VERSION 5.8 ;
BUSBITCHARS "[]" ;
DIVIDERCHAR "/" ;
UNITS
    DATABASE MICRONS 1000 ;
END UNITS

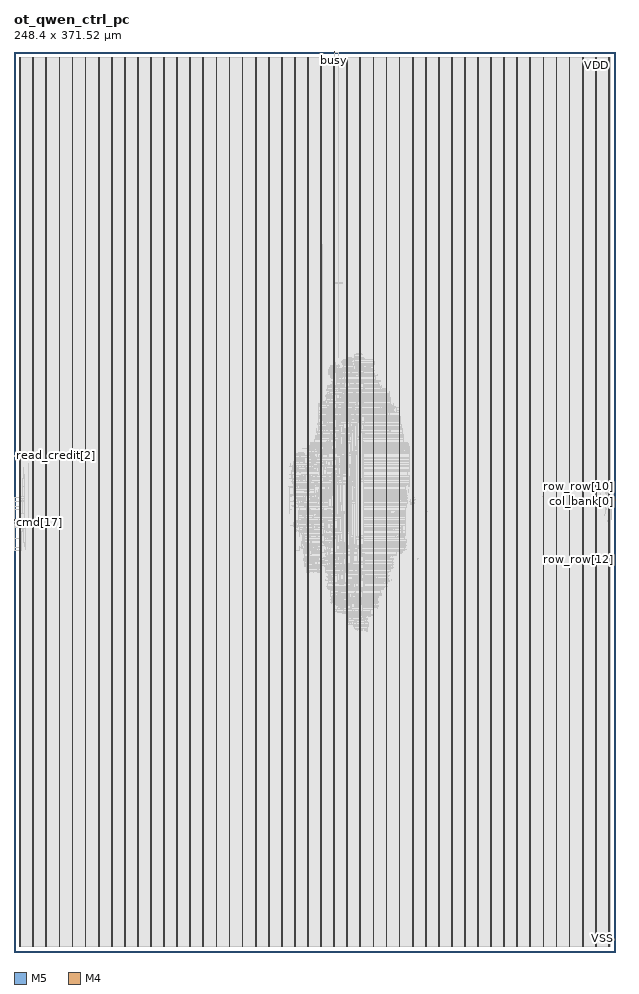
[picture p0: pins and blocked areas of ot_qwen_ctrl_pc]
MACRO ot_qwen_ctrl_pc
  FOREIGN ot_qwen_ctrl_pc 0 0 ;
  CLASS BLOCK ;
  SIZE 248.4 BY 371.52 ;
  PIN busy
    DIRECTION OUTPUT ;
    USE SIGNAL ;
    PORT
      LAYER M5 ;
        RECT  132.144 371.436 132.168 371.52 ;
    END
  END busy
  PIN clk
    DIRECTION INPUT ;
    USE SIGNAL ;
    PORT
      LAYER M5 ;
        RECT  132.24 371.436 132.264 371.52 ;
    END
  END clk
  PIN cmd[0]
    DIRECTION INPUT ;
    USE SIGNAL ;
    PORT
      LAYER M4 ;
        RECT  0 175.728 0.084 175.752 ;
    END
  END cmd[0]
  PIN cmd[10]
    DIRECTION INPUT ;
    USE SIGNAL ;
    PORT
      LAYER M4 ;
        RECT  0 176.688 0.084 176.712 ;
    END
  END cmd[10]
  PIN cmd[11]
    DIRECTION INPUT ;
    USE SIGNAL ;
    PORT
      LAYER M4 ;
        RECT  0 176.784 0.084 176.808 ;
    END
  END cmd[11]
  PIN cmd[12]
    DIRECTION INPUT ;
    USE SIGNAL ;
    PORT
      LAYER M4 ;
        RECT  0 176.88 0.084 176.904 ;
    END
  END cmd[12]
  PIN cmd[13]
    DIRECTION INPUT ;
    USE SIGNAL ;
    PORT
      LAYER M4 ;
        RECT  0 176.976 0.084 177 ;
    END
  END cmd[13]
  PIN cmd[14]
    DIRECTION INPUT ;
    USE SIGNAL ;
    PORT
      LAYER M4 ;
        RECT  0 177.072 0.084 177.096 ;
    END
  END cmd[14]
  PIN cmd[15]
    DIRECTION INPUT ;
    USE SIGNAL ;
    PORT
      LAYER M4 ;
        RECT  0 177.168 0.084 177.192 ;
    END
  END cmd[15]
  PIN cmd[16]
    DIRECTION INPUT ;
    USE SIGNAL ;
    PORT
      LAYER M4 ;
        RECT  0 177.264 0.084 177.288 ;
    END
  END cmd[16]
  PIN cmd[17]
    DIRECTION INPUT ;
    USE SIGNAL ;
    PORT
      LAYER M4 ;
        RECT  0 177.36 0.084 177.384 ;
    END
  END cmd[17]
  PIN cmd[18]
    DIRECTION INPUT ;
    USE SIGNAL ;
    PORT
      LAYER M4 ;
        RECT  0 177.456 0.084 177.48 ;
    END
  END cmd[18]
  PIN cmd[19]
    DIRECTION INPUT ;
    USE SIGNAL ;
    PORT
      LAYER M4 ;
        RECT  0 177.552 0.084 177.576 ;
    END
  END cmd[19]
  PIN cmd[1]
    DIRECTION INPUT ;
    USE SIGNAL ;
    PORT
      LAYER M4 ;
        RECT  0 175.824 0.084 175.848 ;
    END
  END cmd[1]
  PIN cmd[20]
    DIRECTION INPUT ;
    USE SIGNAL ;
    PORT
      LAYER M4 ;
        RECT  0 177.648 0.084 177.672 ;
    END
  END cmd[20]
  PIN cmd[21]
    DIRECTION INPUT ;
    USE SIGNAL ;
    PORT
      LAYER M4 ;
        RECT  0 177.744 0.084 177.768 ;
    END
  END cmd[21]
  PIN cmd[22]
    DIRECTION INPUT ;
    USE SIGNAL ;
    PORT
      LAYER M4 ;
        RECT  0 177.84 0.084 177.864 ;
    END
  END cmd[22]
  PIN cmd[23]
    DIRECTION INPUT ;
    USE SIGNAL ;
    PORT
      LAYER M4 ;
        RECT  0 177.936 0.084 177.96 ;
    END
  END cmd[23]
  PIN cmd[24]
    DIRECTION INPUT ;
    USE SIGNAL ;
    PORT
      LAYER M4 ;
        RECT  0 178.032 0.084 178.056 ;
    END
  END cmd[24]
  PIN cmd[25]
    DIRECTION INPUT ;
    USE SIGNAL ;
    PORT
      LAYER M4 ;
        RECT  0 178.128 0.084 178.152 ;
    END
  END cmd[25]
  PIN cmd[26]
    DIRECTION INPUT ;
    USE SIGNAL ;
    PORT
      LAYER M4 ;
        RECT  0 178.224 0.084 178.248 ;
    END
  END cmd[26]
  PIN cmd[27]
    DIRECTION INPUT ;
    USE SIGNAL ;
    PORT
      LAYER M4 ;
        RECT  0 178.32 0.084 178.344 ;
    END
  END cmd[27]
  PIN cmd[28]
    DIRECTION INPUT ;
    USE SIGNAL ;
    PORT
      LAYER M4 ;
        RECT  0 178.416 0.084 178.44 ;
    END
  END cmd[28]
  PIN cmd[29]
    DIRECTION INPUT ;
    USE SIGNAL ;
    PORT
      LAYER M4 ;
        RECT  0 178.512 0.084 178.536 ;
    END
  END cmd[29]
  PIN cmd[2]
    DIRECTION INPUT ;
    USE SIGNAL ;
    PORT
      LAYER M4 ;
        RECT  0 175.92 0.084 175.944 ;
    END
  END cmd[2]
  PIN cmd[30]
    DIRECTION INPUT ;
    USE SIGNAL ;
    PORT
      LAYER M4 ;
        RECT  0 178.608 0.084 178.632 ;
    END
  END cmd[30]
  PIN cmd[31]
    DIRECTION INPUT ;
    USE SIGNAL ;
    PORT
      LAYER M4 ;
        RECT  0 178.704 0.084 178.728 ;
    END
  END cmd[31]
  PIN cmd[3]
    DIRECTION INPUT ;
    USE SIGNAL ;
    PORT
      LAYER M4 ;
        RECT  0 176.016 0.084 176.04 ;
    END
  END cmd[3]
  PIN cmd[4]
    DIRECTION INPUT ;
    USE SIGNAL ;
    PORT
      LAYER M4 ;
        RECT  0 176.112 0.084 176.136 ;
    END
  END cmd[4]
  PIN cmd[5]
    DIRECTION INPUT ;
    USE SIGNAL ;
    PORT
      LAYER M4 ;
        RECT  0 176.208 0.084 176.232 ;
    END
  END cmd[5]
  PIN cmd[6]
    DIRECTION INPUT ;
    USE SIGNAL ;
    PORT
      LAYER M4 ;
        RECT  0 176.304 0.084 176.328 ;
    END
  END cmd[6]
  PIN cmd[7]
    DIRECTION INPUT ;
    USE SIGNAL ;
    PORT
      LAYER M4 ;
        RECT  0 176.4 0.084 176.424 ;
    END
  END cmd[7]
  PIN cmd[8]
    DIRECTION INPUT ;
    USE SIGNAL ;
    PORT
      LAYER M4 ;
        RECT  0 176.496 0.084 176.52 ;
    END
  END cmd[8]
  PIN cmd[9]
    DIRECTION INPUT ;
    USE SIGNAL ;
    PORT
      LAYER M4 ;
        RECT  0 176.592 0.084 176.616 ;
    END
  END cmd[9]
  PIN cmd_credit
    DIRECTION OUTPUT ;
    USE SIGNAL ;
    PORT
      LAYER M4 ;
        RECT  0 204.72 0.084 204.744 ;
    END
  END cmd_credit
  PIN cmd_v
    DIRECTION INPUT ;
    USE SIGNAL ;
    PORT
      LAYER M4 ;
        RECT  0 204.816 0.084 204.84 ;
    END
  END cmd_v
  PIN col_bank[0]
    DIRECTION OUTPUT ;
    USE SIGNAL ;
    PORT
      LAYER M4 ;
        RECT  248.316 185.808 248.4 185.832 ;
    END
  END col_bank[0]
  PIN col_bank[1]
    DIRECTION OUTPUT ;
    USE SIGNAL ;
    PORT
      LAYER M4 ;
        RECT  248.316 185.904 248.4 185.928 ;
    END
  END col_bank[1]
  PIN col_bank[2]
    DIRECTION OUTPUT ;
    USE SIGNAL ;
    PORT
      LAYER M4 ;
        RECT  248.316 186 248.4 186.024 ;
    END
  END col_bank[2]
  PIN col_bank[3]
    DIRECTION OUTPUT ;
    USE SIGNAL ;
    PORT
      LAYER M4 ;
        RECT  248.316 186.096 248.4 186.12 ;
    END
  END col_bank[3]
  PIN col_bank[4]
    DIRECTION OUTPUT ;
    USE SIGNAL ;
    PORT
      LAYER M4 ;
        RECT  248.316 186.192 248.4 186.216 ;
    END
  END col_bank[4]
  PIN col_col[0]
    DIRECTION OUTPUT ;
    USE SIGNAL ;
    PORT
      LAYER M4 ;
        RECT  248.316 186.288 248.4 186.312 ;
    END
  END col_col[0]
  PIN col_col[1]
    DIRECTION OUTPUT ;
    USE SIGNAL ;
    PORT
      LAYER M4 ;
        RECT  248.316 186.384 248.4 186.408 ;
    END
  END col_col[1]
  PIN col_col[2]
    DIRECTION OUTPUT ;
    USE SIGNAL ;
    PORT
      LAYER M4 ;
        RECT  248.316 186.48 248.4 186.504 ;
    END
  END col_col[2]
  PIN col_col[3]
    DIRECTION OUTPUT ;
    USE SIGNAL ;
    PORT
      LAYER M4 ;
        RECT  248.316 186.576 248.4 186.6 ;
    END
  END col_col[3]
  PIN col_col[4]
    DIRECTION OUTPUT ;
    USE SIGNAL ;
    PORT
      LAYER M4 ;
        RECT  248.316 186.672 248.4 186.696 ;
    END
  END col_col[4]
  PIN col_v
    DIRECTION OUTPUT ;
    USE SIGNAL ;
    PORT
      LAYER M4 ;
        RECT  248.316 186.768 248.4 186.792 ;
    END
  END col_v
  PIN col_we
    DIRECTION OUTPUT ;
    USE SIGNAL ;
    PORT
      LAYER M4 ;
        RECT  248.316 186.864 248.4 186.888 ;
    END
  END col_we
  PIN fault
    DIRECTION OUTPUT ;
    USE SIGNAL ;
    PORT
      LAYER M5 ;
        RECT  132.336 371.436 132.36 371.52 ;
    END
  END fault
  PIN read_credit[0]
    DIRECTION INPUT ;
    USE SIGNAL ;
    PORT
      LAYER M4 ;
        RECT  0 204.912 0.084 204.936 ;
    END
  END read_credit[0]
  PIN read_credit[1]
    DIRECTION INPUT ;
    USE SIGNAL ;
    PORT
      LAYER M4 ;
        RECT  0 205.008 0.084 205.032 ;
    END
  END read_credit[1]
  PIN read_credit[2]
    DIRECTION INPUT ;
    USE SIGNAL ;
    PORT
      LAYER M4 ;
        RECT  0 205.104 0.084 205.128 ;
    END
  END read_credit[2]
  PIN row_bank[0]
    DIRECTION OUTPUT ;
    USE SIGNAL ;
    PORT
      LAYER M4 ;
        RECT  248.316 186.96 248.4 186.984 ;
    END
  END row_bank[0]
  PIN row_bank[1]
    DIRECTION OUTPUT ;
    USE SIGNAL ;
    PORT
      LAYER M4 ;
        RECT  248.316 187.056 248.4 187.08 ;
    END
  END row_bank[1]
  PIN row_bank[2]
    DIRECTION OUTPUT ;
    USE SIGNAL ;
    PORT
      LAYER M4 ;
        RECT  248.316 187.152 248.4 187.176 ;
    END
  END row_bank[2]
  PIN row_bank[3]
    DIRECTION OUTPUT ;
    USE SIGNAL ;
    PORT
      LAYER M4 ;
        RECT  248.316 187.248 248.4 187.272 ;
    END
  END row_bank[3]
  PIN row_bank[4]
    DIRECTION OUTPUT ;
    USE SIGNAL ;
    PORT
      LAYER M4 ;
        RECT  248.316 187.344 248.4 187.368 ;
    END
  END row_bank[4]
  PIN row_op[0]
    DIRECTION OUTPUT ;
    USE SIGNAL ;
    PORT
      LAYER M4 ;
        RECT  248.316 187.44 248.4 187.464 ;
    END
  END row_op[0]
  PIN row_op[1]
    DIRECTION OUTPUT ;
    USE SIGNAL ;
    PORT
      LAYER M4 ;
        RECT  248.316 187.536 248.4 187.56 ;
    END
  END row_op[1]
  PIN row_op[2]
    DIRECTION OUTPUT ;
    USE SIGNAL ;
    PORT
      LAYER M4 ;
        RECT  248.316 187.632 248.4 187.656 ;
    END
  END row_op[2]
  PIN row_row[0]
    DIRECTION OUTPUT ;
    USE SIGNAL ;
    PORT
      LAYER M4 ;
        RECT  248.316 187.728 248.4 187.752 ;
    END
  END row_row[0]
  PIN row_row[10]
    DIRECTION OUTPUT ;
    USE SIGNAL ;
    PORT
      LAYER M4 ;
        RECT  248.316 188.688 248.4 188.712 ;
    END
  END row_row[10]
  PIN row_row[11]
    DIRECTION OUTPUT ;
    USE SIGNAL ;
    PORT
      LAYER M4 ;
        RECT  248.316 188.784 248.4 188.808 ;
    END
  END row_row[11]
  PIN row_row[12]
    DIRECTION OUTPUT ;
    USE SIGNAL ;
    PORT
      LAYER M4 ;
        RECT  248.316 162 248.4 162.024 ;
    END
  END row_row[12]
  PIN row_row[13]
    DIRECTION OUTPUT ;
    USE SIGNAL ;
    PORT
      LAYER M4 ;
        RECT  248.316 162.096 248.4 162.12 ;
    END
  END row_row[13]
  PIN row_row[14]
    DIRECTION OUTPUT ;
    USE SIGNAL ;
    PORT
      LAYER M4 ;
        RECT  248.316 162.192 248.4 162.216 ;
    END
  END row_row[14]
  PIN row_row[15]
    DIRECTION OUTPUT ;
    USE SIGNAL ;
    PORT
      LAYER M4 ;
        RECT  248.316 162.288 248.4 162.312 ;
    END
  END row_row[15]
  PIN row_row[16]
    DIRECTION OUTPUT ;
    USE SIGNAL ;
    PORT
      LAYER M4 ;
        RECT  248.316 162.384 248.4 162.408 ;
    END
  END row_row[16]
  PIN row_row[17]
    DIRECTION OUTPUT ;
    USE SIGNAL ;
    PORT
      LAYER M4 ;
        RECT  248.316 162.48 248.4 162.504 ;
    END
  END row_row[17]
  PIN row_row[18]
    DIRECTION OUTPUT ;
    USE SIGNAL ;
    PORT
      LAYER M4 ;
        RECT  248.316 162.576 248.4 162.6 ;
    END
  END row_row[18]
  PIN row_row[1]
    DIRECTION OUTPUT ;
    USE SIGNAL ;
    PORT
      LAYER M4 ;
        RECT  248.316 187.824 248.4 187.848 ;
    END
  END row_row[1]
  PIN row_row[2]
    DIRECTION OUTPUT ;
    USE SIGNAL ;
    PORT
      LAYER M4 ;
        RECT  248.316 187.92 248.4 187.944 ;
    END
  END row_row[2]
  PIN row_row[3]
    DIRECTION OUTPUT ;
    USE SIGNAL ;
    PORT
      LAYER M4 ;
        RECT  248.316 188.016 248.4 188.04 ;
    END
  END row_row[3]
  PIN row_row[4]
    DIRECTION OUTPUT ;
    USE SIGNAL ;
    PORT
      LAYER M4 ;
        RECT  248.316 188.112 248.4 188.136 ;
    END
  END row_row[4]
  PIN row_row[5]
    DIRECTION OUTPUT ;
    USE SIGNAL ;
    PORT
      LAYER M4 ;
        RECT  248.316 188.208 248.4 188.232 ;
    END
  END row_row[5]
  PIN row_row[6]
    DIRECTION OUTPUT ;
    USE SIGNAL ;
    PORT
      LAYER M4 ;
        RECT  248.316 188.304 248.4 188.328 ;
    END
  END row_row[6]
  PIN row_row[7]
    DIRECTION OUTPUT ;
    USE SIGNAL ;
    PORT
      LAYER M4 ;
        RECT  248.316 188.4 248.4 188.424 ;
    END
  END row_row[7]
  PIN row_row[8]
    DIRECTION OUTPUT ;
    USE SIGNAL ;
    PORT
      LAYER M4 ;
        RECT  248.316 188.496 248.4 188.52 ;
    END
  END row_row[8]
  PIN row_row[9]
    DIRECTION OUTPUT ;
    USE SIGNAL ;
    PORT
      LAYER M4 ;
        RECT  248.316 188.592 248.4 188.616 ;
    END
  END row_row[9]
  PIN row_v
    DIRECTION OUTPUT ;
    USE SIGNAL ;
    PORT
      LAYER M4 ;
        RECT  248.316 162.672 248.4 162.696 ;
    END
  END row_v
  PIN rst_n
    DIRECTION INPUT ;
    USE SIGNAL ;
    PORT
      LAYER M5 ;
        RECT  132.432 371.436 132.456 371.52 ;
    END
  END rst_n
  PIN VDD
    DIRECTION INOUT ;
    USE POWER ;
    PORT
      LAYER M5 ;
        RECT  245.592 2.151 245.712 369.369 ;
        RECT  240.192 2.151 240.312 369.369 ;
        RECT  234.792 2.151 234.912 369.369 ;
        RECT  229.392 2.151 229.512 369.369 ;
        RECT  223.992 2.151 224.112 369.369 ;
        RECT  218.592 2.151 218.712 369.369 ;
        RECT  213.192 2.151 213.312 369.369 ;
        RECT  207.792 2.151 207.912 369.369 ;
        RECT  202.392 2.151 202.512 369.369 ;
        RECT  196.992 2.151 197.112 369.369 ;
        RECT  191.592 2.151 191.712 369.369 ;
        RECT  186.192 2.151 186.312 369.369 ;
        RECT  180.792 2.151 180.912 369.369 ;
        RECT  175.392 2.151 175.512 369.369 ;
        RECT  169.992 2.151 170.112 369.369 ;
        RECT  164.592 2.151 164.712 369.369 ;
        RECT  159.192 2.151 159.312 369.369 ;
        RECT  153.792 2.151 153.912 369.369 ;
        RECT  148.392 2.151 148.512 369.369 ;
        RECT  142.992 2.151 143.112 369.369 ;
        RECT  137.592 2.151 137.712 369.369 ;
        RECT  132.192 2.151 132.312 369.369 ;
        RECT  126.792 2.151 126.912 369.369 ;
        RECT  121.392 2.151 121.512 369.369 ;
        RECT  115.992 2.151 116.112 369.369 ;
        RECT  110.592 2.151 110.712 369.369 ;
        RECT  105.192 2.151 105.312 369.369 ;
        RECT  99.792 2.151 99.912 369.369 ;
        RECT  94.392 2.151 94.512 369.369 ;
        RECT  88.992 2.151 89.112 369.369 ;
        RECT  83.592 2.151 83.712 369.369 ;
        RECT  78.192 2.151 78.312 369.369 ;
        RECT  72.792 2.151 72.912 369.369 ;
        RECT  67.392 2.151 67.512 369.369 ;
        RECT  61.992 2.151 62.112 369.369 ;
        RECT  56.592 2.151 56.712 369.369 ;
        RECT  51.192 2.151 51.312 369.369 ;
        RECT  45.792 2.151 45.912 369.369 ;
        RECT  40.392 2.151 40.512 369.369 ;
        RECT  34.992 2.151 35.112 369.369 ;
        RECT  29.592 2.151 29.712 369.369 ;
        RECT  24.192 2.151 24.312 369.369 ;
        RECT  18.792 2.151 18.912 369.369 ;
        RECT  13.392 2.151 13.512 369.369 ;
        RECT  7.992 2.151 8.112 369.369 ;
        RECT  2.592 2.151 2.712 369.369 ;
    END
  END VDD
  PIN VSS
    DIRECTION INOUT ;
    USE GROUND ;
    PORT
      LAYER M5 ;
        RECT  245.4 2.137 245.52 369.383 ;
        RECT  240 2.137 240.12 369.383 ;
        RECT  234.6 2.137 234.72 369.383 ;
        RECT  229.2 2.137 229.32 369.383 ;
        RECT  223.8 2.137 223.92 369.383 ;
        RECT  218.4 2.137 218.52 369.383 ;
        RECT  213 2.137 213.12 369.383 ;
        RECT  207.6 2.137 207.72 369.383 ;
        RECT  202.2 2.137 202.32 369.383 ;
        RECT  196.8 2.137 196.92 369.383 ;
        RECT  191.4 2.137 191.52 369.383 ;
        RECT  186 2.137 186.12 369.383 ;
        RECT  180.6 2.137 180.72 369.383 ;
        RECT  175.2 2.137 175.32 369.383 ;
        RECT  169.8 2.137 169.92 369.383 ;
        RECT  164.4 2.137 164.52 369.383 ;
        RECT  159 2.137 159.12 369.383 ;
        RECT  153.6 2.137 153.72 369.383 ;
        RECT  148.2 2.137 148.32 369.383 ;
        RECT  142.8 2.137 142.92 369.383 ;
        RECT  137.4 2.137 137.52 369.383 ;
        RECT  132 2.137 132.12 369.383 ;
        RECT  126.6 2.137 126.72 369.383 ;
        RECT  121.2 2.137 121.32 369.383 ;
        RECT  115.8 2.137 115.92 369.383 ;
        RECT  110.4 2.137 110.52 369.383 ;
        RECT  105 2.137 105.12 369.383 ;
        RECT  99.6 2.137 99.72 369.383 ;
        RECT  94.2 2.137 94.32 369.383 ;
        RECT  88.8 2.137 88.92 369.383 ;
        RECT  83.4 2.137 83.52 369.383 ;
        RECT  78 2.137 78.12 369.383 ;
        RECT  72.6 2.137 72.72 369.383 ;
        RECT  67.2 2.137 67.32 369.383 ;
        RECT  61.8 2.137 61.92 369.383 ;
        RECT  56.4 2.137 56.52 369.383 ;
        RECT  51 2.137 51.12 369.383 ;
        RECT  45.6 2.137 45.72 369.383 ;
        RECT  40.2 2.137 40.32 369.383 ;
        RECT  34.8 2.137 34.92 369.383 ;
        RECT  29.4 2.137 29.52 369.383 ;
        RECT  24 2.137 24.12 369.383 ;
        RECT  18.6 2.137 18.72 369.383 ;
        RECT  13.2 2.137 13.32 369.383 ;
        RECT  7.8 2.137 7.92 369.383 ;
        RECT  2.4 2.137 2.52 369.383 ;
    END
  END VSS
  OBS
    LAYER RVTN ;
     RECT  2.16 2.16 246.24 2.295 ;
     RECT  2.16 2.565 246.24 2.835 ;
     RECT  2.16 3.105 246.24 3.375 ;
     RECT  2.16 3.645 246.24 3.915 ;
     RECT  2.16 4.185 246.24 4.455 ;
     RECT  2.16 4.725 246.24 4.995 ;
     RECT  2.16 5.265 246.24 5.535 ;
     RECT  2.16 5.805 246.24 6.075 ;
     RECT  2.16 6.345 246.24 6.615 ;
     RECT  2.16 6.885 246.24 7.155 ;
     RECT  2.16 7.425 246.24 7.695 ;
     RECT  2.16 7.965 246.24 8.235 ;
     RECT  2.16 8.505 246.24 8.775 ;
     RECT  2.16 9.045 246.24 9.315 ;
     RECT  2.16 9.585 246.24 9.855 ;
     RECT  2.16 10.125 246.24 10.395 ;
     RECT  2.16 10.665 246.24 10.935 ;
     RECT  2.16 11.205 246.24 11.475 ;
     RECT  2.16 11.745 246.24 12.015 ;
     RECT  2.16 12.285 246.24 12.555 ;
     RECT  2.16 12.825 246.24 13.095 ;
     RECT  2.16 13.365 246.24 13.635 ;
     RECT  2.16 13.905 246.24 14.175 ;
     RECT  2.16 14.445 246.24 14.715 ;
     RECT  2.16 14.985 246.24 15.255 ;
     RECT  2.16 15.525 246.24 15.795 ;
     RECT  2.16 16.065 246.24 16.335 ;
     RECT  2.16 16.605 246.24 16.875 ;
     RECT  2.16 17.145 246.24 17.415 ;
     RECT  2.16 17.685 246.24 17.955 ;
     RECT  2.16 18.225 246.24 18.495 ;
     RECT  2.16 18.765 246.24 19.035 ;
     RECT  2.16 19.305 246.24 19.575 ;
     RECT  2.16 19.845 246.24 20.115 ;
     RECT  2.16 20.385 246.24 20.655 ;
     RECT  2.16 20.925 246.24 21.195 ;
     RECT  2.16 21.465 246.24 21.735 ;
     RECT  2.16 22.005 246.24 22.275 ;
     RECT  2.16 22.545 246.24 22.815 ;
     RECT  2.16 23.085 246.24 23.355 ;
     RECT  2.16 23.625 246.24 23.895 ;
     RECT  2.16 24.165 246.24 24.435 ;
     RECT  2.16 24.705 246.24 24.975 ;
     RECT  2.16 25.245 246.24 25.515 ;
     RECT  2.16 25.785 246.24 26.055 ;
     RECT  2.16 26.325 246.24 26.595 ;
     RECT  2.16 26.865 246.24 27.135 ;
     RECT  2.16 27.405 246.24 27.675 ;
     RECT  2.16 27.945 246.24 28.215 ;
     RECT  2.16 28.485 246.24 28.755 ;
     RECT  2.16 29.025 246.24 29.295 ;
     RECT  2.16 29.565 246.24 29.835 ;
     RECT  2.16 30.105 246.24 30.375 ;
     RECT  2.16 30.645 246.24 30.915 ;
     RECT  2.16 31.185 246.24 31.455 ;
     RECT  2.16 31.725 246.24 31.995 ;
     RECT  2.16 32.265 246.24 32.535 ;
     RECT  2.16 32.805 246.24 33.075 ;
     RECT  2.16 33.345 246.24 33.615 ;
     RECT  2.16 33.885 246.24 34.155 ;
     RECT  2.16 34.425 246.24 34.695 ;
     RECT  2.16 34.965 246.24 35.235 ;
     RECT  2.16 35.505 246.24 35.775 ;
     RECT  2.16 36.045 246.24 36.315 ;
     RECT  2.16 36.585 246.24 36.855 ;
     RECT  2.16 37.125 246.24 37.395 ;
     RECT  2.16 37.665 246.24 37.935 ;
     RECT  2.16 38.205 246.24 38.475 ;
     RECT  2.16 38.745 246.24 39.015 ;
     RECT  2.16 39.285 246.24 39.555 ;
     RECT  2.16 39.825 246.24 40.095 ;
     RECT  2.16 40.365 246.24 40.635 ;
     RECT  2.16 40.905 246.24 41.175 ;
     RECT  2.16 41.445 246.24 41.715 ;
     RECT  2.16 41.985 246.24 42.255 ;
     RECT  2.16 42.525 246.24 42.795 ;
     RECT  2.16 43.065 246.24 43.335 ;
     RECT  2.16 43.605 246.24 43.875 ;
     RECT  2.16 44.145 246.24 44.415 ;
     RECT  2.16 44.685 246.24 44.955 ;
     RECT  2.16 45.225 246.24 45.495 ;
     RECT  2.16 45.765 246.24 46.035 ;
     RECT  2.16 46.305 246.24 46.575 ;
     RECT  2.16 46.845 246.24 47.115 ;
     RECT  2.16 47.385 246.24 47.655 ;
     RECT  2.16 47.925 246.24 48.195 ;
     RECT  2.16 48.465 246.24 48.735 ;
     RECT  2.16 49.005 246.24 49.275 ;
     RECT  2.16 49.545 246.24 49.815 ;
     RECT  2.16 50.085 246.24 50.355 ;
     RECT  2.16 50.625 246.24 50.895 ;
     RECT  2.16 51.165 246.24 51.435 ;
     RECT  2.16 51.705 246.24 51.975 ;
     RECT  2.16 52.245 246.24 52.515 ;
     RECT  2.16 52.785 246.24 53.055 ;
     RECT  2.16 53.325 246.24 53.595 ;
     RECT  2.16 53.865 246.24 54.135 ;
     RECT  2.16 54.405 246.24 54.675 ;
     RECT  2.16 54.945 246.24 55.215 ;
     RECT  2.16 55.485 246.24 55.755 ;
     RECT  2.16 56.025 246.24 56.295 ;
     RECT  2.16 56.565 246.24 56.835 ;
     RECT  2.16 57.105 246.24 57.375 ;
     RECT  2.16 57.645 246.24 57.915 ;
     RECT  2.16 58.185 246.24 58.455 ;
     RECT  2.16 58.725 246.24 58.995 ;
     RECT  2.16 59.265 246.24 59.535 ;
     RECT  2.16 59.805 246.24 60.075 ;
     RECT  2.16 60.345 246.24 60.615 ;
     RECT  2.16 60.885 246.24 61.155 ;
     RECT  2.16 61.425 246.24 61.695 ;
     RECT  2.16 61.965 246.24 62.235 ;
     RECT  2.16 62.505 246.24 62.775 ;
     RECT  2.16 63.045 246.24 63.315 ;
     RECT  2.16 63.585 246.24 63.855 ;
     RECT  2.16 64.125 246.24 64.395 ;
     RECT  2.16 64.665 246.24 64.935 ;
     RECT  2.16 65.205 246.24 65.475 ;
     RECT  2.16 65.745 246.24 66.015 ;
     RECT  2.16 66.285 246.24 66.555 ;
     RECT  2.16 66.825 246.24 67.095 ;
     RECT  2.16 67.365 246.24 67.635 ;
     RECT  2.16 67.905 246.24 68.175 ;
     RECT  2.16 68.445 246.24 68.715 ;
     RECT  2.16 68.985 246.24 69.255 ;
     RECT  2.16 69.525 246.24 69.795 ;
     RECT  2.16 70.065 246.24 70.335 ;
     RECT  2.16 70.605 246.24 70.875 ;
     RECT  2.16 71.145 246.24 71.415 ;
     RECT  2.16 71.685 246.24 71.955 ;
     RECT  2.16 72.225 246.24 72.495 ;
     RECT  2.16 72.765 246.24 73.035 ;
     RECT  2.16 73.305 246.24 73.575 ;
     RECT  2.16 73.845 246.24 74.115 ;
     RECT  2.16 74.385 246.24 74.655 ;
     RECT  2.16 74.925 246.24 75.195 ;
     RECT  2.16 75.465 246.24 75.735 ;
     RECT  2.16 76.005 246.24 76.275 ;
     RECT  2.16 76.545 246.24 76.815 ;
     RECT  2.16 77.085 246.24 77.355 ;
     RECT  2.16 77.625 246.24 77.895 ;
     RECT  2.16 78.165 246.24 78.435 ;
     RECT  2.16 78.705 246.24 78.975 ;
     RECT  2.16 79.245 246.24 79.515 ;
     RECT  2.16 79.785 246.24 80.055 ;
     RECT  2.16 80.325 246.24 80.595 ;
     RECT  2.16 80.865 246.24 81.135 ;
     RECT  2.16 81.405 246.24 81.675 ;
     RECT  2.16 81.945 246.24 82.215 ;
     RECT  2.16 82.485 246.24 82.755 ;
     RECT  2.16 83.025 246.24 83.295 ;
     RECT  2.16 83.565 246.24 83.835 ;
     RECT  2.16 84.105 246.24 84.375 ;
     RECT  2.16 84.645 246.24 84.915 ;
     RECT  2.16 85.185 246.24 85.455 ;
     RECT  2.16 85.725 246.24 85.995 ;
     RECT  2.16 86.265 246.24 86.535 ;
     RECT  2.16 86.805 246.24 87.075 ;
     RECT  2.16 87.345 246.24 87.615 ;
     RECT  2.16 87.885 246.24 88.155 ;
     RECT  2.16 88.425 246.24 88.695 ;
     RECT  2.16 88.965 246.24 89.235 ;
     RECT  2.16 89.505 246.24 89.775 ;
     RECT  2.16 90.045 246.24 90.315 ;
     RECT  2.16 90.585 246.24 90.855 ;
     RECT  2.16 91.125 246.24 91.395 ;
     RECT  2.16 91.665 246.24 91.935 ;
     RECT  2.16 92.205 246.24 92.475 ;
     RECT  2.16 92.745 246.24 93.015 ;
     RECT  2.16 93.285 246.24 93.555 ;
     RECT  2.16 93.825 246.24 94.095 ;
     RECT  2.16 94.365 246.24 94.635 ;
     RECT  2.16 94.905 246.24 95.175 ;
     RECT  2.16 95.445 246.24 95.715 ;
     RECT  2.16 95.985 246.24 96.255 ;
     RECT  2.16 96.525 246.24 96.795 ;
     RECT  2.16 97.065 246.24 97.335 ;
     RECT  2.16 97.605 246.24 97.875 ;
     RECT  2.16 98.145 246.24 98.415 ;
     RECT  2.16 98.685 246.24 98.955 ;
     RECT  2.16 99.225 246.24 99.495 ;
     RECT  2.16 99.765 246.24 100.035 ;
     RECT  2.16 100.305 246.24 100.575 ;
     RECT  2.16 100.845 246.24 101.115 ;
     RECT  2.16 101.385 246.24 101.655 ;
     RECT  2.16 101.925 246.24 102.195 ;
     RECT  2.16 102.465 246.24 102.735 ;
     RECT  2.16 103.005 246.24 103.275 ;
     RECT  2.16 103.545 246.24 103.815 ;
     RECT  2.16 104.085 246.24 104.355 ;
     RECT  2.16 104.625 246.24 104.895 ;
     RECT  2.16 105.165 246.24 105.435 ;
     RECT  2.16 105.705 246.24 105.975 ;
     RECT  2.16 106.245 246.24 106.515 ;
     RECT  2.16 106.785 246.24 107.055 ;
     RECT  2.16 107.325 246.24 107.595 ;
     RECT  2.16 107.865 246.24 108.135 ;
     RECT  2.16 108.405 246.24 108.675 ;
     RECT  2.16 108.945 246.24 109.215 ;
     RECT  2.16 109.485 246.24 109.755 ;
     RECT  2.16 110.025 246.24 110.295 ;
     RECT  2.16 110.565 246.24 110.835 ;
     RECT  2.16 111.105 246.24 111.375 ;
     RECT  2.16 111.645 246.24 111.915 ;
     RECT  2.16 112.185 246.24 112.455 ;
     RECT  2.16 112.725 246.24 112.995 ;
     RECT  2.16 113.265 246.24 113.535 ;
     RECT  2.16 113.805 246.24 114.075 ;
     RECT  2.16 114.345 246.24 114.615 ;
     RECT  2.16 114.885 246.24 115.155 ;
     RECT  2.16 115.425 246.24 115.695 ;
     RECT  2.16 115.965 246.24 116.235 ;
     RECT  2.16 116.505 246.24 116.775 ;
     RECT  2.16 117.045 246.24 117.315 ;
     RECT  2.16 117.585 246.24 117.855 ;
     RECT  2.16 118.125 246.24 118.395 ;
     RECT  2.16 118.665 246.24 118.935 ;
     RECT  2.16 119.205 246.24 119.475 ;
     RECT  2.16 119.745 246.24 120.015 ;
     RECT  2.16 120.285 246.24 120.555 ;
     RECT  2.16 120.825 246.24 121.095 ;
     RECT  2.16 121.365 246.24 121.635 ;
     RECT  2.16 121.905 246.24 122.175 ;
     RECT  2.16 122.445 246.24 122.715 ;
     RECT  2.16 122.985 246.24 123.255 ;
     RECT  2.16 123.525 246.24 123.795 ;
     RECT  2.16 124.065 246.24 124.335 ;
     RECT  2.16 124.605 246.24 124.875 ;
     RECT  2.16 125.145 246.24 125.415 ;
     RECT  2.16 125.685 246.24 125.955 ;
     RECT  2.16 126.225 246.24 126.495 ;
     RECT  2.16 126.765 246.24 127.035 ;
     RECT  2.16 127.305 246.24 127.575 ;
     RECT  2.16 127.845 246.24 128.115 ;
     RECT  2.16 128.385 246.24 128.655 ;
     RECT  2.16 128.925 246.24 129.195 ;
     RECT  2.16 129.465 246.24 129.735 ;
     RECT  2.16 130.005 246.24 130.275 ;
     RECT  2.16 130.545 246.24 130.815 ;
     RECT  2.16 131.085 246.24 131.355 ;
     RECT  2.16 131.625 246.24 131.895 ;
     RECT  2.16 132.165 246.24 132.435 ;
     RECT  2.16 132.705 246.24 132.975 ;
     RECT  2.16 133.245 246.24 133.515 ;
     RECT  2.16 133.785 246.24 134.055 ;
     RECT  2.16 134.325 246.24 134.595 ;
     RECT  2.16 134.865 246.24 135.135 ;
     RECT  2.16 135.405 246.24 135.675 ;
     RECT  2.16 135.945 246.24 136.215 ;
     RECT  2.16 136.485 246.24 136.755 ;
     RECT  2.16 137.025 246.24 137.295 ;
     RECT  2.16 137.565 246.24 137.835 ;
     RECT  2.16 138.105 246.24 138.375 ;
     RECT  2.16 138.645 246.24 138.915 ;
     RECT  2.16 139.185 246.24 139.455 ;
     RECT  2.16 139.725 246.24 139.995 ;
     RECT  2.16 140.265 246.24 140.535 ;
     RECT  2.16 140.805 246.24 141.075 ;
     RECT  2.16 141.345 246.24 141.615 ;
     RECT  2.16 141.885 246.24 142.155 ;
     RECT  2.16 142.425 246.24 142.695 ;
     RECT  2.16 142.965 246.24 143.235 ;
     RECT  2.16 143.505 246.24 143.775 ;
     RECT  2.16 144.045 246.24 144.315 ;
     RECT  2.16 144.585 246.24 144.855 ;
     RECT  2.16 145.125 246.24 145.395 ;
     RECT  2.16 145.665 246.24 145.935 ;
     RECT  2.16 146.205 246.24 146.475 ;
     RECT  2.16 146.745 246.24 147.015 ;
     RECT  2.16 147.285 246.24 147.555 ;
     RECT  2.16 147.825 246.24 148.095 ;
     RECT  2.16 148.365 246.24 148.635 ;
     RECT  2.16 148.905 246.24 149.175 ;
     RECT  2.16 149.445 246.24 149.715 ;
     RECT  2.16 149.985 246.24 150.255 ;
     RECT  2.16 150.525 246.24 150.795 ;
     RECT  2.16 151.065 246.24 151.335 ;
     RECT  2.16 151.605 246.24 151.875 ;
     RECT  2.16 152.145 246.24 152.415 ;
     RECT  2.16 152.685 246.24 152.955 ;
     RECT  2.16 153.225 246.24 153.495 ;
     RECT  2.16 153.765 246.24 154.035 ;
     RECT  2.16 154.305 246.24 154.575 ;
     RECT  2.16 154.845 246.24 155.115 ;
     RECT  2.16 155.385 246.24 155.655 ;
     RECT  2.16 155.925 246.24 156.195 ;
     RECT  2.16 156.465 246.24 156.735 ;
     RECT  2.16 157.005 246.24 157.275 ;
     RECT  2.16 157.545 246.24 157.815 ;
     RECT  2.16 158.085 246.24 158.355 ;
     RECT  2.16 158.625 246.24 158.895 ;
     RECT  2.16 159.165 246.24 159.435 ;
     RECT  2.16 159.705 246.24 159.975 ;
     RECT  2.16 160.245 246.24 160.515 ;
     RECT  2.16 160.785 246.24 161.055 ;
     RECT  2.16 161.325 246.24 161.595 ;
     RECT  2.16 161.865 246.24 162.135 ;
     RECT  2.16 162.405 246.24 162.675 ;
     RECT  2.16 162.945 246.24 163.215 ;
     RECT  2.16 163.485 246.24 163.755 ;
     RECT  2.16 164.025 246.24 164.295 ;
     RECT  2.16 164.565 246.24 164.835 ;
     RECT  2.16 165.105 246.24 165.375 ;
     RECT  2.16 165.645 246.24 165.915 ;
     RECT  2.16 166.185 246.24 166.455 ;
     RECT  2.16 166.725 246.24 166.995 ;
     RECT  2.16 167.265 246.24 167.535 ;
     RECT  2.16 167.805 246.24 168.075 ;
     RECT  2.16 168.345 246.24 168.615 ;
     RECT  2.16 168.885 246.24 169.155 ;
     RECT  2.16 169.425 246.24 169.695 ;
     RECT  2.16 169.965 246.24 170.235 ;
     RECT  2.16 170.505 246.24 170.775 ;
     RECT  2.16 171.045 246.24 171.315 ;
     RECT  2.16 171.585 246.24 171.855 ;
     RECT  2.16 172.125 246.24 172.395 ;
     RECT  2.16 172.665 246.24 172.935 ;
     RECT  2.16 173.205 246.24 173.475 ;
     RECT  2.16 173.745 246.24 174.015 ;
     RECT  2.16 174.285 246.24 174.555 ;
     RECT  2.16 174.825 246.24 175.095 ;
     RECT  2.16 175.365 246.24 175.635 ;
     RECT  2.16 175.905 246.24 176.175 ;
     RECT  2.16 176.445 246.24 176.715 ;
     RECT  2.16 176.985 246.24 177.255 ;
     RECT  2.16 177.525 246.24 177.795 ;
     RECT  2.16 178.065 246.24 178.335 ;
     RECT  2.16 178.605 246.24 178.875 ;
     RECT  2.16 179.145 246.24 179.415 ;
     RECT  2.16 179.685 246.24 179.955 ;
     RECT  2.16 180.225 246.24 180.495 ;
     RECT  2.16 180.765 246.24 181.035 ;
     RECT  2.16 181.305 246.24 181.575 ;
     RECT  2.16 181.845 246.24 182.115 ;
     RECT  2.16 182.385 246.24 182.655 ;
     RECT  2.16 182.925 246.24 183.195 ;
     RECT  2.16 183.465 246.24 183.735 ;
     RECT  2.16 184.005 246.24 184.275 ;
     RECT  2.16 184.545 246.24 184.815 ;
     RECT  2.16 185.085 246.24 185.355 ;
     RECT  2.16 185.625 246.24 185.895 ;
     RECT  2.16 186.165 246.24 186.435 ;
     RECT  2.16 186.705 246.24 186.975 ;
     RECT  2.16 187.245 246.24 187.515 ;
     RECT  2.16 187.785 246.24 188.055 ;
     RECT  2.16 188.325 246.24 188.595 ;
     RECT  2.16 188.865 246.24 189.135 ;
     RECT  2.16 189.405 246.24 189.675 ;
     RECT  2.16 189.945 246.24 190.215 ;
     RECT  2.16 190.485 246.24 190.755 ;
     RECT  2.16 191.025 246.24 191.295 ;
     RECT  2.16 191.565 246.24 191.835 ;
     RECT  2.16 192.105 246.24 192.375 ;
     RECT  2.16 192.645 246.24 192.915 ;
     RECT  2.16 193.185 246.24 193.455 ;
     RECT  2.16 193.725 246.24 193.995 ;
     RECT  2.16 194.265 246.24 194.535 ;
     RECT  2.16 194.805 246.24 195.075 ;
     RECT  2.16 195.345 246.24 195.615 ;
     RECT  2.16 195.885 246.24 196.155 ;
     RECT  2.16 196.425 246.24 196.695 ;
     RECT  2.16 196.965 246.24 197.235 ;
     RECT  2.16 197.505 246.24 197.775 ;
     RECT  2.16 198.045 246.24 198.315 ;
     RECT  2.16 198.585 246.24 198.855 ;
     RECT  2.16 199.125 246.24 199.395 ;
     RECT  2.16 199.665 246.24 199.935 ;
     RECT  2.16 200.205 246.24 200.475 ;
     RECT  2.16 200.745 246.24 201.015 ;
     RECT  2.16 201.285 246.24 201.555 ;
     RECT  2.16 201.825 246.24 202.095 ;
     RECT  2.16 202.365 246.24 202.635 ;
     RECT  2.16 202.905 246.24 203.175 ;
     RECT  2.16 203.445 246.24 203.715 ;
     RECT  2.16 203.985 246.24 204.255 ;
     RECT  2.16 204.525 246.24 204.795 ;
     RECT  2.16 205.065 246.24 205.335 ;
     RECT  2.16 205.605 246.24 205.875 ;
     RECT  2.16 206.145 246.24 206.415 ;
     RECT  2.16 206.685 246.24 206.955 ;
     RECT  2.16 207.225 246.24 207.495 ;
     RECT  2.16 207.765 246.24 208.035 ;
     RECT  2.16 208.305 246.24 208.575 ;
     RECT  2.16 208.845 246.24 209.115 ;
     RECT  2.16 209.385 246.24 209.655 ;
     RECT  2.16 209.925 246.24 210.195 ;
     RECT  2.16 210.465 246.24 210.735 ;
     RECT  2.16 211.005 246.24 211.275 ;
     RECT  2.16 211.545 246.24 211.815 ;
     RECT  2.16 212.085 246.24 212.355 ;
     RECT  2.16 212.625 246.24 212.895 ;
     RECT  2.16 213.165 246.24 213.435 ;
     RECT  2.16 213.705 246.24 213.975 ;
     RECT  2.16 214.245 246.24 214.515 ;
     RECT  2.16 214.785 246.24 215.055 ;
     RECT  2.16 215.325 246.24 215.595 ;
     RECT  2.16 215.865 246.24 216.135 ;
     RECT  2.16 216.405 246.24 216.675 ;
     RECT  2.16 216.945 246.24 217.215 ;
     RECT  2.16 217.485 246.24 217.755 ;
     RECT  2.16 218.025 246.24 218.295 ;
     RECT  2.16 218.565 246.24 218.835 ;
     RECT  2.16 219.105 246.24 219.375 ;
     RECT  2.16 219.645 246.24 219.915 ;
     RECT  2.16 220.185 246.24 220.455 ;
     RECT  2.16 220.725 246.24 220.995 ;
     RECT  2.16 221.265 246.24 221.535 ;
     RECT  2.16 221.805 246.24 222.075 ;
     RECT  2.16 222.345 246.24 222.615 ;
     RECT  2.16 222.885 246.24 223.155 ;
     RECT  2.16 223.425 246.24 223.695 ;
     RECT  2.16 223.965 246.24 224.235 ;
     RECT  2.16 224.505 246.24 224.775 ;
     RECT  2.16 225.045 246.24 225.315 ;
     RECT  2.16 225.585 246.24 225.855 ;
     RECT  2.16 226.125 246.24 226.395 ;
     RECT  2.16 226.665 246.24 226.935 ;
     RECT  2.16 227.205 246.24 227.475 ;
     RECT  2.16 227.745 246.24 228.015 ;
     RECT  2.16 228.285 246.24 228.555 ;
     RECT  2.16 228.825 246.24 229.095 ;
     RECT  2.16 229.365 246.24 229.635 ;
     RECT  2.16 229.905 246.24 230.175 ;
     RECT  2.16 230.445 246.24 230.715 ;
     RECT  2.16 230.985 246.24 231.255 ;
     RECT  2.16 231.525 246.24 231.795 ;
     RECT  2.16 232.065 246.24 232.335 ;
     RECT  2.16 232.605 246.24 232.875 ;
     RECT  2.16 233.145 246.24 233.415 ;
     RECT  2.16 233.685 246.24 233.955 ;
     RECT  2.16 234.225 246.24 234.495 ;
     RECT  2.16 234.765 246.24 235.035 ;
     RECT  2.16 235.305 246.24 235.575 ;
     RECT  2.16 235.845 246.24 236.115 ;
     RECT  2.16 236.385 246.24 236.655 ;
     RECT  2.16 236.925 246.24 237.195 ;
     RECT  2.16 237.465 246.24 237.735 ;
     RECT  2.16 238.005 246.24 238.275 ;
     RECT  2.16 238.545 246.24 238.815 ;
     RECT  2.16 239.085 246.24 239.355 ;
     RECT  2.16 239.625 246.24 239.895 ;
     RECT  2.16 240.165 246.24 240.435 ;
     RECT  2.16 240.705 246.24 240.975 ;
     RECT  2.16 241.245 246.24 241.515 ;
     RECT  2.16 241.785 246.24 242.055 ;
     RECT  2.16 242.325 246.24 242.595 ;
     RECT  2.16 242.865 246.24 243.135 ;
     RECT  2.16 243.405 246.24 243.675 ;
     RECT  2.16 243.945 246.24 244.215 ;
     RECT  2.16 244.485 246.24 244.755 ;
     RECT  2.16 245.025 246.24 245.295 ;
     RECT  2.16 245.565 246.24 245.835 ;
     RECT  2.16 246.105 246.24 246.375 ;
     RECT  2.16 246.645 246.24 246.915 ;
     RECT  2.16 247.185 246.24 247.455 ;
     RECT  2.16 247.725 246.24 247.995 ;
     RECT  2.16 248.265 246.24 248.535 ;
     RECT  2.16 248.805 246.24 249.075 ;
     RECT  2.16 249.345 246.24 249.615 ;
     RECT  2.16 249.885 246.24 250.155 ;
     RECT  2.16 250.425 246.24 250.695 ;
     RECT  2.16 250.965 246.24 251.235 ;
     RECT  2.16 251.505 246.24 251.775 ;
     RECT  2.16 252.045 246.24 252.315 ;
     RECT  2.16 252.585 246.24 252.855 ;
     RECT  2.16 253.125 246.24 253.395 ;
     RECT  2.16 253.665 246.24 253.935 ;
     RECT  2.16 254.205 246.24 254.475 ;
     RECT  2.16 254.745 246.24 255.015 ;
     RECT  2.16 255.285 246.24 255.555 ;
     RECT  2.16 255.825 246.24 256.095 ;
     RECT  2.16 256.365 246.24 256.635 ;
     RECT  2.16 256.905 246.24 257.175 ;
     RECT  2.16 257.445 246.24 257.715 ;
     RECT  2.16 257.985 246.24 258.255 ;
     RECT  2.16 258.525 246.24 258.795 ;
     RECT  2.16 259.065 246.24 259.335 ;
     RECT  2.16 259.605 246.24 259.875 ;
     RECT  2.16 260.145 246.24 260.415 ;
     RECT  2.16 260.685 246.24 260.955 ;
     RECT  2.16 261.225 246.24 261.495 ;
     RECT  2.16 261.765 246.24 262.035 ;
     RECT  2.16 262.305 246.24 262.575 ;
     RECT  2.16 262.845 246.24 263.115 ;
     RECT  2.16 263.385 246.24 263.655 ;
     RECT  2.16 263.925 246.24 264.195 ;
     RECT  2.16 264.465 246.24 264.735 ;
     RECT  2.16 265.005 246.24 265.275 ;
     RECT  2.16 265.545 246.24 265.815 ;
     RECT  2.16 266.085 246.24 266.355 ;
     RECT  2.16 266.625 246.24 266.895 ;
     RECT  2.16 267.165 246.24 267.435 ;
     RECT  2.16 267.705 246.24 267.975 ;
     RECT  2.16 268.245 246.24 268.515 ;
     RECT  2.16 268.785 246.24 269.055 ;
     RECT  2.16 269.325 246.24 269.595 ;
     RECT  2.16 269.865 246.24 270.135 ;
     RECT  2.16 270.405 246.24 270.675 ;
     RECT  2.16 270.945 246.24 271.215 ;
     RECT  2.16 271.485 246.24 271.755 ;
     RECT  2.16 272.025 246.24 272.295 ;
     RECT  2.16 272.565 246.24 272.835 ;
     RECT  2.16 273.105 246.24 273.375 ;
     RECT  2.16 273.645 246.24 273.915 ;
     RECT  2.16 274.185 246.24 274.455 ;
     RECT  2.16 274.725 246.24 274.995 ;
     RECT  2.16 275.265 246.24 275.535 ;
     RECT  2.16 275.805 246.24 276.075 ;
     RECT  2.16 276.345 246.24 276.615 ;
     RECT  2.16 276.885 246.24 277.155 ;
     RECT  2.16 277.425 246.24 277.695 ;
     RECT  2.16 277.965 246.24 278.235 ;
     RECT  2.16 278.505 246.24 278.775 ;
     RECT  2.16 279.045 246.24 279.315 ;
     RECT  2.16 279.585 246.24 279.855 ;
     RECT  2.16 280.125 246.24 280.395 ;
     RECT  2.16 280.665 246.24 280.935 ;
     RECT  2.16 281.205 246.24 281.475 ;
     RECT  2.16 281.745 246.24 282.015 ;
     RECT  2.16 282.285 246.24 282.555 ;
     RECT  2.16 282.825 246.24 283.095 ;
     RECT  2.16 283.365 246.24 283.635 ;
     RECT  2.16 283.905 246.24 284.175 ;
     RECT  2.16 284.445 246.24 284.715 ;
     RECT  2.16 284.985 246.24 285.255 ;
     RECT  2.16 285.525 246.24 285.795 ;
     RECT  2.16 286.065 246.24 286.335 ;
     RECT  2.16 286.605 246.24 286.875 ;
     RECT  2.16 287.145 246.24 287.415 ;
     RECT  2.16 287.685 246.24 287.955 ;
     RECT  2.16 288.225 246.24 288.495 ;
     RECT  2.16 288.765 246.24 289.035 ;
     RECT  2.16 289.305 246.24 289.575 ;
     RECT  2.16 289.845 246.24 290.115 ;
     RECT  2.16 290.385 246.24 290.655 ;
     RECT  2.16 290.925 246.24 291.195 ;
     RECT  2.16 291.465 246.24 291.735 ;
     RECT  2.16 292.005 246.24 292.275 ;
     RECT  2.16 292.545 246.24 292.815 ;
     RECT  2.16 293.085 246.24 293.355 ;
     RECT  2.16 293.625 246.24 293.895 ;
     RECT  2.16 294.165 246.24 294.435 ;
     RECT  2.16 294.705 246.24 294.975 ;
     RECT  2.16 295.245 246.24 295.515 ;
     RECT  2.16 295.785 246.24 296.055 ;
     RECT  2.16 296.325 246.24 296.595 ;
     RECT  2.16 296.865 246.24 297.135 ;
     RECT  2.16 297.405 246.24 297.675 ;
     RECT  2.16 297.945 246.24 298.215 ;
     RECT  2.16 298.485 246.24 298.755 ;
     RECT  2.16 299.025 246.24 299.295 ;
     RECT  2.16 299.565 246.24 299.835 ;
     RECT  2.16 300.105 246.24 300.375 ;
     RECT  2.16 300.645 246.24 300.915 ;
     RECT  2.16 301.185 246.24 301.455 ;
     RECT  2.16 301.725 246.24 301.995 ;
     RECT  2.16 302.265 246.24 302.535 ;
     RECT  2.16 302.805 246.24 303.075 ;
     RECT  2.16 303.345 246.24 303.615 ;
     RECT  2.16 303.885 246.24 304.155 ;
     RECT  2.16 304.425 246.24 304.695 ;
     RECT  2.16 304.965 246.24 305.235 ;
     RECT  2.16 305.505 246.24 305.775 ;
     RECT  2.16 306.045 246.24 306.315 ;
     RECT  2.16 306.585 246.24 306.855 ;
     RECT  2.16 307.125 246.24 307.395 ;
     RECT  2.16 307.665 246.24 307.935 ;
     RECT  2.16 308.205 246.24 308.475 ;
     RECT  2.16 308.745 246.24 309.015 ;
     RECT  2.16 309.285 246.24 309.555 ;
     RECT  2.16 309.825 246.24 310.095 ;
     RECT  2.16 310.365 246.24 310.635 ;
     RECT  2.16 310.905 246.24 311.175 ;
     RECT  2.16 311.445 246.24 311.715 ;
     RECT  2.16 311.985 246.24 312.255 ;
     RECT  2.16 312.525 246.24 312.795 ;
     RECT  2.16 313.065 246.24 313.335 ;
     RECT  2.16 313.605 246.24 313.875 ;
     RECT  2.16 314.145 246.24 314.415 ;
     RECT  2.16 314.685 246.24 314.955 ;
     RECT  2.16 315.225 246.24 315.495 ;
     RECT  2.16 315.765 246.24 316.035 ;
     RECT  2.16 316.305 246.24 316.575 ;
     RECT  2.16 316.845 246.24 317.115 ;
     RECT  2.16 317.385 246.24 317.655 ;
     RECT  2.16 317.925 246.24 318.195 ;
     RECT  2.16 318.465 246.24 318.735 ;
     RECT  2.16 319.005 246.24 319.275 ;
     RECT  2.16 319.545 246.24 319.815 ;
     RECT  2.16 320.085 246.24 320.355 ;
     RECT  2.16 320.625 246.24 320.895 ;
     RECT  2.16 321.165 246.24 321.435 ;
     RECT  2.16 321.705 246.24 321.975 ;
     RECT  2.16 322.245 246.24 322.515 ;
     RECT  2.16 322.785 246.24 323.055 ;
     RECT  2.16 323.325 246.24 323.595 ;
     RECT  2.16 323.865 246.24 324.135 ;
     RECT  2.16 324.405 246.24 324.675 ;
     RECT  2.16 324.945 246.24 325.215 ;
     RECT  2.16 325.485 246.24 325.755 ;
     RECT  2.16 326.025 246.24 326.295 ;
     RECT  2.16 326.565 246.24 326.835 ;
     RECT  2.16 327.105 246.24 327.375 ;
     RECT  2.16 327.645 246.24 327.915 ;
     RECT  2.16 328.185 246.24 328.455 ;
     RECT  2.16 328.725 246.24 328.995 ;
     RECT  2.16 329.265 246.24 329.535 ;
     RECT  2.16 329.805 246.24 330.075 ;
     RECT  2.16 330.345 246.24 330.615 ;
     RECT  2.16 330.885 246.24 331.155 ;
     RECT  2.16 331.425 246.24 331.695 ;
     RECT  2.16 331.965 246.24 332.235 ;
     RECT  2.16 332.505 246.24 332.775 ;
     RECT  2.16 333.045 246.24 333.315 ;
     RECT  2.16 333.585 246.24 333.855 ;
     RECT  2.16 334.125 246.24 334.395 ;
     RECT  2.16 334.665 246.24 334.935 ;
     RECT  2.16 335.205 246.24 335.475 ;
     RECT  2.16 335.745 246.24 336.015 ;
     RECT  2.16 336.285 246.24 336.555 ;
     RECT  2.16 336.825 246.24 337.095 ;
     RECT  2.16 337.365 246.24 337.635 ;
     RECT  2.16 337.905 246.24 338.175 ;
     RECT  2.16 338.445 246.24 338.715 ;
     RECT  2.16 338.985 246.24 339.255 ;
     RECT  2.16 339.525 246.24 339.795 ;
     RECT  2.16 340.065 246.24 340.335 ;
     RECT  2.16 340.605 246.24 340.875 ;
     RECT  2.16 341.145 246.24 341.415 ;
     RECT  2.16 341.685 246.24 341.955 ;
     RECT  2.16 342.225 246.24 342.495 ;
     RECT  2.16 342.765 246.24 343.035 ;
     RECT  2.16 343.305 246.24 343.575 ;
     RECT  2.16 343.845 246.24 344.115 ;
     RECT  2.16 344.385 246.24 344.655 ;
     RECT  2.16 344.925 246.24 345.195 ;
     RECT  2.16 345.465 246.24 345.735 ;
     RECT  2.16 346.005 246.24 346.275 ;
     RECT  2.16 346.545 246.24 346.815 ;
     RECT  2.16 347.085 246.24 347.355 ;
     RECT  2.16 347.625 246.24 347.895 ;
     RECT  2.16 348.165 246.24 348.435 ;
     RECT  2.16 348.705 246.24 348.975 ;
     RECT  2.16 349.245 246.24 349.515 ;
     RECT  2.16 349.785 246.24 350.055 ;
     RECT  2.16 350.325 246.24 350.595 ;
     RECT  2.16 350.865 246.24 351.135 ;
     RECT  2.16 351.405 246.24 351.675 ;
     RECT  2.16 351.945 246.24 352.215 ;
     RECT  2.16 352.485 246.24 352.755 ;
     RECT  2.16 353.025 246.24 353.295 ;
     RECT  2.16 353.565 246.24 353.835 ;
     RECT  2.16 354.105 246.24 354.375 ;
     RECT  2.16 354.645 246.24 354.915 ;
     RECT  2.16 355.185 246.24 355.455 ;
     RECT  2.16 355.725 246.24 355.995 ;
     RECT  2.16 356.265 246.24 356.535 ;
     RECT  2.16 356.805 246.24 357.075 ;
     RECT  2.16 357.345 246.24 357.615 ;
     RECT  2.16 357.885 246.24 358.155 ;
     RECT  2.16 358.425 246.24 358.695 ;
     RECT  2.16 358.965 246.24 359.235 ;
     RECT  2.16 359.505 246.24 359.775 ;
     RECT  2.16 360.045 246.24 360.315 ;
     RECT  2.16 360.585 246.24 360.855 ;
     RECT  2.16 361.125 246.24 361.395 ;
     RECT  2.16 361.665 246.24 361.935 ;
     RECT  2.16 362.205 246.24 362.475 ;
     RECT  2.16 362.745 246.24 363.015 ;
     RECT  2.16 363.285 246.24 363.555 ;
     RECT  2.16 363.825 246.24 364.095 ;
     RECT  2.16 364.365 246.24 364.635 ;
     RECT  2.16 364.905 246.24 365.175 ;
     RECT  2.16 365.445 246.24 365.715 ;
     RECT  2.16 365.985 246.24 366.255 ;
     RECT  2.16 366.525 246.24 366.795 ;
     RECT  2.16 367.065 246.24 367.335 ;
     RECT  2.16 367.605 246.24 367.875 ;
     RECT  2.16 368.145 246.24 368.415 ;
     RECT  2.16 368.685 246.24 368.955 ;
     RECT  2.16 369.225 246.24 369.36 ;
    LAYER RVTP ;
     RECT  2.16 2.295 246.24 2.565 ;
     RECT  2.16 2.835 246.24 3.105 ;
     RECT  2.16 3.375 246.24 3.645 ;
     RECT  2.16 3.915 246.24 4.185 ;
     RECT  2.16 4.455 246.24 4.725 ;
     RECT  2.16 4.995 246.24 5.265 ;
     RECT  2.16 5.535 246.24 5.805 ;
     RECT  2.16 6.075 246.24 6.345 ;
     RECT  2.16 6.615 246.24 6.885 ;
     RECT  2.16 7.155 246.24 7.425 ;
     RECT  2.16 7.695 246.24 7.965 ;
     RECT  2.16 8.235 246.24 8.505 ;
     RECT  2.16 8.775 246.24 9.045 ;
     RECT  2.16 9.315 246.24 9.585 ;
     RECT  2.16 9.855 246.24 10.125 ;
     RECT  2.16 10.395 246.24 10.665 ;
     RECT  2.16 10.935 246.24 11.205 ;
     RECT  2.16 11.475 246.24 11.745 ;
     RECT  2.16 12.015 246.24 12.285 ;
     RECT  2.16 12.555 246.24 12.825 ;
     RECT  2.16 13.095 246.24 13.365 ;
     RECT  2.16 13.635 246.24 13.905 ;
     RECT  2.16 14.175 246.24 14.445 ;
     RECT  2.16 14.715 246.24 14.985 ;
     RECT  2.16 15.255 246.24 15.525 ;
     RECT  2.16 15.795 246.24 16.065 ;
     RECT  2.16 16.335 246.24 16.605 ;
     RECT  2.16 16.875 246.24 17.145 ;
     RECT  2.16 17.415 246.24 17.685 ;
     RECT  2.16 17.955 246.24 18.225 ;
     RECT  2.16 18.495 246.24 18.765 ;
     RECT  2.16 19.035 246.24 19.305 ;
     RECT  2.16 19.575 246.24 19.845 ;
     RECT  2.16 20.115 246.24 20.385 ;
     RECT  2.16 20.655 246.24 20.925 ;
     RECT  2.16 21.195 246.24 21.465 ;
     RECT  2.16 21.735 246.24 22.005 ;
     RECT  2.16 22.275 246.24 22.545 ;
     RECT  2.16 22.815 246.24 23.085 ;
     RECT  2.16 23.355 246.24 23.625 ;
     RECT  2.16 23.895 246.24 24.165 ;
     RECT  2.16 24.435 246.24 24.705 ;
     RECT  2.16 24.975 246.24 25.245 ;
     RECT  2.16 25.515 246.24 25.785 ;
     RECT  2.16 26.055 246.24 26.325 ;
     RECT  2.16 26.595 246.24 26.865 ;
     RECT  2.16 27.135 246.24 27.405 ;
     RECT  2.16 27.675 246.24 27.945 ;
     RECT  2.16 28.215 246.24 28.485 ;
     RECT  2.16 28.755 246.24 29.025 ;
     RECT  2.16 29.295 246.24 29.565 ;
     RECT  2.16 29.835 246.24 30.105 ;
     RECT  2.16 30.375 246.24 30.645 ;
     RECT  2.16 30.915 246.24 31.185 ;
     RECT  2.16 31.455 246.24 31.725 ;
     RECT  2.16 31.995 246.24 32.265 ;
     RECT  2.16 32.535 246.24 32.805 ;
     RECT  2.16 33.075 246.24 33.345 ;
     RECT  2.16 33.615 246.24 33.885 ;
     RECT  2.16 34.155 246.24 34.425 ;
     RECT  2.16 34.695 246.24 34.965 ;
     RECT  2.16 35.235 246.24 35.505 ;
     RECT  2.16 35.775 246.24 36.045 ;
     RECT  2.16 36.315 246.24 36.585 ;
     RECT  2.16 36.855 246.24 37.125 ;
     RECT  2.16 37.395 246.24 37.665 ;
     RECT  2.16 37.935 246.24 38.205 ;
     RECT  2.16 38.475 246.24 38.745 ;
     RECT  2.16 39.015 246.24 39.285 ;
     RECT  2.16 39.555 246.24 39.825 ;
     RECT  2.16 40.095 246.24 40.365 ;
     RECT  2.16 40.635 246.24 40.905 ;
     RECT  2.16 41.175 246.24 41.445 ;
     RECT  2.16 41.715 246.24 41.985 ;
     RECT  2.16 42.255 246.24 42.525 ;
     RECT  2.16 42.795 246.24 43.065 ;
     RECT  2.16 43.335 246.24 43.605 ;
     RECT  2.16 43.875 246.24 44.145 ;
     RECT  2.16 44.415 246.24 44.685 ;
     RECT  2.16 44.955 246.24 45.225 ;
     RECT  2.16 45.495 246.24 45.765 ;
     RECT  2.16 46.035 246.24 46.305 ;
     RECT  2.16 46.575 246.24 46.845 ;
     RECT  2.16 47.115 246.24 47.385 ;
     RECT  2.16 47.655 246.24 47.925 ;
     RECT  2.16 48.195 246.24 48.465 ;
     RECT  2.16 48.735 246.24 49.005 ;
     RECT  2.16 49.275 246.24 49.545 ;
     RECT  2.16 49.815 246.24 50.085 ;
     RECT  2.16 50.355 246.24 50.625 ;
     RECT  2.16 50.895 246.24 51.165 ;
     RECT  2.16 51.435 246.24 51.705 ;
     RECT  2.16 51.975 246.24 52.245 ;
     RECT  2.16 52.515 246.24 52.785 ;
     RECT  2.16 53.055 246.24 53.325 ;
     RECT  2.16 53.595 246.24 53.865 ;
     RECT  2.16 54.135 246.24 54.405 ;
     RECT  2.16 54.675 246.24 54.945 ;
     RECT  2.16 55.215 246.24 55.485 ;
     RECT  2.16 55.755 246.24 56.025 ;
     RECT  2.16 56.295 246.24 56.565 ;
     RECT  2.16 56.835 246.24 57.105 ;
     RECT  2.16 57.375 246.24 57.645 ;
     RECT  2.16 57.915 246.24 58.185 ;
     RECT  2.16 58.455 246.24 58.725 ;
     RECT  2.16 58.995 246.24 59.265 ;
     RECT  2.16 59.535 246.24 59.805 ;
     RECT  2.16 60.075 246.24 60.345 ;
     RECT  2.16 60.615 246.24 60.885 ;
     RECT  2.16 61.155 246.24 61.425 ;
     RECT  2.16 61.695 246.24 61.965 ;
     RECT  2.16 62.235 246.24 62.505 ;
     RECT  2.16 62.775 246.24 63.045 ;
     RECT  2.16 63.315 246.24 63.585 ;
     RECT  2.16 63.855 246.24 64.125 ;
     RECT  2.16 64.395 246.24 64.665 ;
     RECT  2.16 64.935 246.24 65.205 ;
     RECT  2.16 65.475 246.24 65.745 ;
     RECT  2.16 66.015 246.24 66.285 ;
     RECT  2.16 66.555 246.24 66.825 ;
     RECT  2.16 67.095 246.24 67.365 ;
     RECT  2.16 67.635 246.24 67.905 ;
     RECT  2.16 68.175 246.24 68.445 ;
     RECT  2.16 68.715 246.24 68.985 ;
     RECT  2.16 69.255 246.24 69.525 ;
     RECT  2.16 69.795 246.24 70.065 ;
     RECT  2.16 70.335 246.24 70.605 ;
     RECT  2.16 70.875 246.24 71.145 ;
     RECT  2.16 71.415 246.24 71.685 ;
     RECT  2.16 71.955 246.24 72.225 ;
     RECT  2.16 72.495 246.24 72.765 ;
     RECT  2.16 73.035 246.24 73.305 ;
     RECT  2.16 73.575 246.24 73.845 ;
     RECT  2.16 74.115 246.24 74.385 ;
     RECT  2.16 74.655 246.24 74.925 ;
     RECT  2.16 75.195 246.24 75.465 ;
     RECT  2.16 75.735 246.24 76.005 ;
     RECT  2.16 76.275 246.24 76.545 ;
     RECT  2.16 76.815 246.24 77.085 ;
     RECT  2.16 77.355 246.24 77.625 ;
     RECT  2.16 77.895 246.24 78.165 ;
     RECT  2.16 78.435 246.24 78.705 ;
     RECT  2.16 78.975 246.24 79.245 ;
     RECT  2.16 79.515 246.24 79.785 ;
     RECT  2.16 80.055 246.24 80.325 ;
     RECT  2.16 80.595 246.24 80.865 ;
     RECT  2.16 81.135 246.24 81.405 ;
     RECT  2.16 81.675 246.24 81.945 ;
     RECT  2.16 82.215 246.24 82.485 ;
     RECT  2.16 82.755 246.24 83.025 ;
     RECT  2.16 83.295 246.24 83.565 ;
     RECT  2.16 83.835 246.24 84.105 ;
     RECT  2.16 84.375 246.24 84.645 ;
     RECT  2.16 84.915 246.24 85.185 ;
     RECT  2.16 85.455 246.24 85.725 ;
     RECT  2.16 85.995 246.24 86.265 ;
     RECT  2.16 86.535 246.24 86.805 ;
     RECT  2.16 87.075 246.24 87.345 ;
     RECT  2.16 87.615 246.24 87.885 ;
     RECT  2.16 88.155 246.24 88.425 ;
     RECT  2.16 88.695 246.24 88.965 ;
     RECT  2.16 89.235 246.24 89.505 ;
     RECT  2.16 89.775 246.24 90.045 ;
     RECT  2.16 90.315 246.24 90.585 ;
     RECT  2.16 90.855 246.24 91.125 ;
     RECT  2.16 91.395 246.24 91.665 ;
     RECT  2.16 91.935 246.24 92.205 ;
     RECT  2.16 92.475 246.24 92.745 ;
     RECT  2.16 93.015 246.24 93.285 ;
     RECT  2.16 93.555 246.24 93.825 ;
     RECT  2.16 94.095 246.24 94.365 ;
     RECT  2.16 94.635 246.24 94.905 ;
     RECT  2.16 95.175 246.24 95.445 ;
     RECT  2.16 95.715 246.24 95.985 ;
     RECT  2.16 96.255 246.24 96.525 ;
     RECT  2.16 96.795 246.24 97.065 ;
     RECT  2.16 97.335 246.24 97.605 ;
     RECT  2.16 97.875 246.24 98.145 ;
     RECT  2.16 98.415 246.24 98.685 ;
     RECT  2.16 98.955 246.24 99.225 ;
     RECT  2.16 99.495 246.24 99.765 ;
     RECT  2.16 100.035 246.24 100.305 ;
     RECT  2.16 100.575 246.24 100.845 ;
     RECT  2.16 101.115 246.24 101.385 ;
     RECT  2.16 101.655 246.24 101.925 ;
     RECT  2.16 102.195 246.24 102.465 ;
     RECT  2.16 102.735 246.24 103.005 ;
     RECT  2.16 103.275 246.24 103.545 ;
     RECT  2.16 103.815 246.24 104.085 ;
     RECT  2.16 104.355 246.24 104.625 ;
     RECT  2.16 104.895 246.24 105.165 ;
     RECT  2.16 105.435 246.24 105.705 ;
     RECT  2.16 105.975 246.24 106.245 ;
     RECT  2.16 106.515 246.24 106.785 ;
     RECT  2.16 107.055 246.24 107.325 ;
     RECT  2.16 107.595 246.24 107.865 ;
     RECT  2.16 108.135 246.24 108.405 ;
     RECT  2.16 108.675 246.24 108.945 ;
     RECT  2.16 109.215 246.24 109.485 ;
     RECT  2.16 109.755 246.24 110.025 ;
     RECT  2.16 110.295 246.24 110.565 ;
     RECT  2.16 110.835 246.24 111.105 ;
     RECT  2.16 111.375 246.24 111.645 ;
     RECT  2.16 111.915 246.24 112.185 ;
     RECT  2.16 112.455 246.24 112.725 ;
     RECT  2.16 112.995 246.24 113.265 ;
     RECT  2.16 113.535 246.24 113.805 ;
     RECT  2.16 114.075 246.24 114.345 ;
     RECT  2.16 114.615 246.24 114.885 ;
     RECT  2.16 115.155 246.24 115.425 ;
     RECT  2.16 115.695 246.24 115.965 ;
     RECT  2.16 116.235 246.24 116.505 ;
     RECT  2.16 116.775 246.24 117.045 ;
     RECT  2.16 117.315 246.24 117.585 ;
     RECT  2.16 117.855 246.24 118.125 ;
     RECT  2.16 118.395 246.24 118.665 ;
     RECT  2.16 118.935 246.24 119.205 ;
     RECT  2.16 119.475 246.24 119.745 ;
     RECT  2.16 120.015 246.24 120.285 ;
     RECT  2.16 120.555 246.24 120.825 ;
     RECT  2.16 121.095 246.24 121.365 ;
     RECT  2.16 121.635 246.24 121.905 ;
     RECT  2.16 122.175 246.24 122.445 ;
     RECT  2.16 122.715 246.24 122.985 ;
     RECT  2.16 123.255 246.24 123.525 ;
     RECT  2.16 123.795 246.24 124.065 ;
     RECT  2.16 124.335 246.24 124.605 ;
     RECT  2.16 124.875 246.24 125.145 ;
     RECT  2.16 125.415 246.24 125.685 ;
     RECT  2.16 125.955 246.24 126.225 ;
     RECT  2.16 126.495 246.24 126.765 ;
     RECT  2.16 127.035 246.24 127.305 ;
     RECT  2.16 127.575 246.24 127.845 ;
     RECT  2.16 128.115 246.24 128.385 ;
     RECT  2.16 128.655 246.24 128.925 ;
     RECT  2.16 129.195 246.24 129.465 ;
     RECT  2.16 129.735 246.24 130.005 ;
     RECT  2.16 130.275 246.24 130.545 ;
     RECT  2.16 130.815 246.24 131.085 ;
     RECT  2.16 131.355 246.24 131.625 ;
     RECT  2.16 131.895 246.24 132.165 ;
     RECT  2.16 132.435 246.24 132.705 ;
     RECT  2.16 132.975 246.24 133.245 ;
     RECT  2.16 133.515 246.24 133.785 ;
     RECT  2.16 134.055 246.24 134.325 ;
     RECT  2.16 134.595 246.24 134.865 ;
     RECT  2.16 135.135 246.24 135.405 ;
     RECT  2.16 135.675 246.24 135.945 ;
     RECT  2.16 136.215 246.24 136.485 ;
     RECT  2.16 136.755 246.24 137.025 ;
     RECT  2.16 137.295 246.24 137.565 ;
     RECT  2.16 137.835 246.24 138.105 ;
     RECT  2.16 138.375 246.24 138.645 ;
     RECT  2.16 138.915 246.24 139.185 ;
     RECT  2.16 139.455 246.24 139.725 ;
     RECT  2.16 139.995 246.24 140.265 ;
     RECT  2.16 140.535 246.24 140.805 ;
     RECT  2.16 141.075 246.24 141.345 ;
     RECT  2.16 141.615 246.24 141.885 ;
     RECT  2.16 142.155 246.24 142.425 ;
     RECT  2.16 142.695 246.24 142.965 ;
     RECT  2.16 143.235 246.24 143.505 ;
     RECT  2.16 143.775 246.24 144.045 ;
     RECT  2.16 144.315 246.24 144.585 ;
     RECT  2.16 144.855 246.24 145.125 ;
     RECT  2.16 145.395 246.24 145.665 ;
     RECT  2.16 145.935 246.24 146.205 ;
     RECT  2.16 146.475 246.24 146.745 ;
     RECT  2.16 147.015 246.24 147.285 ;
     RECT  2.16 147.555 246.24 147.825 ;
     RECT  2.16 148.095 246.24 148.365 ;
     RECT  2.16 148.635 246.24 148.905 ;
     RECT  2.16 149.175 246.24 149.445 ;
     RECT  2.16 149.715 246.24 149.985 ;
     RECT  2.16 150.255 246.24 150.525 ;
     RECT  2.16 150.795 246.24 151.065 ;
     RECT  2.16 151.335 246.24 151.605 ;
     RECT  2.16 151.875 246.24 152.145 ;
     RECT  2.16 152.415 246.24 152.685 ;
     RECT  2.16 152.955 246.24 153.225 ;
     RECT  2.16 153.495 246.24 153.765 ;
     RECT  2.16 154.035 246.24 154.305 ;
     RECT  2.16 154.575 246.24 154.845 ;
     RECT  2.16 155.115 246.24 155.385 ;
     RECT  2.16 155.655 246.24 155.925 ;
     RECT  2.16 156.195 246.24 156.465 ;
     RECT  2.16 156.735 246.24 157.005 ;
     RECT  2.16 157.275 246.24 157.545 ;
     RECT  2.16 157.815 246.24 158.085 ;
     RECT  2.16 158.355 246.24 158.625 ;
     RECT  2.16 158.895 246.24 159.165 ;
     RECT  2.16 159.435 246.24 159.705 ;
     RECT  2.16 159.975 246.24 160.245 ;
     RECT  2.16 160.515 246.24 160.785 ;
     RECT  2.16 161.055 246.24 161.325 ;
     RECT  2.16 161.595 246.24 161.865 ;
     RECT  2.16 162.135 246.24 162.405 ;
     RECT  2.16 162.675 246.24 162.945 ;
     RECT  2.16 163.215 246.24 163.485 ;
     RECT  2.16 163.755 246.24 164.025 ;
     RECT  2.16 164.295 246.24 164.565 ;
     RECT  2.16 164.835 246.24 165.105 ;
     RECT  2.16 165.375 246.24 165.645 ;
     RECT  2.16 165.915 246.24 166.185 ;
     RECT  2.16 166.455 246.24 166.725 ;
     RECT  2.16 166.995 246.24 167.265 ;
     RECT  2.16 167.535 246.24 167.805 ;
     RECT  2.16 168.075 246.24 168.345 ;
     RECT  2.16 168.615 246.24 168.885 ;
     RECT  2.16 169.155 246.24 169.425 ;
     RECT  2.16 169.695 246.24 169.965 ;
     RECT  2.16 170.235 246.24 170.505 ;
     RECT  2.16 170.775 246.24 171.045 ;
     RECT  2.16 171.315 246.24 171.585 ;
     RECT  2.16 171.855 246.24 172.125 ;
     RECT  2.16 172.395 246.24 172.665 ;
     RECT  2.16 172.935 246.24 173.205 ;
     RECT  2.16 173.475 246.24 173.745 ;
     RECT  2.16 174.015 246.24 174.285 ;
     RECT  2.16 174.555 246.24 174.825 ;
     RECT  2.16 175.095 246.24 175.365 ;
     RECT  2.16 175.635 246.24 175.905 ;
     RECT  2.16 176.175 246.24 176.445 ;
     RECT  2.16 176.715 246.24 176.985 ;
     RECT  2.16 177.255 246.24 177.525 ;
     RECT  2.16 177.795 246.24 178.065 ;
     RECT  2.16 178.335 246.24 178.605 ;
     RECT  2.16 178.875 246.24 179.145 ;
     RECT  2.16 179.415 246.24 179.685 ;
     RECT  2.16 179.955 246.24 180.225 ;
     RECT  2.16 180.495 246.24 180.765 ;
     RECT  2.16 181.035 246.24 181.305 ;
     RECT  2.16 181.575 246.24 181.845 ;
     RECT  2.16 182.115 246.24 182.385 ;
     RECT  2.16 182.655 246.24 182.925 ;
     RECT  2.16 183.195 246.24 183.465 ;
     RECT  2.16 183.735 246.24 184.005 ;
     RECT  2.16 184.275 246.24 184.545 ;
     RECT  2.16 184.815 246.24 185.085 ;
     RECT  2.16 185.355 246.24 185.625 ;
     RECT  2.16 185.895 246.24 186.165 ;
     RECT  2.16 186.435 246.24 186.705 ;
     RECT  2.16 186.975 246.24 187.245 ;
     RECT  2.16 187.515 246.24 187.785 ;
     RECT  2.16 188.055 246.24 188.325 ;
     RECT  2.16 188.595 246.24 188.865 ;
     RECT  2.16 189.135 246.24 189.405 ;
     RECT  2.16 189.675 246.24 189.945 ;
     RECT  2.16 190.215 246.24 190.485 ;
     RECT  2.16 190.755 246.24 191.025 ;
     RECT  2.16 191.295 246.24 191.565 ;
     RECT  2.16 191.835 246.24 192.105 ;
     RECT  2.16 192.375 246.24 192.645 ;
     RECT  2.16 192.915 246.24 193.185 ;
     RECT  2.16 193.455 246.24 193.725 ;
     RECT  2.16 193.995 246.24 194.265 ;
     RECT  2.16 194.535 246.24 194.805 ;
     RECT  2.16 195.075 246.24 195.345 ;
     RECT  2.16 195.615 246.24 195.885 ;
     RECT  2.16 196.155 246.24 196.425 ;
     RECT  2.16 196.695 246.24 196.965 ;
     RECT  2.16 197.235 246.24 197.505 ;
     RECT  2.16 197.775 246.24 198.045 ;
     RECT  2.16 198.315 246.24 198.585 ;
     RECT  2.16 198.855 246.24 199.125 ;
     RECT  2.16 199.395 246.24 199.665 ;
     RECT  2.16 199.935 246.24 200.205 ;
     RECT  2.16 200.475 246.24 200.745 ;
     RECT  2.16 201.015 246.24 201.285 ;
     RECT  2.16 201.555 246.24 201.825 ;
     RECT  2.16 202.095 246.24 202.365 ;
     RECT  2.16 202.635 246.24 202.905 ;
     RECT  2.16 203.175 246.24 203.445 ;
     RECT  2.16 203.715 246.24 203.985 ;
     RECT  2.16 204.255 246.24 204.525 ;
     RECT  2.16 204.795 246.24 205.065 ;
     RECT  2.16 205.335 246.24 205.605 ;
     RECT  2.16 205.875 246.24 206.145 ;
     RECT  2.16 206.415 246.24 206.685 ;
     RECT  2.16 206.955 246.24 207.225 ;
     RECT  2.16 207.495 246.24 207.765 ;
     RECT  2.16 208.035 246.24 208.305 ;
     RECT  2.16 208.575 246.24 208.845 ;
     RECT  2.16 209.115 246.24 209.385 ;
     RECT  2.16 209.655 246.24 209.925 ;
     RECT  2.16 210.195 246.24 210.465 ;
     RECT  2.16 210.735 246.24 211.005 ;
     RECT  2.16 211.275 246.24 211.545 ;
     RECT  2.16 211.815 246.24 212.085 ;
     RECT  2.16 212.355 246.24 212.625 ;
     RECT  2.16 212.895 246.24 213.165 ;
     RECT  2.16 213.435 246.24 213.705 ;
     RECT  2.16 213.975 246.24 214.245 ;
     RECT  2.16 214.515 246.24 214.785 ;
     RECT  2.16 215.055 246.24 215.325 ;
     RECT  2.16 215.595 246.24 215.865 ;
     RECT  2.16 216.135 246.24 216.405 ;
     RECT  2.16 216.675 246.24 216.945 ;
     RECT  2.16 217.215 246.24 217.485 ;
     RECT  2.16 217.755 246.24 218.025 ;
     RECT  2.16 218.295 246.24 218.565 ;
     RECT  2.16 218.835 246.24 219.105 ;
     RECT  2.16 219.375 246.24 219.645 ;
     RECT  2.16 219.915 246.24 220.185 ;
     RECT  2.16 220.455 246.24 220.725 ;
     RECT  2.16 220.995 246.24 221.265 ;
     RECT  2.16 221.535 246.24 221.805 ;
     RECT  2.16 222.075 246.24 222.345 ;
     RECT  2.16 222.615 246.24 222.885 ;
     RECT  2.16 223.155 246.24 223.425 ;
     RECT  2.16 223.695 246.24 223.965 ;
     RECT  2.16 224.235 246.24 224.505 ;
     RECT  2.16 224.775 246.24 225.045 ;
     RECT  2.16 225.315 246.24 225.585 ;
     RECT  2.16 225.855 246.24 226.125 ;
     RECT  2.16 226.395 246.24 226.665 ;
     RECT  2.16 226.935 246.24 227.205 ;
     RECT  2.16 227.475 246.24 227.745 ;
     RECT  2.16 228.015 246.24 228.285 ;
     RECT  2.16 228.555 246.24 228.825 ;
     RECT  2.16 229.095 246.24 229.365 ;
     RECT  2.16 229.635 246.24 229.905 ;
     RECT  2.16 230.175 246.24 230.445 ;
     RECT  2.16 230.715 246.24 230.985 ;
     RECT  2.16 231.255 246.24 231.525 ;
     RECT  2.16 231.795 246.24 232.065 ;
     RECT  2.16 232.335 246.24 232.605 ;
     RECT  2.16 232.875 246.24 233.145 ;
     RECT  2.16 233.415 246.24 233.685 ;
     RECT  2.16 233.955 246.24 234.225 ;
     RECT  2.16 234.495 246.24 234.765 ;
     RECT  2.16 235.035 246.24 235.305 ;
     RECT  2.16 235.575 246.24 235.845 ;
     RECT  2.16 236.115 246.24 236.385 ;
     RECT  2.16 236.655 246.24 236.925 ;
     RECT  2.16 237.195 246.24 237.465 ;
     RECT  2.16 237.735 246.24 238.005 ;
     RECT  2.16 238.275 246.24 238.545 ;
     RECT  2.16 238.815 246.24 239.085 ;
     RECT  2.16 239.355 246.24 239.625 ;
     RECT  2.16 239.895 246.24 240.165 ;
     RECT  2.16 240.435 246.24 240.705 ;
     RECT  2.16 240.975 246.24 241.245 ;
     RECT  2.16 241.515 246.24 241.785 ;
     RECT  2.16 242.055 246.24 242.325 ;
     RECT  2.16 242.595 246.24 242.865 ;
     RECT  2.16 243.135 246.24 243.405 ;
     RECT  2.16 243.675 246.24 243.945 ;
     RECT  2.16 244.215 246.24 244.485 ;
     RECT  2.16 244.755 246.24 245.025 ;
     RECT  2.16 245.295 246.24 245.565 ;
     RECT  2.16 245.835 246.24 246.105 ;
     RECT  2.16 246.375 246.24 246.645 ;
     RECT  2.16 246.915 246.24 247.185 ;
     RECT  2.16 247.455 246.24 247.725 ;
     RECT  2.16 247.995 246.24 248.265 ;
     RECT  2.16 248.535 246.24 248.805 ;
     RECT  2.16 249.075 246.24 249.345 ;
     RECT  2.16 249.615 246.24 249.885 ;
     RECT  2.16 250.155 246.24 250.425 ;
     RECT  2.16 250.695 246.24 250.965 ;
     RECT  2.16 251.235 246.24 251.505 ;
     RECT  2.16 251.775 246.24 252.045 ;
     RECT  2.16 252.315 246.24 252.585 ;
     RECT  2.16 252.855 246.24 253.125 ;
     RECT  2.16 253.395 246.24 253.665 ;
     RECT  2.16 253.935 246.24 254.205 ;
     RECT  2.16 254.475 246.24 254.745 ;
     RECT  2.16 255.015 246.24 255.285 ;
     RECT  2.16 255.555 246.24 255.825 ;
     RECT  2.16 256.095 246.24 256.365 ;
     RECT  2.16 256.635 246.24 256.905 ;
     RECT  2.16 257.175 246.24 257.445 ;
     RECT  2.16 257.715 246.24 257.985 ;
     RECT  2.16 258.255 246.24 258.525 ;
     RECT  2.16 258.795 246.24 259.065 ;
     RECT  2.16 259.335 246.24 259.605 ;
     RECT  2.16 259.875 246.24 260.145 ;
     RECT  2.16 260.415 246.24 260.685 ;
     RECT  2.16 260.955 246.24 261.225 ;
     RECT  2.16 261.495 246.24 261.765 ;
     RECT  2.16 262.035 246.24 262.305 ;
     RECT  2.16 262.575 246.24 262.845 ;
     RECT  2.16 263.115 246.24 263.385 ;
     RECT  2.16 263.655 246.24 263.925 ;
     RECT  2.16 264.195 246.24 264.465 ;
     RECT  2.16 264.735 246.24 265.005 ;
     RECT  2.16 265.275 246.24 265.545 ;
     RECT  2.16 265.815 246.24 266.085 ;
     RECT  2.16 266.355 246.24 266.625 ;
     RECT  2.16 266.895 246.24 267.165 ;
     RECT  2.16 267.435 246.24 267.705 ;
     RECT  2.16 267.975 246.24 268.245 ;
     RECT  2.16 268.515 246.24 268.785 ;
     RECT  2.16 269.055 246.24 269.325 ;
     RECT  2.16 269.595 246.24 269.865 ;
     RECT  2.16 270.135 246.24 270.405 ;
     RECT  2.16 270.675 246.24 270.945 ;
     RECT  2.16 271.215 246.24 271.485 ;
     RECT  2.16 271.755 246.24 272.025 ;
     RECT  2.16 272.295 246.24 272.565 ;
     RECT  2.16 272.835 246.24 273.105 ;
     RECT  2.16 273.375 246.24 273.645 ;
     RECT  2.16 273.915 246.24 274.185 ;
     RECT  2.16 274.455 246.24 274.725 ;
     RECT  2.16 274.995 246.24 275.265 ;
     RECT  2.16 275.535 246.24 275.805 ;
     RECT  2.16 276.075 246.24 276.345 ;
     RECT  2.16 276.615 246.24 276.885 ;
     RECT  2.16 277.155 246.24 277.425 ;
     RECT  2.16 277.695 246.24 277.965 ;
     RECT  2.16 278.235 246.24 278.505 ;
     RECT  2.16 278.775 246.24 279.045 ;
     RECT  2.16 279.315 246.24 279.585 ;
     RECT  2.16 279.855 246.24 280.125 ;
     RECT  2.16 280.395 246.24 280.665 ;
     RECT  2.16 280.935 246.24 281.205 ;
     RECT  2.16 281.475 246.24 281.745 ;
     RECT  2.16 282.015 246.24 282.285 ;
     RECT  2.16 282.555 246.24 282.825 ;
     RECT  2.16 283.095 246.24 283.365 ;
     RECT  2.16 283.635 246.24 283.905 ;
     RECT  2.16 284.175 246.24 284.445 ;
     RECT  2.16 284.715 246.24 284.985 ;
     RECT  2.16 285.255 246.24 285.525 ;
     RECT  2.16 285.795 246.24 286.065 ;
     RECT  2.16 286.335 246.24 286.605 ;
     RECT  2.16 286.875 246.24 287.145 ;
     RECT  2.16 287.415 246.24 287.685 ;
     RECT  2.16 287.955 246.24 288.225 ;
     RECT  2.16 288.495 246.24 288.765 ;
     RECT  2.16 289.035 246.24 289.305 ;
     RECT  2.16 289.575 246.24 289.845 ;
     RECT  2.16 290.115 246.24 290.385 ;
     RECT  2.16 290.655 246.24 290.925 ;
     RECT  2.16 291.195 246.24 291.465 ;
     RECT  2.16 291.735 246.24 292.005 ;
     RECT  2.16 292.275 246.24 292.545 ;
     RECT  2.16 292.815 246.24 293.085 ;
     RECT  2.16 293.355 246.24 293.625 ;
     RECT  2.16 293.895 246.24 294.165 ;
     RECT  2.16 294.435 246.24 294.705 ;
     RECT  2.16 294.975 246.24 295.245 ;
     RECT  2.16 295.515 246.24 295.785 ;
     RECT  2.16 296.055 246.24 296.325 ;
     RECT  2.16 296.595 246.24 296.865 ;
     RECT  2.16 297.135 246.24 297.405 ;
     RECT  2.16 297.675 246.24 297.945 ;
     RECT  2.16 298.215 246.24 298.485 ;
     RECT  2.16 298.755 246.24 299.025 ;
     RECT  2.16 299.295 246.24 299.565 ;
     RECT  2.16 299.835 246.24 300.105 ;
     RECT  2.16 300.375 246.24 300.645 ;
     RECT  2.16 300.915 246.24 301.185 ;
     RECT  2.16 301.455 246.24 301.725 ;
     RECT  2.16 301.995 246.24 302.265 ;
     RECT  2.16 302.535 246.24 302.805 ;
     RECT  2.16 303.075 246.24 303.345 ;
     RECT  2.16 303.615 246.24 303.885 ;
     RECT  2.16 304.155 246.24 304.425 ;
     RECT  2.16 304.695 246.24 304.965 ;
     RECT  2.16 305.235 246.24 305.505 ;
     RECT  2.16 305.775 246.24 306.045 ;
     RECT  2.16 306.315 246.24 306.585 ;
     RECT  2.16 306.855 246.24 307.125 ;
     RECT  2.16 307.395 246.24 307.665 ;
     RECT  2.16 307.935 246.24 308.205 ;
     RECT  2.16 308.475 246.24 308.745 ;
     RECT  2.16 309.015 246.24 309.285 ;
     RECT  2.16 309.555 246.24 309.825 ;
     RECT  2.16 310.095 246.24 310.365 ;
     RECT  2.16 310.635 246.24 310.905 ;
     RECT  2.16 311.175 246.24 311.445 ;
     RECT  2.16 311.715 246.24 311.985 ;
     RECT  2.16 312.255 246.24 312.525 ;
     RECT  2.16 312.795 246.24 313.065 ;
     RECT  2.16 313.335 246.24 313.605 ;
     RECT  2.16 313.875 246.24 314.145 ;
     RECT  2.16 314.415 246.24 314.685 ;
     RECT  2.16 314.955 246.24 315.225 ;
     RECT  2.16 315.495 246.24 315.765 ;
     RECT  2.16 316.035 246.24 316.305 ;
     RECT  2.16 316.575 246.24 316.845 ;
     RECT  2.16 317.115 246.24 317.385 ;
     RECT  2.16 317.655 246.24 317.925 ;
     RECT  2.16 318.195 246.24 318.465 ;
     RECT  2.16 318.735 246.24 319.005 ;
     RECT  2.16 319.275 246.24 319.545 ;
     RECT  2.16 319.815 246.24 320.085 ;
     RECT  2.16 320.355 246.24 320.625 ;
     RECT  2.16 320.895 246.24 321.165 ;
     RECT  2.16 321.435 246.24 321.705 ;
     RECT  2.16 321.975 246.24 322.245 ;
     RECT  2.16 322.515 246.24 322.785 ;
     RECT  2.16 323.055 246.24 323.325 ;
     RECT  2.16 323.595 246.24 323.865 ;
     RECT  2.16 324.135 246.24 324.405 ;
     RECT  2.16 324.675 246.24 324.945 ;
     RECT  2.16 325.215 246.24 325.485 ;
     RECT  2.16 325.755 246.24 326.025 ;
     RECT  2.16 326.295 246.24 326.565 ;
     RECT  2.16 326.835 246.24 327.105 ;
     RECT  2.16 327.375 246.24 327.645 ;
     RECT  2.16 327.915 246.24 328.185 ;
     RECT  2.16 328.455 246.24 328.725 ;
     RECT  2.16 328.995 246.24 329.265 ;
     RECT  2.16 329.535 246.24 329.805 ;
     RECT  2.16 330.075 246.24 330.345 ;
     RECT  2.16 330.615 246.24 330.885 ;
     RECT  2.16 331.155 246.24 331.425 ;
     RECT  2.16 331.695 246.24 331.965 ;
     RECT  2.16 332.235 246.24 332.505 ;
     RECT  2.16 332.775 246.24 333.045 ;
     RECT  2.16 333.315 246.24 333.585 ;
     RECT  2.16 333.855 246.24 334.125 ;
     RECT  2.16 334.395 246.24 334.665 ;
     RECT  2.16 334.935 246.24 335.205 ;
     RECT  2.16 335.475 246.24 335.745 ;
     RECT  2.16 336.015 246.24 336.285 ;
     RECT  2.16 336.555 246.24 336.825 ;
     RECT  2.16 337.095 246.24 337.365 ;
     RECT  2.16 337.635 246.24 337.905 ;
     RECT  2.16 338.175 246.24 338.445 ;
     RECT  2.16 338.715 246.24 338.985 ;
     RECT  2.16 339.255 246.24 339.525 ;
     RECT  2.16 339.795 246.24 340.065 ;
     RECT  2.16 340.335 246.24 340.605 ;
     RECT  2.16 340.875 246.24 341.145 ;
     RECT  2.16 341.415 246.24 341.685 ;
     RECT  2.16 341.955 246.24 342.225 ;
     RECT  2.16 342.495 246.24 342.765 ;
     RECT  2.16 343.035 246.24 343.305 ;
     RECT  2.16 343.575 246.24 343.845 ;
     RECT  2.16 344.115 246.24 344.385 ;
     RECT  2.16 344.655 246.24 344.925 ;
     RECT  2.16 345.195 246.24 345.465 ;
     RECT  2.16 345.735 246.24 346.005 ;
     RECT  2.16 346.275 246.24 346.545 ;
     RECT  2.16 346.815 246.24 347.085 ;
     RECT  2.16 347.355 246.24 347.625 ;
     RECT  2.16 347.895 246.24 348.165 ;
     RECT  2.16 348.435 246.24 348.705 ;
     RECT  2.16 348.975 246.24 349.245 ;
     RECT  2.16 349.515 246.24 349.785 ;
     RECT  2.16 350.055 246.24 350.325 ;
     RECT  2.16 350.595 246.24 350.865 ;
     RECT  2.16 351.135 246.24 351.405 ;
     RECT  2.16 351.675 246.24 351.945 ;
     RECT  2.16 352.215 246.24 352.485 ;
     RECT  2.16 352.755 246.24 353.025 ;
     RECT  2.16 353.295 246.24 353.565 ;
     RECT  2.16 353.835 246.24 354.105 ;
     RECT  2.16 354.375 246.24 354.645 ;
     RECT  2.16 354.915 246.24 355.185 ;
     RECT  2.16 355.455 246.24 355.725 ;
     RECT  2.16 355.995 246.24 356.265 ;
     RECT  2.16 356.535 246.24 356.805 ;
     RECT  2.16 357.075 246.24 357.345 ;
     RECT  2.16 357.615 246.24 357.885 ;
     RECT  2.16 358.155 246.24 358.425 ;
     RECT  2.16 358.695 246.24 358.965 ;
     RECT  2.16 359.235 246.24 359.505 ;
     RECT  2.16 359.775 246.24 360.045 ;
     RECT  2.16 360.315 246.24 360.585 ;
     RECT  2.16 360.855 246.24 361.125 ;
     RECT  2.16 361.395 246.24 361.665 ;
     RECT  2.16 361.935 246.24 362.205 ;
     RECT  2.16 362.475 246.24 362.745 ;
     RECT  2.16 363.015 246.24 363.285 ;
     RECT  2.16 363.555 246.24 363.825 ;
     RECT  2.16 364.095 246.24 364.365 ;
     RECT  2.16 364.635 246.24 364.905 ;
     RECT  2.16 365.175 246.24 365.445 ;
     RECT  2.16 365.715 246.24 365.985 ;
     RECT  2.16 366.255 246.24 366.525 ;
     RECT  2.16 366.795 246.24 367.065 ;
     RECT  2.16 367.335 246.24 367.605 ;
     RECT  2.16 367.875 246.24 368.145 ;
     RECT  2.16 368.415 246.24 368.685 ;
     RECT  2.16 368.955 246.24 369.225 ;
    LAYER M1 ;
     RECT  2.16 2.151 246.24 369.369 ;
    LAYER M2 ;
     RECT  0.067 170.82 0.103 170.838 ;
     RECT  0.031 174.492 0.131 174.51 ;
     RECT  0.067 177.876 0.167 177.894 ;
     RECT  0.103 170.442 0.203 170.838 ;
     RECT  0.139 176.112 0.499 176.13 ;
     RECT  0.499 175.95 0.535 176.13 ;
     RECT  0.499 204.534 0.535 204.552 ;
     RECT  0.535 177.192 0.635 177.354 ;
     RECT  0.031 165.69 2.16 165.708 ;
     RECT  0.103 166.968 2.16 166.986 ;
     RECT  0.203 170.82 2.16 170.838 ;
     RECT  0.535 175.41 2.16 176.13 ;
     RECT  0.635 177.192 2.16 177.21 ;
     RECT  0.139 182.592 2.16 182.61 ;
     RECT  0.067 183.942 2.16 183.96 ;
     RECT  0.103 185.832 2.16 185.85 ;
     RECT  0.031 187.452 2.16 187.47 ;
     RECT  0.535 204.534 2.16 204.624 ;
     RECT  2.16 2.151 246.24 369.369 ;
     RECT  246.24 185.436 246.263 189.594 ;
     RECT  246.24 178.38 246.515 178.398 ;
     RECT  246.24 191.196 246.551 191.214 ;
     RECT  246.263 185.634 246.767 189.594 ;
     RECT  246.767 185.634 246.803 188.784 ;
     RECT  246.803 185.634 246.839 185.724 ;
     RECT  246.803 186.876 246.839 188.586 ;
     RECT  246.24 183.276 247.091 183.294 ;
     RECT  246.839 186.876 247.379 187.776 ;
     RECT  246.767 189.576 247.379 189.594 ;
     RECT  246.24 161.766 247.415 162.36 ;
     RECT  246.839 185.706 247.415 185.724 ;
     RECT  247.379 187.416 247.415 187.776 ;
     RECT  247.415 162.306 247.487 162.324 ;
     RECT  247.415 187.416 247.487 187.434 ;
     RECT  248.215 186.291 248.315 186.309 ;
    LAYER M3 ;
     RECT  2.415 2.143 2.505 2.413 ;
     RECT  7.815 2.143 7.905 2.413 ;
     RECT  13.215 2.143 13.305 2.413 ;
     RECT  18.615 2.143 18.705 2.413 ;
     RECT  24.015 2.143 24.105 2.413 ;
     RECT  29.415 2.143 29.505 2.413 ;
     RECT  34.815 2.143 34.905 2.413 ;
     RECT  40.215 2.143 40.305 2.413 ;
     RECT  45.615 2.143 45.705 2.413 ;
     RECT  51.015 2.143 51.105 2.413 ;
     RECT  56.415 2.143 56.505 2.413 ;
     RECT  61.815 2.143 61.905 2.413 ;
     RECT  67.215 2.143 67.305 2.413 ;
     RECT  72.615 2.143 72.705 2.413 ;
     RECT  78.015 2.143 78.105 2.413 ;
     RECT  83.415 2.143 83.505 2.413 ;
     RECT  88.815 2.143 88.905 2.413 ;
     RECT  94.215 2.143 94.305 2.413 ;
     RECT  99.615 2.143 99.705 2.413 ;
     RECT  105.015 2.143 105.105 2.413 ;
     RECT  110.415 2.143 110.505 2.413 ;
     RECT  115.815 2.143 115.905 2.413 ;
     RECT  121.215 2.143 121.305 2.413 ;
     RECT  126.615 2.143 126.705 2.413 ;
     RECT  132.015 2.143 132.105 2.413 ;
     RECT  137.415 2.143 137.505 2.413 ;
     RECT  142.815 2.143 142.905 2.413 ;
     RECT  148.215 2.143 148.305 2.413 ;
     RECT  153.615 2.143 153.705 2.413 ;
     RECT  159.015 2.143 159.105 2.413 ;
     RECT  164.415 2.143 164.505 2.413 ;
     RECT  169.815 2.143 169.905 2.413 ;
     RECT  175.215 2.143 175.305 2.413 ;
     RECT  180.615 2.143 180.705 2.413 ;
     RECT  186.015 2.143 186.105 2.413 ;
     RECT  191.415 2.143 191.505 2.413 ;
     RECT  196.815 2.143 196.905 2.413 ;
     RECT  202.215 2.143 202.305 2.413 ;
     RECT  207.615 2.143 207.705 2.413 ;
     RECT  213.015 2.143 213.105 2.413 ;
     RECT  218.415 2.143 218.505 2.413 ;
     RECT  223.815 2.143 223.905 2.413 ;
     RECT  229.215 2.143 229.305 2.413 ;
     RECT  234.615 2.143 234.705 2.413 ;
     RECT  240.015 2.143 240.105 2.413 ;
     RECT  245.415 2.143 245.505 2.413 ;
     RECT  145.908 132.331 145.926 132.439 ;
     RECT  145.728 132.439 145.926 132.475 ;
     RECT  145.692 132.475 145.926 132.511 ;
     RECT  142.815 2.413 143.097 132.637 ;
     RECT  142.74 132.637 143.097 132.673 ;
     RECT  144.828 132.511 145.926 132.701 ;
     RECT  142.74 132.673 143.622 132.781 ;
     RECT  141.912 132.907 141.93 132.979 ;
     RECT  141.336 132.979 141.93 133.003 ;
     RECT  142.74 132.781 143.982 133.015 ;
     RECT  140.868 133.003 141.93 133.051 ;
     RECT  142.704 133.015 143.982 133.051 ;
     RECT  144.828 132.701 145.746 133.051 ;
     RECT  140.868 133.051 143.982 133.321 ;
     RECT  140.868 133.321 144.054 133.411 ;
     RECT  140.436 133.411 144.054 133.519 ;
     RECT  144.792 133.051 145.746 133.519 ;
     RECT  140.436 133.519 145.746 133.591 ;
     RECT  140.436 133.591 146.106 134.365 ;
     RECT  140.4 134.365 146.106 134.401 ;
     RECT  140.328 134.401 146.106 134.563 ;
     RECT  140.328 134.563 146.322 134.905 ;
     RECT  140.112 134.905 146.322 135.059 ;
     RECT  138.564 135.211 138.582 135.373 ;
     RECT  139.392 135.211 139.518 135.373 ;
     RECT  137.415 2.413 137.697 135.949 ;
     RECT  138.564 135.373 139.518 135.949 ;
     RECT  140.256 135.059 146.322 136.139 ;
     RECT  137.415 135.949 139.518 136.255 ;
     RECT  140.256 136.139 145.89 136.255 ;
     RECT  137.415 136.255 145.89 136.283 ;
     RECT  137.415 136.283 145.458 137.101 ;
     RECT  137.415 137.101 145.782 137.219 ;
     RECT  144.324 137.219 145.782 137.327 ;
     RECT  144.468 137.327 145.782 137.641 ;
     RECT  144.468 137.641 145.89 137.759 ;
     RECT  137.415 137.219 143.586 138.109 ;
     RECT  144.468 137.759 145.278 138.109 ;
     RECT  146.736 138.343 146.898 138.415 ;
     RECT  146.736 138.415 146.934 138.541 ;
     RECT  146.592 138.541 146.934 138.577 ;
     RECT  146.268 138.577 146.934 138.649 ;
     RECT  137.415 138.109 145.278 138.685 ;
     RECT  137.415 138.685 145.35 138.721 ;
     RECT  146.268 138.649 147.042 138.721 ;
     RECT  137.415 138.721 147.042 138.811 ;
     RECT  137.415 138.811 147.15 138.955 ;
     RECT  137.412 138.955 147.15 138.991 ;
     RECT  148.215 2.413 148.497 138.991 ;
     RECT  137.412 138.991 148.497 139.289 ;
     RECT  148.176 139.289 148.497 139.523 ;
     RECT  136.404 139.729 136.602 139.765 ;
     RECT  136.26 139.765 136.602 139.801 ;
     RECT  137.412 139.289 147.15 139.801 ;
     RECT  136.26 139.801 147.15 139.927 ;
     RECT  135.612 139.927 147.15 139.999 ;
     RECT  135.432 139.999 147.15 140.071 ;
     RECT  135.396 140.071 147.33 140.189 ;
     RECT  133.704 140.161 134.118 140.197 ;
     RECT  135.396 140.189 147.114 140.297 ;
     RECT  133.704 140.197 134.586 140.575 ;
     RECT  135.396 140.297 147.042 140.603 ;
     RECT  133.416 140.575 134.586 140.611 ;
     RECT  135.396 140.603 139.626 140.611 ;
     RECT  140.364 140.603 147.042 140.639 ;
     RECT  133.416 140.611 139.626 140.731 ;
     RECT  148.215 139.523 148.497 141.313 ;
     RECT  133.02 140.731 139.626 141.347 ;
     RECT  133.452 141.347 139.626 141.385 ;
     RECT  140.364 140.639 146.97 141.385 ;
     RECT  133.452 141.385 146.97 141.511 ;
     RECT  147.924 141.313 148.497 141.511 ;
     RECT  133.452 141.511 148.497 142.079 ;
     RECT  149.868 141.961 149.886 142.159 ;
     RECT  133.488 142.079 148.497 142.195 ;
     RECT  149.544 142.159 149.886 142.195 ;
     RECT  133.488 142.195 148.554 142.231 ;
     RECT  149.436 142.195 149.886 142.231 ;
     RECT  133.488 142.231 149.886 142.355 ;
     RECT  133.884 142.355 149.886 142.771 ;
     RECT  133.884 142.771 150.354 142.889 ;
     RECT  133.884 142.889 149.814 142.925 ;
     RECT  133.884 142.925 149.562 142.961 ;
     RECT  133.884 142.961 149.382 143.069 ;
     RECT  133.884 143.069 148.59 143.131 ;
     RECT  132.015 2.413 132.297 143.269 ;
     RECT  133.164 143.131 148.59 143.269 ;
     RECT  132.015 143.269 148.59 143.851 ;
     RECT  149.364 143.069 149.382 143.851 ;
     RECT  132.015 143.851 149.922 143.977 ;
     RECT  130.86 144.049 130.878 144.121 ;
     RECT  131.688 143.977 149.922 144.121 ;
     RECT  130.86 144.121 149.922 144.125 ;
     RECT  131.112 144.125 149.922 144.391 ;
     RECT  131.112 144.391 150.426 144.851 ;
     RECT  131.112 144.851 149.958 145.049 ;
     RECT  131.112 145.049 149.922 145.193 ;
     RECT  131.112 145.193 149.886 145.229 ;
     RECT  131.112 145.229 149.85 145.531 ;
     RECT  130.896 145.531 149.85 145.589 ;
     RECT  131.112 145.589 149.85 145.975 ;
     RECT  131.112 145.975 149.922 146.479 ;
     RECT  131.112 146.479 150.426 146.635 ;
     RECT  130.68 146.635 150.426 146.675 ;
     RECT  130.752 146.675 150.426 146.849 ;
     RECT  151.164 147.019 151.182 147.217 ;
     RECT  133.74 146.849 150.426 147.361 ;
     RECT  151.164 147.217 151.47 147.361 ;
     RECT  133.74 147.361 151.506 147.631 ;
     RECT  133.74 147.631 151.542 147.829 ;
     RECT  133.668 147.829 151.542 147.857 ;
     RECT  130.752 146.849 132.894 147.865 ;
     RECT  133.668 147.857 151.506 147.865 ;
     RECT  130.752 147.865 151.506 148.091 ;
     RECT  130.752 148.091 151.326 148.171 ;
     RECT  130.5 148.171 151.326 149.143 ;
     RECT  130.5 149.143 151.398 149.251 ;
     RECT  130.5 149.251 151.434 149.485 ;
     RECT  152.388 149.449 152.406 149.485 ;
     RECT  130.5 149.485 152.406 149.755 ;
     RECT  129.96 149.755 152.406 149.917 ;
     RECT  129.42 149.917 152.406 150.331 ;
     RECT  129.42 150.331 152.766 150.457 ;
     RECT  129.276 150.457 152.766 150.799 ;
     RECT  153.615 2.413 153.897 150.799 ;
     RECT  129.276 150.799 153.897 150.835 ;
     RECT  129.24 150.835 153.897 150.871 ;
     RECT  129.24 150.871 154.134 150.893 ;
     RECT  129.42 150.893 154.134 151.061 ;
     RECT  129.42 151.061 153.897 151.951 ;
     RECT  129.42 151.951 154.242 151.979 ;
     RECT  129.456 151.979 154.242 152.177 ;
     RECT  129.456 152.177 152.478 152.249 ;
     RECT  129.78 152.249 152.478 152.717 ;
     RECT  153.288 152.177 154.242 152.761 ;
     RECT  131.976 152.717 152.478 152.789 ;
     RECT  153.288 152.761 154.458 152.887 ;
     RECT  132.015 152.789 152.478 152.971 ;
     RECT  153.288 152.887 154.674 152.971 ;
     RECT  132.015 152.971 154.674 153.031 ;
     RECT  132.015 153.031 155.106 153.185 ;
     RECT  129.78 152.717 131.202 153.265 ;
     RECT  129.636 153.265 131.202 153.535 ;
     RECT  132.015 153.185 154.782 153.535 ;
     RECT  128.772 153.355 128.79 153.563 ;
     RECT  129.636 153.535 154.782 153.563 ;
     RECT  155.628 153.301 155.646 153.563 ;
     RECT  128.916 153.571 128.934 153.689 ;
     RECT  129.816 153.563 154.782 154.103 ;
     RECT  149.904 154.103 154.782 154.337 ;
     RECT  149.904 154.337 154.458 154.373 ;
     RECT  129.816 154.103 149.166 154.651 ;
     RECT  129.312 154.651 149.166 154.849 ;
     RECT  129.132 154.849 149.166 154.921 ;
     RECT  149.904 154.373 154.134 154.921 ;
     RECT  129.132 154.921 154.134 155.021 ;
     RECT  129.42 155.021 154.134 155.155 ;
     RECT  129.42 155.155 154.458 155.183 ;
     RECT  129.96 155.183 154.458 155.371 ;
     RECT  129.96 155.371 154.998 155.597 ;
     RECT  129.96 155.597 154.35 156.397 ;
     RECT  129.564 156.397 154.35 156.433 ;
     RECT  129.312 156.433 154.35 156.469 ;
     RECT  125.748 156.505 125.766 156.541 ;
     RECT  126.615 2.413 126.897 156.541 ;
     RECT  128.7 156.469 154.35 156.541 ;
     RECT  125.748 156.541 126.897 156.703 ;
     RECT  121.215 2.413 121.497 156.739 ;
     RECT  121.215 156.739 121.806 156.811 ;
     RECT  123.552 156.703 123.57 156.901 ;
     RECT  128.7 156.541 154.674 156.937 ;
     RECT  122.904 156.901 123.57 157.045 ;
     RECT  125.136 156.703 126.897 157.045 ;
     RECT  120.852 156.811 121.806 157.081 ;
     RECT  122.904 157.045 126.897 157.081 ;
     RECT  128.7 156.937 154.962 157.081 ;
     RECT  120.852 157.081 126.897 157.469 ;
     RECT  128.7 157.081 155.286 157.855 ;
     RECT  120.852 157.469 125.766 158.431 ;
     RECT  126.54 157.469 126.897 158.431 ;
     RECT  128.7 157.855 155.322 158.431 ;
     RECT  128.7 158.431 156.114 158.549 ;
     RECT  120.852 158.431 126.897 158.557 ;
     RECT  128.7 158.549 155.358 158.585 ;
     RECT  156.096 158.549 156.114 158.593 ;
     RECT  156.096 158.593 156.15 158.594 ;
     RECT  156.132 158.594 156.15 158.701 ;
     RECT  156.132 158.701 156.618 158.819 ;
     RECT  128.7 158.585 155.322 158.935 ;
     RECT  128.484 158.935 155.322 159.133 ;
     RECT  119.808 159.205 119.826 159.331 ;
     RECT  120.852 158.557 126.99 159.331 ;
     RECT  128.016 159.133 155.322 159.629 ;
     RECT  129.708 159.629 155.322 159.637 ;
     RECT  156.132 158.819 156.15 159.637 ;
     RECT  119.808 159.331 126.99 159.673 ;
     RECT  128.016 159.629 128.934 159.673 ;
     RECT  129.708 159.637 156.15 159.781 ;
     RECT  129.708 159.781 156.51 160.007 ;
     RECT  119.808 159.673 128.934 160.169 ;
     RECT  120.852 160.169 128.934 160.717 ;
     RECT  129.708 160.007 156.222 160.717 ;
     RECT  245.415 2.413 245.697 160.717 ;
     RECT  120.852 160.717 156.222 160.789 ;
     RECT  245.415 160.717 246.222 160.861 ;
     RECT  120.852 160.789 156.654 160.889 ;
     RECT  120.852 160.889 156.582 160.979 ;
     RECT  119.808 160.169 119.826 161.131 ;
     RECT  120.852 160.979 156.222 161.131 ;
     RECT  119.808 161.131 156.222 161.249 ;
     RECT  245.196 160.861 246.222 161.249 ;
     RECT  244.26 160.321 244.278 161.365 ;
     RECT  119.808 161.249 129.906 161.393 ;
     RECT  244.008 161.365 244.278 161.401 ;
     RECT  119.808 161.393 127.026 161.519 ;
     RECT  244.008 161.401 244.35 161.671 ;
     RECT  242.244 161.599 242.262 161.699 ;
     RECT  244.008 161.671 244.422 161.789 ;
     RECT  119.808 161.519 125.55 161.803 ;
     RECT  245.304 161.249 246.222 161.833 ;
     RECT  247.392 161.761 247.41 161.833 ;
     RECT  119.664 161.803 125.55 161.861 ;
     RECT  130.644 161.249 156.222 162.139 ;
     RECT  127.908 161.393 129.906 162.175 ;
     RECT  130.644 162.139 156.762 162.175 ;
     RECT  126.576 161.519 127.026 162.211 ;
     RECT  127.908 162.175 156.762 162.211 ;
     RECT  126.576 162.211 156.762 162.221 ;
     RECT  130.896 162.221 156.762 162.239 ;
     RECT  126.576 162.221 130.122 162.269 ;
     RECT  166.392 162.187 166.41 162.301 ;
     RECT  245.304 161.833 247.41 162.301 ;
     RECT  245.304 162.301 247.482 162.317 ;
     RECT  245.304 162.317 245.934 162.328 ;
     RECT  119.664 161.861 123.678 162.329 ;
     RECT  130.896 162.239 156.69 162.329 ;
     RECT  166.392 162.301 166.986 162.329 ;
     RECT  156.132 162.329 156.222 162.365 ;
     RECT  166.968 162.329 166.986 162.365 ;
     RECT  245.124 162.328 245.934 162.365 ;
     RECT  156.204 162.365 156.222 162.401 ;
     RECT  124.452 161.861 125.55 162.409 ;
     RECT  246.816 162.317 247.482 162.413 ;
     RECT  130.896 162.329 155.394 162.461 ;
     RECT  126.576 162.269 127.026 162.481 ;
     RECT  245.415 162.365 245.934 162.509 ;
     RECT  247.392 162.413 247.482 162.605 ;
     RECT  127.836 162.269 130.122 162.635 ;
     RECT  119.808 162.329 123.678 162.643 ;
     RECT  124.452 162.409 125.658 162.643 ;
     RECT  247.464 162.605 247.482 162.701 ;
     RECT  127.908 162.635 130.122 162.707 ;
     RECT  119.808 162.643 125.658 162.751 ;
     RECT  126.468 162.481 127.026 162.751 ;
     RECT  119.808 162.751 127.026 162.779 ;
     RECT  128.052 162.707 130.122 162.869 ;
     RECT  128.052 162.869 128.07 162.905 ;
     RECT  130.896 162.461 154.962 162.949 ;
     RECT  128.88 162.869 130.122 163.003 ;
     RECT  130.86 162.949 154.962 163.003 ;
     RECT  120.024 162.779 127.026 163.139 ;
     RECT  128.88 163.003 154.962 163.453 ;
     RECT  128.88 163.453 155.214 163.525 ;
     RECT  128.88 163.525 155.358 163.651 ;
     RECT  156.24 163.291 156.258 163.651 ;
     RECT  128.88 163.651 156.258 163.675 ;
     RECT  128.88 163.675 156.906 163.687 ;
     RECT  128.88 163.687 157.554 163.795 ;
     RECT  128.88 163.795 157.806 163.831 ;
     RECT  128.628 163.831 157.95 163.901 ;
     RECT  128.772 163.901 157.95 163.993 ;
     RECT  128.772 163.993 158.094 164.129 ;
     RECT  120.024 163.139 126.897 164.371 ;
     RECT  159.015 2.413 159.297 164.605 ;
     RECT  119.664 164.371 126.897 164.717 ;
     RECT  159.015 164.605 159.93 164.731 ;
     RECT  159.015 164.731 160.218 164.911 ;
     RECT  159.012 164.911 160.218 165.073 ;
     RECT  129.06 164.129 158.094 165.145 ;
     RECT  128.88 165.145 158.094 165.259 ;
     RECT  128.7 165.259 158.094 165.307 ;
     RECT  119.88 164.717 126.897 165.451 ;
     RECT  128.232 165.307 158.094 165.451 ;
     RECT  159.012 165.073 160.254 165.451 ;
     RECT  128.232 165.451 160.254 165.541 ;
     RECT  119.664 165.451 126.897 165.677 ;
     RECT  115.815 2.413 116.097 165.691 ;
     RECT  117.792 165.685 117.81 165.721 ;
     RECT  2.415 2.413 2.697 165.811 ;
     RECT  117.18 165.721 117.81 165.839 ;
     RECT  128.232 165.541 160.578 165.839 ;
     RECT  128.988 165.839 160.578 165.847 ;
     RECT  115.815 165.691 116.262 165.875 ;
     RECT  128.232 165.839 128.25 165.947 ;
     RECT  128.988 165.847 161.298 165.947 ;
     RECT  129.024 165.947 161.298 165.955 ;
     RECT  129.024 165.955 161.874 166.109 ;
     RECT  129.024 166.109 161.298 166.145 ;
     RECT  129.024 166.145 161.19 166.181 ;
     RECT  119.664 165.677 125.046 166.225 ;
     RECT  119.484 166.225 125.046 166.411 ;
     RECT  118.836 166.411 125.046 166.445 ;
     RECT  120.024 166.445 125.046 166.621 ;
     RECT  125.784 165.677 126.897 166.621 ;
     RECT  162.18 166.801 162.198 166.919 ;
     RECT  0.036 165.685 0.054 166.963 ;
     RECT  129.852 166.181 161.19 166.999 ;
     RECT  118.836 166.445 118.89 167.069 ;
     RECT  129.852 166.999 161.766 167.071 ;
     RECT  117.792 165.839 117.81 167.189 ;
     RECT  118.872 167.069 118.89 167.189 ;
     RECT  4.932 166.081 4.95 167.269 ;
     RECT  129.024 166.181 129.042 167.305 ;
     RECT  129.78 167.071 161.766 167.305 ;
     RECT  120.024 166.621 126.897 167.333 ;
     RECT  129.024 167.305 161.766 167.341 ;
     RECT  128.772 167.341 161.766 167.539 ;
     RECT  120.024 167.333 125.37 167.611 ;
     RECT  119.952 167.611 125.37 167.773 ;
     RECT  128.592 167.539 161.766 167.881 ;
     RECT  118.692 167.947 118.71 167.971 ;
     RECT  128.592 167.881 161.982 167.999 ;
     RECT  2.415 165.811 3.078 168.007 ;
     RECT  119.556 167.773 125.37 168.151 ;
     RECT  126.108 167.333 126.897 168.151 ;
     RECT  128.592 167.999 161.55 168.277 ;
     RECT  119.556 168.151 126.897 168.421 ;
     RECT  118.584 167.971 118.71 168.667 ;
     RECT  119.52 168.421 126.897 168.667 ;
     RECT  118.584 168.667 126.897 168.719 ;
     RECT  128.268 168.277 161.55 168.781 ;
     RECT  127.872 168.781 161.55 168.853 ;
     RECT  4.5 167.269 4.95 168.889 ;
     RECT  118.584 168.719 118.602 168.889 ;
     RECT  114.588 168.889 114.606 168.989 ;
     RECT  118.512 168.889 118.602 168.989 ;
     RECT  127.872 168.853 162.018 169.195 ;
     RECT  118.584 168.989 118.602 169.277 ;
     RECT  127.872 169.195 162.09 169.277 ;
     RECT  119.376 168.719 126.897 170.041 ;
     RECT  128.34 169.277 162.09 170.159 ;
     RECT  128.34 170.159 128.934 170.275 ;
     RECT  119.052 170.041 126.897 170.333 ;
     RECT  129.744 170.159 161.694 170.429 ;
     RECT  0.036 166.963 0.126 170.437 ;
     RECT  129.744 170.429 161.082 170.969 ;
     RECT  128.232 170.275 128.934 170.977 ;
     RECT  129.744 170.969 132.297 170.977 ;
     RECT  119.304 170.333 126.897 171.121 ;
     RECT  133.056 170.969 161.082 171.149 ;
     RECT  158.436 171.149 161.082 171.347 ;
     RECT  128.232 170.977 132.297 171.787 ;
     RECT  133.056 171.149 157.482 171.787 ;
     RECT  158.616 171.347 161.082 171.931 ;
     RECT  119.196 171.121 126.897 172.021 ;
     RECT  128.232 171.787 157.482 172.021 ;
     RECT  128.232 172.021 157.77 172.123 ;
     RECT  158.616 171.931 161.586 172.327 ;
     RECT  127.656 172.123 157.77 172.399 ;
     RECT  158.58 172.327 161.586 172.399 ;
     RECT  119.124 172.021 126.897 172.471 ;
     RECT  127.656 172.399 161.586 172.589 ;
     RECT  127.836 172.589 161.586 172.625 ;
     RECT  128.592 172.625 161.586 172.661 ;
     RECT  128.772 172.661 161.586 172.895 ;
     RECT  117.648 171.481 117.666 173.227 ;
     RECT  118.764 172.471 126.897 173.227 ;
     RECT  2.415 168.007 3.186 173.407 ;
     RECT  115.815 165.875 116.097 173.551 ;
     RECT  127.836 172.625 127.854 173.551 ;
     RECT  127.836 173.551 127.962 173.579 ;
     RECT  117.648 173.227 126.897 173.785 ;
     RECT  128.772 172.895 159.822 173.813 ;
     RECT  117.468 173.785 126.897 173.939 ;
     RECT  128.772 173.813 156.186 173.939 ;
     RECT  117.54 173.939 126.897 173.981 ;
     RECT  115.815 173.551 116.478 174.091 ;
     RECT  160.56 172.895 161.586 174.091 ;
     RECT  115.815 174.091 116.622 174.209 ;
     RECT  115.815 174.209 116.478 174.413 ;
     RECT  0.036 170.437 0.198 174.515 ;
     RECT  127.944 173.579 127.962 174.595 ;
     RECT  128.772 173.939 156.15 174.595 ;
     RECT  117.648 173.981 126.897 174.631 ;
     RECT  127.944 174.595 156.15 174.631 ;
     RECT  117.648 174.631 156.15 174.749 ;
     RECT  121.215 174.749 156.15 174.793 ;
     RECT  156.924 173.813 159.822 174.793 ;
     RECT  2.415 173.407 3.33 174.829 ;
     RECT  4.068 168.889 4.95 174.829 ;
     RECT  115.815 174.413 116.097 174.901 ;
     RECT  121.215 174.793 159.822 174.989 ;
     RECT  129.024 174.989 159.822 175.289 ;
     RECT  129.024 175.289 130.194 175.325 ;
     RECT  0.072 174.515 0.198 175.405 ;
     RECT  117.648 174.749 120.294 175.531 ;
     RECT  121.215 174.989 128.106 175.531 ;
     RECT  0.072 175.405 0.558 175.661 ;
     RECT  115.668 174.901 116.097 175.675 ;
     RECT  116.82 175.171 116.838 175.675 ;
     RECT  115.668 175.675 116.838 175.711 ;
     RECT  117.648 175.531 128.106 175.711 ;
     RECT  129.024 175.325 130.086 175.711 ;
     RECT  2.415 174.829 4.95 175.819 ;
     RECT  2.415 175.819 5.49 175.981 ;
     RECT  115.236 175.711 116.838 175.981 ;
     RECT  117.648 175.711 130.086 175.981 ;
     RECT  115.236 175.981 130.086 176.059 ;
     RECT  114.3 175.945 114.318 176.093 ;
     RECT  115.164 176.059 130.086 176.099 ;
     RECT  117.504 176.099 130.086 176.107 ;
     RECT  115.164 176.099 116.766 176.135 ;
     RECT  2.415 175.981 5.706 176.141 ;
     RECT  5.688 176.141 5.706 176.171 ;
     RECT  0.108 175.661 0.558 176.203 ;
     RECT  117.504 176.107 130.41 176.251 ;
     RECT  131.328 175.289 159.822 176.251 ;
     RECT  160.56 174.091 161.802 176.251 ;
     RECT  0.108 176.203 0.63 176.333 ;
     RECT  2.415 176.141 4.95 176.491 ;
     RECT  117.504 176.251 161.802 176.717 ;
     RECT  0.108 176.333 0.234 176.909 ;
     RECT  2.304 176.491 4.95 176.981 ;
     RECT  0.18 176.909 0.234 177.005 ;
     RECT  3.996 176.981 4.95 177.053 ;
     RECT  2.304 176.981 3.15 177.163 ;
     RECT  4.284 177.053 4.95 177.179 ;
     RECT  115.272 176.135 116.766 177.179 ;
     RECT  115.596 177.179 116.766 177.223 ;
     RECT  117.504 176.717 155.322 177.223 ;
     RECT  2.268 177.163 3.15 177.251 ;
     RECT  115.596 177.223 155.322 177.265 ;
     RECT  0.54 177.187 0.558 177.307 ;
     RECT  4.284 177.179 4.554 177.341 ;
     RECT  0.54 177.307 0.63 177.359 ;
     RECT  0.54 177.359 0.558 177.389 ;
     RECT  115.815 177.265 155.322 177.457 ;
     RECT  156.348 176.717 161.802 177.457 ;
     RECT  4.284 177.341 4.302 177.485 ;
     RECT  2.304 177.251 3.15 177.739 ;
     RECT  0.144 177.835 0.162 177.871 ;
     RECT  245.415 162.509 245.697 177.871 ;
     RECT  115.815 177.457 161.802 177.899 ;
     RECT  245.196 177.871 245.697 177.989 ;
     RECT  2.304 177.739 3.33 178.141 ;
     RECT  0.072 177.871 0.162 178.219 ;
     RECT  115.815 177.899 161.586 178.259 ;
     RECT  245.268 177.989 245.697 178.295 ;
     RECT  0.072 178.219 0.342 178.349 ;
     RECT  2.304 178.141 3.546 178.375 ;
     RECT  2.304 178.375 3.654 178.637 ;
     RECT  2.415 178.637 3.654 178.681 ;
     RECT  0.072 178.349 0.198 178.939 ;
     RECT  2.415 178.681 4.086 178.951 ;
     RECT  0.036 178.939 0.198 178.973 ;
     RECT  117.468 178.259 161.586 179.069 ;
     RECT  117.504 179.069 161.586 179.717 ;
     RECT  124.56 179.717 161.586 180.329 ;
     RECT  243.684 180.301 243.702 180.419 ;
     RECT  117.504 179.717 123.714 180.571 ;
     RECT  124.668 180.329 161.586 180.689 ;
     RECT  244.044 180.571 244.062 180.725 ;
     RECT  156.024 180.689 161.586 180.869 ;
     RECT  2.415 178.951 4.194 180.995 ;
     RECT  156.6 180.869 161.586 181.031 ;
     RECT  156.744 181.031 161.586 181.103 ;
     RECT  117.504 180.571 123.786 181.111 ;
     RECT  124.668 180.689 155.25 181.111 ;
     RECT  156.996 181.103 161.586 181.229 ;
     RECT  164.415 2.413 164.697 181.471 ;
     RECT  169.815 2.413 170.097 181.471 ;
     RECT  117.504 181.111 155.25 181.483 ;
     RECT  164.304 181.471 164.697 181.517 ;
     RECT  169.704 181.471 170.097 181.517 ;
     RECT  169.815 181.517 170.097 181.651 ;
     RECT  169.815 181.651 170.73 181.805 ;
     RECT  117.396 181.483 155.25 181.877 ;
     RECT  117.612 181.877 155.25 181.885 ;
     RECT  157.608 181.229 161.586 182.011 ;
     RECT  157.32 182.011 161.586 182.083 ;
     RECT  157.176 182.083 161.586 182.155 ;
     RECT  156.672 182.155 161.586 182.191 ;
     RECT  117.612 181.885 155.61 182.309 ;
     RECT  117.684 182.309 155.61 182.425 ;
     RECT  156.456 182.191 161.586 182.425 ;
     RECT  113.904 180.967 113.922 182.551 ;
     RECT  0.036 178.973 0.162 182.615 ;
     RECT  244.26 180.841 244.278 182.731 ;
     RECT  113.904 182.551 114.642 182.849 ;
     RECT  113.904 182.849 114.498 182.861 ;
     RECT  244.26 182.731 244.566 183.155 ;
     RECT  246.492 178.375 246.51 183.271 ;
     RECT  117.684 182.425 161.586 183.433 ;
     RECT  117.684 183.433 161.874 183.499 ;
     RECT  117.36 183.499 161.874 183.505 ;
     RECT  245.415 178.295 245.697 183.811 ;
     RECT  115.815 178.259 116.097 183.901 ;
     RECT  245.052 183.811 245.697 183.965 ;
     RECT  245.415 183.965 245.697 184.081 ;
     RECT  246.492 183.271 247.086 184.081 ;
     RECT  115.164 183.901 116.097 184.199 ;
     RECT  117.288 183.505 161.874 184.351 ;
     RECT  163.62 184.585 163.638 184.843 ;
     RECT  164.415 181.517 164.697 184.843 ;
     RECT  117.252 184.351 161.874 184.855 ;
     RECT  244.26 183.155 244.278 184.891 ;
     RECT  163.62 184.843 164.697 184.981 ;
     RECT  117 184.855 161.874 185.125 ;
     RECT  115.815 184.199 116.097 185.251 ;
     RECT  116.856 185.125 161.874 185.251 ;
     RECT  115.815 185.251 161.874 185.323 ;
     RECT  113.904 182.861 113.922 185.431 ;
     RECT  244.26 184.891 244.53 185.431 ;
     RECT  163.62 184.981 165.33 185.549 ;
     RECT  164.415 185.549 165.33 185.597 ;
     RECT  244.044 185.431 244.53 185.597 ;
     RECT  113.76 185.431 113.922 185.701 ;
     RECT  244.116 185.597 244.53 185.701 ;
     RECT  245.415 184.081 247.086 185.701 ;
     RECT  244.116 185.701 244.566 185.729 ;
     RECT  115.815 185.323 162.414 185.803 ;
     RECT  115.452 185.803 162.414 185.819 ;
     RECT  113.616 185.701 113.922 185.837 ;
     RECT  245.415 185.701 247.41 185.837 ;
     RECT  0.036 182.615 0.126 185.855 ;
     RECT  2.415 180.995 2.697 185.971 ;
     RECT  3.528 180.995 4.194 185.971 ;
     RECT  163.62 185.549 163.638 185.971 ;
     RECT  163.188 185.971 163.638 186.089 ;
     RECT  115.452 185.819 162.27 186.161 ;
     RECT  160.02 186.161 162.27 186.173 ;
     RECT  244.26 185.729 244.566 186.187 ;
     RECT  245.415 185.837 247.086 186.187 ;
     RECT  2.415 185.971 4.194 186.269 ;
     RECT  248.292 186.28 248.31 186.286 ;
     RECT  248.22 186.286 248.31 186.317 ;
     RECT  115.452 186.161 159.297 186.359 ;
     RECT  164.415 185.597 164.697 186.427 ;
     RECT  163.584 186.089 163.638 186.539 ;
     RECT  164.415 186.427 165.222 186.601 ;
     RECT  164.415 186.601 165.87 186.629 ;
     RECT  165.852 186.629 165.87 186.653 ;
     RECT  163.62 186.539 163.638 186.701 ;
     RECT  248.22 186.317 248.238 186.749 ;
     RECT  244.26 186.187 247.086 186.859 ;
     RECT  115.74 186.359 159.297 186.907 ;
     RECT  160.02 186.173 161.874 186.907 ;
     RECT  243.072 186.673 243.09 187.169 ;
     RECT  115.74 186.907 161.874 187.177 ;
     RECT  115.74 187.177 162.342 187.213 ;
     RECT  238.284 187.177 238.302 187.277 ;
     RECT  115.74 187.213 162.45 187.285 ;
     RECT  244.26 186.859 247.374 187.321 ;
     RECT  115.704 187.285 162.45 187.349 ;
     RECT  2.415 186.269 2.697 187.411 ;
     RECT  3.528 186.269 4.194 187.411 ;
     RECT  244.116 187.321 247.374 187.411 ;
     RECT  164.415 186.629 164.697 187.435 ;
     RECT  242.244 187.321 242.262 187.439 ;
     RECT  244.116 187.411 247.482 187.469 ;
     RECT  0.036 185.855 0.054 187.475 ;
     RECT  164.415 187.435 165.33 187.475 ;
     RECT  115.704 187.349 162.378 187.511 ;
     RECT  243.36 187.591 243.378 187.709 ;
     RECT  115.704 187.511 161.874 187.745 ;
     RECT  124.704 187.745 161.874 187.781 ;
     RECT  244.26 187.469 247.482 187.949 ;
     RECT  164.415 187.475 164.697 187.951 ;
     RECT  175.215 2.413 175.497 187.951 ;
     RECT  186.015 2.413 186.297 187.951 ;
     RECT  196.815 2.413 197.097 187.951 ;
     RECT  207.615 2.413 207.897 187.951 ;
     RECT  218.415 2.413 218.697 187.951 ;
     RECT  229.215 2.413 229.497 187.951 ;
     RECT  240.015 2.413 240.297 187.951 ;
     RECT  124.74 187.781 161.874 187.997 ;
     RECT  164.304 187.951 164.697 187.997 ;
     RECT  175.104 187.951 175.497 187.997 ;
     RECT  185.904 187.951 186.297 187.997 ;
     RECT  196.704 187.951 197.097 187.997 ;
     RECT  207.504 187.951 207.897 187.997 ;
     RECT  218.304 187.951 218.697 187.997 ;
     RECT  229.104 187.951 229.497 187.997 ;
     RECT  239.904 187.951 240.297 187.997 ;
     RECT  244.26 187.949 247.41 188.045 ;
     RECT  113.904 185.837 113.922 188.131 ;
     RECT  2.415 187.411 4.194 188.159 ;
     RECT  113.904 188.131 114.426 188.249 ;
     RECT  125.028 187.997 161.874 188.251 ;
     RECT  125.028 188.251 162.594 188.291 ;
     RECT  244.368 188.045 247.41 188.333 ;
     RECT  244.368 188.333 247.374 188.381 ;
     RECT  115.704 187.745 123.966 188.401 ;
     RECT  162.72 188.401 162.738 188.519 ;
     RECT  113.904 188.249 114.282 188.669 ;
     RECT  115.2 188.401 123.966 188.923 ;
     RECT  125.028 188.291 161.874 188.923 ;
     RECT  115.2 188.923 161.874 189.095 ;
     RECT  244.656 188.381 247.374 189.211 ;
     RECT  242.244 188.941 242.262 189.239 ;
     RECT  244.008 189.211 247.374 189.401 ;
     RECT  115.2 189.095 124.218 189.437 ;
     RECT  244.008 189.401 246.546 189.509 ;
     RECT  244.188 189.509 246.546 189.599 ;
     RECT  247.356 189.401 247.374 189.599 ;
     RECT  162.792 189.595 162.81 189.635 ;
     RECT  125.028 189.095 161.874 189.707 ;
     RECT  162.936 189.643 163.026 189.869 ;
     RECT  125.604 189.707 161.874 190.021 ;
     RECT  125.604 190.021 161.982 190.139 ;
     RECT  125.604 190.139 161.874 190.319 ;
     RECT  125.604 190.319 161.838 190.349 ;
     RECT  115.2 189.437 123.966 190.381 ;
     RECT  125.604 190.349 161.802 190.525 ;
     RECT  124.776 189.985 124.794 190.553 ;
     RECT  244.512 189.599 246.546 190.561 ;
     RECT  164.415 187.997 164.697 190.651 ;
     RECT  175.215 187.997 175.497 190.651 ;
     RECT  186.015 187.997 186.297 190.651 ;
     RECT  196.815 187.997 197.097 190.651 ;
     RECT  207.615 187.997 207.897 190.651 ;
     RECT  218.415 187.997 218.697 190.651 ;
     RECT  229.215 187.997 229.497 190.651 ;
     RECT  240.015 187.997 240.297 190.651 ;
     RECT  244.332 190.561 246.546 190.685 ;
     RECT  162.936 189.869 162.954 190.949 ;
     RECT  125.532 190.525 161.802 191.021 ;
     RECT  244.512 190.685 246.546 191.117 ;
     RECT  164.304 190.651 164.697 191.129 ;
     RECT  175.104 190.651 175.497 191.129 ;
     RECT  185.904 190.651 186.297 191.129 ;
     RECT  196.704 190.651 197.097 191.129 ;
     RECT  207.504 190.651 207.897 191.129 ;
     RECT  218.304 190.651 218.697 191.129 ;
     RECT  229.104 190.651 229.497 191.129 ;
     RECT  239.904 190.651 240.297 191.129 ;
     RECT  244.728 191.117 246.546 191.219 ;
     RECT  115.2 190.381 124.038 191.489 ;
     RECT  117.648 191.489 124.038 191.525 ;
     RECT  117.72 191.525 124.038 191.641 ;
     RECT  113.904 188.669 113.922 191.899 ;
     RECT  113.76 191.899 113.922 192.001 ;
     RECT  115.2 191.489 116.874 192.001 ;
     RECT  162.9 191.995 162.918 192.001 ;
     RECT  117.72 191.641 124.182 192.029 ;
     RECT  113.4 192.001 113.922 192.065 ;
     RECT  162.9 192.001 163.062 192.065 ;
     RECT  125.928 191.021 161.802 192.145 ;
     RECT  114.696 192.001 116.874 192.181 ;
     RECT  124.992 192.043 125.01 192.181 ;
     RECT  125.784 192.145 161.802 192.181 ;
     RECT  3.528 188.159 4.194 192.299 ;
     RECT  114.264 192.181 116.874 192.299 ;
     RECT  113.4 192.065 113.418 192.335 ;
     RECT  244.728 191.219 246.15 192.415 ;
     RECT  115.308 192.299 116.874 192.451 ;
     RECT  117.72 192.029 124.038 192.451 ;
     RECT  124.992 192.181 161.802 192.721 ;
     RECT  244.656 192.415 246.15 192.839 ;
     RECT  115.308 192.451 124.038 193.081 ;
     RECT  124.992 192.721 162.126 193.081 ;
     RECT  163.044 192.065 163.062 193.081 ;
     RECT  243.18 192.685 243.198 193.109 ;
     RECT  244.728 192.839 245.898 193.109 ;
     RECT  115.308 193.081 163.062 193.195 ;
     RECT  115.2 193.195 163.062 193.225 ;
     RECT  245.415 193.109 245.898 193.379 ;
     RECT  114.984 193.225 163.062 194.093 ;
     RECT  115.02 194.093 163.062 194.369 ;
     RECT  115.092 194.369 163.062 195.151 ;
     RECT  110.415 2.413 110.697 195.241 ;
     RECT  115.092 195.151 163.314 195.259 ;
     RECT  3.636 192.299 4.194 195.269 ;
     RECT  113.544 195.259 113.562 195.305 ;
     RECT  110.415 195.241 110.754 195.413 ;
     RECT  114.624 195.259 163.314 195.421 ;
     RECT  114.516 195.421 163.314 195.539 ;
     RECT  114.588 195.539 163.314 196.079 ;
     RECT  114.588 196.079 163.062 196.691 ;
     RECT  4.068 195.269 4.194 197.159 ;
     RECT  113.652 197.167 113.67 197.213 ;
     RECT  114.588 196.691 162.558 198.211 ;
     RECT  114.588 198.211 163.134 198.379 ;
     RECT  114.516 198.379 163.134 198.815 ;
     RECT  115.128 198.815 163.134 199.319 ;
     RECT  115.128 199.319 128.142 199.859 ;
     RECT  4.068 197.159 4.086 200.129 ;
     RECT  115.128 199.859 122.706 200.129 ;
     RECT  115.128 200.129 116.514 200.245 ;
     RECT  123.696 199.859 128.142 200.281 ;
     RECT  128.88 199.319 163.134 200.281 ;
     RECT  113.76 200.245 113.778 200.285 ;
     RECT  114.84 200.245 116.514 200.285 ;
     RECT  117.396 200.129 122.706 200.641 ;
     RECT  123.696 200.281 163.134 200.641 ;
     RECT  115.128 200.285 116.514 200.669 ;
     RECT  115.488 200.669 116.514 201.019 ;
     RECT  117.396 200.641 163.134 201.019 ;
     RECT  5.976 178.573 5.994 201.479 ;
     RECT  114.084 201.211 114.102 201.515 ;
     RECT  115.488 201.019 163.134 201.631 ;
     RECT  115.308 201.631 163.134 202.555 ;
     RECT  115.272 202.555 163.134 202.595 ;
     RECT  115.596 202.595 163.134 202.901 ;
     RECT  115.596 202.901 120.402 203.405 ;
     RECT  115.74 203.405 120.402 203.755 ;
     RECT  121.215 202.901 163.134 203.755 ;
     RECT  115.74 203.755 163.134 204.077 ;
     RECT  122.544 204.077 163.134 204.215 ;
     RECT  2.415 188.159 2.697 204.331 ;
     RECT  3.636 203.989 3.654 204.331 ;
     RECT  2.415 204.331 3.654 204.449 ;
     RECT  122.544 204.215 124.362 204.449 ;
     RECT  122.544 204.449 124.182 204.521 ;
     RECT  0.504 204.529 0.522 204.601 ;
     RECT  0.504 204.601 0.558 204.749 ;
     RECT  115.74 204.077 121.626 204.755 ;
     RECT  0.504 204.749 0.522 204.845 ;
     RECT  122.544 204.521 124.146 204.871 ;
     RECT  2.415 204.449 3.474 204.907 ;
     RECT  120.996 204.755 121.626 204.961 ;
     RECT  122.436 204.871 124.146 204.961 ;
     RECT  114.588 204.871 114.606 205.061 ;
     RECT  2.304 204.907 3.474 205.133 ;
     RECT  2.415 205.133 3.474 205.169 ;
     RECT  2.415 205.169 2.898 205.295 ;
     RECT  115.74 204.755 120.114 205.295 ;
     RECT  120.996 204.961 124.146 205.295 ;
     RECT  121.215 205.295 124.146 205.375 ;
     RECT  115.815 205.295 120.114 205.565 ;
     RECT  115.815 205.565 119.862 205.601 ;
     RECT  115.815 205.601 119.07 205.799 ;
     RECT  119.844 205.601 119.862 205.799 ;
     RECT  115.815 205.799 118.998 205.805 ;
     RECT  121.215 205.375 124.218 205.915 ;
     RECT  125.1 204.215 163.134 205.915 ;
     RECT  117.504 205.805 118.998 206.069 ;
     RECT  121.215 205.915 163.134 206.069 ;
     RECT  117.504 206.069 118.926 206.105 ;
     RECT  125.028 206.069 163.134 206.105 ;
     RECT  117.72 206.105 118.926 206.141 ;
     RECT  117.864 206.141 118.926 206.213 ;
     RECT  125.1 206.105 163.134 206.221 ;
     RECT  118.584 206.213 118.926 206.237 ;
     RECT  125.1 206.221 163.206 206.609 ;
     RECT  121.215 206.069 124.218 206.887 ;
     RECT  125.1 206.609 160.974 206.887 ;
     RECT  161.784 206.609 163.206 207.221 ;
     RECT  121.215 206.887 160.974 207.391 ;
     RECT  161.784 207.221 163.17 207.391 ;
     RECT  119.16 207.661 119.178 207.725 ;
     RECT  121.215 207.391 163.17 207.787 ;
     RECT  120.708 207.787 163.17 207.959 ;
     RECT  121.215 207.959 163.17 208.103 ;
     RECT  121.215 208.103 158.166 208.571 ;
     RECT  158.904 208.103 163.17 208.571 ;
     RECT  122.292 208.571 158.166 208.849 ;
     RECT  158.904 208.571 162.99 208.849 ;
     RECT  122.292 208.849 162.99 209.147 ;
     RECT  122.292 209.147 162.774 209.309 ;
     RECT  122.292 209.309 162.738 209.723 ;
     RECT  122.544 209.723 162.738 209.849 ;
     RECT  122.544 209.849 162.234 210.155 ;
     RECT  122.544 210.155 161.334 210.191 ;
     RECT  123.156 210.191 161.334 210.227 ;
     RECT  123.408 210.227 123.426 210.389 ;
     RECT  124.236 210.227 161.334 210.389 ;
     RECT  124.236 210.389 161.046 210.425 ;
     RECT  124.236 210.425 160.974 211.505 ;
     RECT  124.632 211.505 160.974 212.279 ;
     RECT  124.632 212.279 160.722 212.657 ;
     RECT  124.632 212.657 160.686 212.819 ;
     RECT  124.632 212.819 160.65 213.101 ;
     RECT  125.136 213.101 160.65 213.629 ;
     RECT  125.136 213.629 160.398 214.411 ;
     RECT  124.848 214.411 160.398 214.547 ;
     RECT  124.848 214.547 154.818 214.591 ;
     RECT  124.704 214.591 154.818 214.709 ;
     RECT  124.704 214.709 127.854 214.853 ;
     RECT  124.704 214.853 127.782 214.979 ;
     RECT  125.532 214.979 127.782 215.635 ;
     RECT  128.592 214.709 154.818 215.635 ;
     RECT  125.532 215.635 154.818 215.671 ;
     RECT  155.592 214.547 160.398 215.671 ;
     RECT  125.532 215.671 160.398 216.059 ;
     RECT  124.704 214.979 124.722 216.167 ;
     RECT  125.568 216.059 160.146 216.365 ;
     RECT  125.604 216.365 160.146 216.869 ;
     RECT  125.604 216.869 160.002 217.679 ;
     RECT  125.604 217.679 159.894 217.757 ;
     RECT  125.604 217.757 127.026 217.831 ;
     RECT  125.424 217.831 127.026 217.915 ;
     RECT  127.8 217.757 159.894 217.949 ;
     RECT  125.28 217.915 127.026 217.955 ;
     RECT  127.8 217.949 159.642 218.021 ;
     RECT  127.908 218.021 159.642 218.219 ;
     RECT  125.604 217.955 127.026 218.525 ;
     RECT  127.908 218.219 128.97 218.767 ;
     RECT  129.816 218.219 159.642 218.875 ;
     RECT  126.468 218.525 127.026 218.903 ;
     RECT  126.615 218.903 127.026 218.911 ;
     RECT  127.836 218.767 128.97 218.911 ;
     RECT  126.615 218.911 128.97 219.001 ;
     RECT  129.816 218.875 159.75 219.001 ;
     RECT  126.615 219.001 159.75 219.299 ;
     RECT  126.615 219.299 159.642 219.721 ;
     RECT  125.604 218.525 125.622 220.189 ;
     RECT  126.54 219.721 159.642 220.189 ;
     RECT  125.604 220.189 159.642 220.649 ;
     RECT  125.604 220.649 159.354 221.027 ;
     RECT  125.604 221.027 159.297 221.333 ;
     RECT  125.604 221.333 154.17 222.277 ;
     RECT  125.604 222.277 154.314 222.305 ;
     RECT  155.052 221.333 159.297 222.575 ;
     RECT  126.615 222.305 154.314 222.619 ;
     RECT  155.052 222.575 157.014 222.619 ;
     RECT  126.615 222.619 157.014 223.079 ;
     RECT  125.604 222.305 125.622 223.387 ;
     RECT  126.615 223.079 156.474 223.387 ;
     RECT  125.604 223.387 156.474 223.427 ;
     RECT  157.824 222.575 159.297 223.619 ;
     RECT  126.615 223.427 156.474 223.861 ;
     RECT  126.615 223.861 156.726 224.275 ;
     RECT  126.615 224.275 157.05 224.429 ;
     RECT  151.992 224.429 157.05 224.581 ;
     RECT  151.992 224.581 157.158 224.815 ;
     RECT  157.968 223.619 159.297 224.815 ;
     RECT  151.992 224.815 159.297 224.969 ;
     RECT  126.615 224.429 151.182 224.977 ;
     RECT  151.992 224.969 157.554 225.005 ;
     RECT  126.504 224.977 151.182 225.053 ;
     RECT  151.992 225.005 156.834 225.275 ;
     RECT  129.96 225.053 151.182 225.319 ;
     RECT  151.992 225.275 156.726 225.319 ;
     RECT  129.96 225.319 156.726 225.347 ;
     RECT  130.032 225.347 156.726 225.509 ;
     RECT  130.032 225.509 155.862 225.959 ;
     RECT  126.615 225.053 129.15 226.165 ;
     RECT  130.032 225.959 155.574 226.165 ;
     RECT  125.604 223.427 125.622 226.315 ;
     RECT  126.615 226.165 155.574 226.315 ;
     RECT  125.604 226.315 155.574 226.499 ;
     RECT  156.708 225.509 156.726 226.589 ;
     RECT  126.072 226.499 155.574 226.625 ;
     RECT  126.615 226.625 155.574 227.309 ;
     RECT  128.664 227.309 155.574 227.549 ;
     RECT  128.916 227.549 155.574 227.849 ;
     RECT  131.688 227.849 155.574 227.939 ;
     RECT  131.688 227.939 155.538 228.515 ;
     RECT  128.916 227.849 130.806 228.595 ;
     RECT  131.688 228.515 155.43 228.595 ;
     RECT  128.916 228.595 155.43 228.631 ;
     RECT  128.844 228.631 155.43 228.749 ;
     RECT  128.844 228.749 155.322 229.019 ;
     RECT  128.844 229.019 154.998 229.055 ;
     RECT  128.844 229.055 154.854 229.135 ;
     RECT  128.772 229.135 154.854 229.829 ;
     RECT  128.844 229.829 154.818 230.207 ;
     RECT  128.844 230.207 129.546 230.243 ;
     RECT  129.528 230.243 129.546 230.333 ;
     RECT  130.284 230.207 154.818 230.639 ;
     RECT  154.8 230.639 154.818 231.179 ;
     RECT  130.284 230.639 153.897 231.295 ;
     RECT  130.032 231.295 153.897 231.871 ;
     RECT  129.384 231.871 153.897 231.979 ;
     RECT  129.204 231.979 153.897 232.169 ;
     RECT  129.204 232.169 151.326 232.403 ;
     RECT  152.172 232.169 153.897 232.529 ;
     RECT  152.712 232.529 152.73 232.601 ;
     RECT  129.528 232.403 151.326 232.951 ;
     RECT  129.528 232.951 151.542 233.491 ;
     RECT  129.528 233.491 151.866 233.609 ;
     RECT  151.848 233.609 151.866 233.681 ;
     RECT  129.528 233.609 150.75 233.879 ;
     RECT  129.528 233.879 129.906 233.987 ;
     RECT  130.824 233.879 150.75 234.419 ;
     RECT  130.824 234.419 150.426 234.455 ;
     RECT  131.292 234.455 150.426 235.273 ;
     RECT  131.292 235.273 150.462 235.421 ;
     RECT  131.76 235.421 150.462 235.615 ;
     RECT  131.76 235.615 150.75 235.651 ;
     RECT  131.76 235.651 151.11 235.841 ;
     RECT  131.76 235.841 149.346 236.381 ;
     RECT  131.76 236.381 135.414 236.389 ;
     RECT  131.688 236.389 135.414 236.417 ;
     RECT  133.668 236.417 135.414 236.429 ;
     RECT  131.688 236.417 132.858 236.587 ;
     RECT  131.292 236.587 132.858 236.731 ;
     RECT  131.112 236.731 132.858 237.001 ;
     RECT  130.716 237.001 132.858 237.163 ;
     RECT  133.668 236.429 135.378 237.163 ;
     RECT  130.716 237.163 135.378 237.271 ;
     RECT  136.368 236.381 149.346 237.397 ;
     RECT  136.26 237.397 149.346 237.433 ;
     RECT  130.572 237.271 135.414 237.505 ;
     RECT  136.188 237.433 149.346 237.505 ;
     RECT  130.572 237.505 149.346 237.775 ;
     RECT  130.572 237.775 149.382 237.811 ;
     RECT  130.572 237.811 149.886 237.929 ;
     RECT  130.572 237.929 148.734 238.009 ;
     RECT  130.536 238.009 148.734 238.243 ;
     RECT  149.868 237.929 149.886 238.271 ;
     RECT  130.392 238.243 148.734 238.351 ;
     RECT  130.284 238.351 148.734 238.549 ;
     RECT  129.672 238.549 148.734 238.775 ;
     RECT  136.26 238.775 148.734 239.009 ;
     RECT  129.672 238.775 135.522 239.423 ;
     RECT  129.852 239.423 135.522 239.701 ;
     RECT  136.26 239.009 148.497 239.701 ;
     RECT  129.852 239.701 148.497 239.963 ;
     RECT  129.96 239.963 148.497 239.971 ;
     RECT  129.96 239.971 148.734 240.089 ;
     RECT  129.96 240.089 148.497 240.467 ;
     RECT  130.212 240.467 148.497 240.629 ;
     RECT  130.212 240.629 139.986 240.665 ;
     RECT  130.212 240.665 134.874 240.701 ;
     RECT  133.956 240.701 134.586 240.899 ;
     RECT  140.904 240.629 148.497 240.899 ;
     RECT  133.956 240.899 134.19 240.935 ;
     RECT  130.212 240.701 133.038 241.205 ;
     RECT  135.648 240.665 139.986 241.241 ;
     RECT  140.904 240.899 147.186 241.475 ;
     RECT  133.956 240.935 133.974 241.591 ;
     RECT  145.332 241.475 147.186 241.675 ;
     RECT  148.215 240.899 148.497 241.675 ;
     RECT  130.5 241.205 133.038 241.745 ;
     RECT  140.904 241.475 144.378 241.753 ;
     RECT  130.5 241.745 131.13 241.817 ;
     RECT  131.904 241.745 133.038 241.825 ;
     RECT  133.776 241.591 133.974 241.825 ;
     RECT  131.904 241.825 133.974 241.861 ;
     RECT  130.536 241.817 131.13 241.889 ;
     RECT  131.904 241.861 134.226 241.979 ;
     RECT  131.904 241.979 133.974 242.123 ;
     RECT  136.008 241.241 139.986 242.131 ;
     RECT  140.796 241.753 144.378 242.131 ;
     RECT  131.904 242.123 133.074 242.249 ;
     RECT  136.008 242.131 144.378 242.257 ;
     RECT  145.332 241.675 148.497 242.257 ;
     RECT  130.536 241.889 130.554 242.285 ;
     RECT  131.904 242.249 132.75 242.291 ;
     RECT  136.008 242.257 148.497 242.401 ;
     RECT  136.008 242.401 148.914 242.527 ;
     RECT  132.015 242.291 132.75 242.555 ;
     RECT  133.956 242.123 133.974 242.555 ;
     RECT  135.9 242.527 148.914 242.599 ;
     RECT  135.792 242.599 148.914 242.825 ;
     RECT  135.792 242.825 139.518 243.163 ;
     RECT  132.015 242.555 132.714 243.329 ;
     RECT  132.015 243.329 132.39 243.401 ;
     RECT  140.436 242.825 148.734 243.599 ;
     RECT  140.436 243.599 148.497 243.773 ;
     RECT  135.36 243.163 139.518 243.905 ;
     RECT  135.684 243.905 139.518 244.291 ;
     RECT  135.684 244.291 139.554 244.319 ;
     RECT  135.972 244.319 139.554 244.409 ;
     RECT  140.616 243.773 148.497 244.409 ;
     RECT  146.484 244.409 146.502 244.451 ;
     RECT  136.44 244.409 139.554 244.481 ;
     RECT  147.276 244.409 147.438 244.481 ;
     RECT  140.616 244.409 145.566 244.493 ;
     RECT  136.8 244.481 139.554 244.525 ;
     RECT  140.616 244.493 144.558 244.525 ;
     RECT  136.8 244.525 144.558 244.679 ;
     RECT  136.8 244.679 144.522 244.715 ;
     RECT  145.548 244.493 145.566 244.715 ;
     RECT  147.276 244.481 147.294 244.715 ;
     RECT  137.268 244.715 144.522 244.823 ;
     RECT  137.268 244.823 144.198 244.949 ;
     RECT  137.268 244.949 139.338 245.219 ;
     RECT  137.268 245.219 139.266 245.255 ;
     RECT  140.688 244.949 144.198 245.255 ;
     RECT  137.268 245.255 138.222 245.327 ;
     RECT  139.068 245.255 139.266 245.327 ;
     RECT  137.415 245.327 138.222 245.363 ;
     RECT  139.248 245.327 139.266 245.363 ;
     RECT  140.688 245.255 143.154 245.525 ;
     RECT  144.18 245.255 144.198 245.525 ;
     RECT  140.724 245.525 143.154 245.669 ;
     RECT  140.724 245.669 143.097 246.451 ;
     RECT  140.724 246.451 143.766 246.569 ;
     RECT  140.652 246.571 140.67 246.611 ;
     RECT  141.444 246.569 143.298 246.875 ;
     RECT  141.876 246.875 143.19 246.911 ;
     RECT  142.488 246.911 143.19 247.181 ;
     RECT  135.828 275.899 135.846 275.999 ;
     RECT  135.504 276.139 135.522 276.179 ;
     RECT  126.615 227.309 127.53 292.199 ;
     RECT  132.015 243.401 132.297 292.351 ;
     RECT  2.415 205.295 2.697 369.107 ;
     RECT  7.815 2.413 8.097 369.107 ;
     RECT  13.215 2.413 13.497 369.107 ;
     RECT  18.615 2.413 18.897 369.107 ;
     RECT  24.015 2.413 24.297 369.107 ;
     RECT  29.415 2.413 29.697 369.107 ;
     RECT  34.815 2.413 35.097 369.107 ;
     RECT  40.215 2.413 40.497 369.107 ;
     RECT  45.615 2.413 45.897 369.107 ;
     RECT  51.015 2.413 51.297 369.107 ;
     RECT  56.415 2.413 56.697 369.107 ;
     RECT  61.815 2.413 62.097 369.107 ;
     RECT  67.215 2.413 67.497 369.107 ;
     RECT  72.615 2.413 72.897 369.107 ;
     RECT  78.015 2.413 78.297 369.107 ;
     RECT  83.415 2.413 83.697 369.107 ;
     RECT  88.815 2.413 89.097 369.107 ;
     RECT  94.215 2.413 94.497 369.107 ;
     RECT  99.615 2.413 99.897 369.107 ;
     RECT  105.015 2.413 105.297 369.107 ;
     RECT  110.415 195.413 110.697 369.107 ;
     RECT  115.815 205.805 116.097 369.107 ;
     RECT  121.215 208.571 121.497 369.107 ;
     RECT  126.615 292.199 126.897 369.107 ;
     RECT  137.415 245.363 137.697 369.107 ;
     RECT  142.815 247.181 143.097 369.107 ;
     RECT  148.215 244.409 148.497 369.107 ;
     RECT  153.615 232.529 153.897 369.107 ;
     RECT  159.015 224.969 159.297 369.107 ;
     RECT  164.415 191.129 164.697 369.107 ;
     RECT  169.815 181.805 170.097 369.107 ;
     RECT  175.215 191.129 175.497 369.107 ;
     RECT  180.615 2.413 180.897 369.107 ;
     RECT  186.015 191.129 186.297 369.107 ;
     RECT  191.415 2.413 191.697 369.107 ;
     RECT  196.815 191.129 197.097 369.107 ;
     RECT  202.215 2.413 202.497 369.107 ;
     RECT  207.615 191.129 207.897 369.107 ;
     RECT  213.015 2.413 213.297 369.107 ;
     RECT  218.415 191.129 218.697 369.107 ;
     RECT  223.815 2.413 224.097 369.107 ;
     RECT  229.215 191.129 229.497 369.107 ;
     RECT  234.615 2.413 234.897 369.107 ;
     RECT  240.015 191.129 240.297 369.107 ;
     RECT  245.415 193.379 245.697 369.107 ;
     RECT  2.415 369.107 2.505 369.377 ;
     RECT  7.815 369.107 7.905 369.377 ;
     RECT  13.215 369.107 13.305 369.377 ;
     RECT  18.615 369.107 18.705 369.377 ;
     RECT  24.015 369.107 24.105 369.377 ;
     RECT  29.415 369.107 29.505 369.377 ;
     RECT  34.815 369.107 34.905 369.377 ;
     RECT  40.215 369.107 40.305 369.377 ;
     RECT  45.615 369.107 45.705 369.377 ;
     RECT  51.015 369.107 51.105 369.377 ;
     RECT  56.415 369.107 56.505 369.377 ;
     RECT  61.815 369.107 61.905 369.377 ;
     RECT  67.215 369.107 67.305 369.377 ;
     RECT  72.615 369.107 72.705 369.377 ;
     RECT  78.015 369.107 78.105 369.377 ;
     RECT  83.415 369.107 83.505 369.377 ;
     RECT  88.815 369.107 88.905 369.377 ;
     RECT  94.215 369.107 94.305 369.377 ;
     RECT  99.615 369.107 99.705 369.377 ;
     RECT  105.015 369.107 105.105 369.377 ;
     RECT  110.415 369.107 110.505 369.377 ;
     RECT  115.815 369.107 115.905 369.377 ;
     RECT  121.215 369.107 121.305 369.377 ;
     RECT  126.615 369.107 126.705 369.377 ;
     RECT  132.015 292.351 132.498 369.377 ;
     RECT  137.415 369.107 137.505 369.377 ;
     RECT  142.815 369.107 142.905 369.377 ;
     RECT  148.215 369.107 148.305 369.377 ;
     RECT  153.615 369.107 153.705 369.377 ;
     RECT  159.015 369.107 159.105 369.377 ;
     RECT  164.415 369.107 164.505 369.377 ;
     RECT  169.815 369.107 169.905 369.377 ;
     RECT  175.215 369.107 175.305 369.377 ;
     RECT  180.615 369.107 180.705 369.377 ;
     RECT  186.015 369.107 186.105 369.377 ;
     RECT  191.415 369.107 191.505 369.377 ;
     RECT  196.815 369.107 196.905 369.377 ;
     RECT  202.215 369.107 202.305 369.377 ;
     RECT  207.615 369.107 207.705 369.377 ;
     RECT  213.015 369.107 213.105 369.377 ;
     RECT  218.415 369.107 218.505 369.377 ;
     RECT  223.815 369.107 223.905 369.377 ;
     RECT  229.215 369.107 229.305 369.377 ;
     RECT  234.615 369.107 234.705 369.377 ;
     RECT  240.015 369.107 240.105 369.377 ;
     RECT  245.415 369.107 245.505 369.377 ;
     RECT  132.48 369.377 132.498 371.213 ;
     RECT  133.992 245.371 134.01 371.405 ;
    LAYER M4 ;
     RECT  0.025 178.944 0.06 178.968 ;
     RECT  0.06 175.728 0.061 178.968 ;
     RECT  0.061 175.632 0.173 178.968 ;
     RECT  0.173 175.728 0.209 178.968 ;
     RECT  0.06 204.72 0.569 205.128 ;
     RECT  0.209 175.728 2.408 178.536 ;
     RECT  0.569 204.912 2.408 205.128 ;
     RECT  2.408 2.148 2.512 369.372 ;
     RECT  2.512 2.418 2.704 369.102 ;
     RECT  2.704 205.008 2.837 205.128 ;
     RECT  2.704 175.824 2.873 178.344 ;
     RECT  2.873 175.824 2.909 178.056 ;
     RECT  2.837 205.104 2.909 205.128 ;
     RECT  2.909 175.824 3.341 177.768 ;
     RECT  3.341 175.824 3.413 177.48 ;
     RECT  3.413 177.312 4.313 177.48 ;
     RECT  4.313 177.312 4.565 177.336 ;
     RECT  3.413 175.824 5.249 176.136 ;
     RECT  5.249 175.824 5.501 175.848 ;
     RECT  7.808 2.148 7.912 369.372 ;
     RECT  7.912 2.418 8.104 369.102 ;
     RECT  13.208 2.148 13.312 369.372 ;
     RECT  13.312 2.418 13.504 369.102 ;
     RECT  18.608 2.148 18.712 369.372 ;
     RECT  18.712 2.418 18.904 369.102 ;
     RECT  24.008 2.148 24.112 369.372 ;
     RECT  24.112 2.418 24.304 369.102 ;
     RECT  29.408 2.148 29.512 369.372 ;
     RECT  29.512 2.418 29.704 369.102 ;
     RECT  34.808 2.148 34.912 369.372 ;
     RECT  34.912 2.418 35.104 369.102 ;
     RECT  40.208 2.148 40.312 369.372 ;
     RECT  40.312 2.418 40.504 369.102 ;
     RECT  45.608 2.148 45.712 369.372 ;
     RECT  45.712 2.418 45.904 369.102 ;
     RECT  51.008 2.148 51.112 369.372 ;
     RECT  51.112 2.418 51.304 369.102 ;
     RECT  56.408 2.148 56.512 369.372 ;
     RECT  56.512 2.418 56.704 369.102 ;
     RECT  61.808 2.148 61.912 369.372 ;
     RECT  61.912 2.418 62.104 369.102 ;
     RECT  67.208 2.148 67.312 369.372 ;
     RECT  67.312 2.418 67.504 369.102 ;
     RECT  72.608 2.148 72.712 369.372 ;
     RECT  72.712 2.418 72.904 369.102 ;
     RECT  78.008 2.148 78.112 369.372 ;
     RECT  78.112 2.418 78.304 369.102 ;
     RECT  83.408 2.148 83.512 369.372 ;
     RECT  83.512 2.418 83.704 369.102 ;
     RECT  88.808 2.148 88.912 369.372 ;
     RECT  88.912 2.418 89.104 369.102 ;
     RECT  94.208 2.148 94.312 369.372 ;
     RECT  94.312 2.418 94.504 369.102 ;
     RECT  99.608 2.148 99.712 369.372 ;
     RECT  99.712 2.418 99.904 369.102 ;
     RECT  105.008 2.148 105.112 369.372 ;
     RECT  105.112 2.418 105.304 369.102 ;
     RECT  110.408 2.148 110.512 369.372 ;
     RECT  110.512 2.418 110.704 369.102 ;
     RECT  113.749 200.256 113.989 200.28 ;
     RECT  113.989 200.256 114.113 201.24 ;
     RECT  114.469 182.832 114.611 182.856 ;
     RECT  113.533 195.264 114.613 195.288 ;
     RECT  113.641 197.184 114.685 197.208 ;
     RECT  114.613 195.264 114.717 195.432 ;
     RECT  114.505 198.384 114.797 198.792 ;
     RECT  114.717 195.408 115.093 195.432 ;
     RECT  114.685 196.464 115.093 197.208 ;
     RECT  114.613 194.064 115.189 194.088 ;
     RECT  113.749 191.904 115.333 191.928 ;
     RECT  114.289 176.064 115.369 176.088 ;
     RECT  114.797 198.768 115.436 198.792 ;
     RECT  114.113 200.256 115.436 200.28 ;
     RECT  114.253 188.64 115.441 188.664 ;
     RECT  115.333 191.904 115.693 192.072 ;
     RECT  115.189 193.2 115.693 194.088 ;
     RECT  115.369 176.064 115.808 176.136 ;
     RECT  115.585 177.216 115.808 177.24 ;
     RECT  114.565 184.32 115.808 184.344 ;
     RECT  113.605 185.808 115.808 185.832 ;
     RECT  115.441 188.64 115.808 189.384 ;
     RECT  115.693 191.904 115.808 194.088 ;
     RECT  115.093 195.408 115.808 197.208 ;
     RECT  115.436 198.768 115.808 200.28 ;
     RECT  115.261 202.56 115.808 202.584 ;
     RECT  115.808 2.148 115.912 369.372 ;
     RECT  115.912 2.418 116.104 369.102 ;
     RECT  116.104 190.8 116.243 195 ;
     RECT  116.104 198.912 116.243 200.184 ;
     RECT  116.104 201.6 116.243 202.584 ;
     RECT  116.243 192.576 116.281 195 ;
     RECT  116.104 173.952 116.291 176.136 ;
     RECT  116.104 183.504 116.291 184.344 ;
     RECT  116.104 177.216 116.309 177.24 ;
     RECT  116.104 196.032 116.309 196.488 ;
     RECT  116.104 197.76 116.435 197.784 ;
     RECT  116.291 173.952 116.489 174.408 ;
     RECT  116.281 192.576 116.525 193.224 ;
     RECT  116.243 198.912 116.525 200.088 ;
     RECT  116.291 175.728 116.597 176.136 ;
     RECT  116.525 193.2 116.741 193.224 ;
     RECT  116.104 205.248 116.813 205.8 ;
     RECT  116.104 185.808 116.921 187.32 ;
     RECT  116.104 189.36 117.065 189.384 ;
     RECT  116.921 185.808 117.349 186.36 ;
     RECT  117.349 197.52 117.533 197.544 ;
     RECT  116.525 199.68 117.533 200.088 ;
     RECT  117.533 199.68 117.569 199.704 ;
     RECT  116.281 194.304 117.605 195 ;
     RECT  116.597 175.728 117.637 175.752 ;
     RECT  116.243 191.472 117.637 191.496 ;
     RECT  116.813 205.392 117.641 205.8 ;
     RECT  117.637 191.376 117.677 191.496 ;
     RECT  116.243 202.56 117.709 202.584 ;
     RECT  116.489 173.952 117.745 173.976 ;
     RECT  117.637 175.728 117.745 176.184 ;
     RECT  117.709 202.176 117.745 202.584 ;
     RECT  116.104 203.904 117.745 203.928 ;
     RECT  116.309 196.032 117.817 196.056 ;
     RECT  116.104 165.696 117.821 165.72 ;
     RECT  117.385 181.488 117.853 181.512 ;
     RECT  117.745 173.376 117.925 173.976 ;
     RECT  117.745 202.176 117.925 203.928 ;
     RECT  117.925 173.232 117.971 173.976 ;
     RECT  117.853 180.672 117.971 181.512 ;
     RECT  117.925 202.176 117.971 204.648 ;
     RECT  117.971 203.232 118.012 203.4 ;
     RECT  117.745 175.584 118.037 176.184 ;
     RECT  117.641 205.776 118.037 205.8 ;
     RECT  117.349 185.088 118.109 186.36 ;
     RECT  118.012 203.376 118.145 203.4 ;
     RECT  117.605 194.352 118.165 195 ;
     RECT  117.817 196.032 118.165 196.632 ;
     RECT  117.971 173.232 118.217 173.544 ;
     RECT  117.745 197.808 118.217 198.408 ;
     RECT  117.971 204.624 118.253 204.648 ;
     RECT  117.971 181.488 118.357 181.512 ;
     RECT  118.217 173.376 118.361 173.544 ;
     RECT  118.217 197.808 118.451 198.36 ;
     RECT  116.291 183.504 118.469 183.528 ;
     RECT  118.165 194.352 118.537 196.632 ;
     RECT  118.357 181.488 118.541 181.56 ;
     RECT  118.451 198.336 118.541 198.36 ;
     RECT  118.465 200.688 118.573 200.712 ;
     RECT  118.573 200.016 118.613 200.712 ;
     RECT  117.781 167.04 118.652 167.064 ;
     RECT  118.645 178.32 118.717 178.344 ;
     RECT  118.361 173.52 118.721 173.544 ;
     RECT  118.652 167.04 118.739 167.976 ;
     RECT  118.105 188.496 118.789 188.52 ;
     RECT  118.739 167.04 118.825 167.064 ;
     RECT  117.677 191.376 118.829 191.4 ;
     RECT  118.825 166.416 118.865 167.064 ;
     RECT  118.537 194.352 118.901 196.968 ;
     RECT  118.573 176.784 118.933 176.808 ;
     RECT  118.109 185.376 118.94 186.36 ;
     RECT  118.933 174.528 119.005 174.552 ;
     RECT  118.94 185.376 119.027 186.936 ;
     RECT  119.027 185.376 119.075 186.456 ;
     RECT  118.717 178.32 119.081 179.064 ;
     RECT  118.901 194.352 119.081 195.096 ;
     RECT  119.041 170.304 119.125 170.328 ;
     RECT  118.037 175.632 119.125 175.752 ;
     RECT  118.933 176.784 119.153 177.096 ;
     RECT  119.125 170.304 119.171 171 ;
     RECT  119.125 175.584 119.171 175.752 ;
     RECT  119.041 192.864 119.189 192.888 ;
     RECT  118.789 188.496 119.225 188.712 ;
     RECT  118.573 169.248 119.257 169.272 ;
     RECT  119.153 177.072 119.257 177.096 ;
     RECT  119.171 170.4 119.293 171 ;
     RECT  119.171 175.584 119.297 175.656 ;
     RECT  119.228 184.32 119.315 184.344 ;
     RECT  118.573 206.208 119.317 206.232 ;
     RECT  119.293 170.4 119.324 171.816 ;
     RECT  119.257 168.672 119.341 169.272 ;
     RECT  118.933 180.096 119.369 180.12 ;
     RECT  119.317 205.008 119.404 206.232 ;
     RECT  119.324 170.4 119.411 172.632 ;
     RECT  119.075 185.376 119.441 186.36 ;
     RECT  118.541 181.536 119.509 181.56 ;
     RECT  118.865 166.416 119.513 166.44 ;
     RECT  119.005 173.664 119.581 174.552 ;
     RECT  119.297 175.584 119.581 175.608 ;
     RECT  119.509 181.536 119.581 181.8 ;
     RECT  119.225 188.496 119.581 188.52 ;
     RECT  119.149 207.696 119.605 207.72 ;
     RECT  119.404 206.208 119.651 206.232 ;
     RECT  119.545 202.512 119.653 202.536 ;
     RECT  119.653 198.384 119.689 198.408 ;
     RECT  119.653 202.512 119.701 203.112 ;
     RECT  119.581 181.536 119.747 182.424 ;
     RECT  119.404 205.008 119.837 205.032 ;
     RECT  119.747 181.536 119.905 182.376 ;
     RECT  118.901 196.224 119.905 196.968 ;
     RECT  119.653 164.688 119.909 164.712 ;
     RECT  119.411 170.4 119.945 171.816 ;
     RECT  119.905 181.248 119.977 182.376 ;
     RECT  119.581 173.664 120.017 175.608 ;
     RECT  119.081 178.32 120.044 178.392 ;
     RECT  119.341 169.152 120.053 169.272 ;
     RECT  119.689 198.384 120.053 198.6 ;
     RECT  119.977 181.104 120.085 182.376 ;
     RECT  118.613 200.016 120.092 200.04 ;
     RECT  119.701 201.6 120.121 203.112 ;
     RECT  120.044 178.32 120.131 179.304 ;
     RECT  120.017 173.664 120.161 174.552 ;
     RECT  120.053 198.384 120.161 198.408 ;
     RECT  120.092 200.016 120.179 200.28 ;
     RECT  120.085 180.384 120.197 182.376 ;
     RECT  119.441 185.808 120.229 186.36 ;
     RECT  119.581 187.536 120.229 188.52 ;
     RECT  119.081 194.976 120.229 195.096 ;
     RECT  120.229 194.496 120.373 195.096 ;
     RECT  120.373 194.4 120.481 195.096 ;
     RECT  119.905 196.224 120.481 197.208 ;
     RECT  120.017 175.584 120.517 175.608 ;
     RECT  119.257 177.072 120.589 177.288 ;
     RECT  120.131 178.32 120.589 178.344 ;
     RECT  120.229 191.616 120.661 191.64 ;
     RECT  120.445 192.912 120.661 192.936 ;
     RECT  120.301 160.128 120.733 160.152 ;
     RECT  120.517 175.584 120.853 175.8 ;
     RECT  120.589 177.072 120.853 178.344 ;
     RECT  120.197 180.816 120.853 182.376 ;
     RECT  120.121 184.08 120.853 184.104 ;
     RECT  120.229 167.04 120.877 167.064 ;
     RECT  120.853 175.584 121.093 178.344 ;
     RECT  120.661 191.616 121.093 192.936 ;
     RECT  120.481 194.4 121.093 197.208 ;
     RECT  120.121 201.6 121.165 204.072 ;
     RECT  120.853 158.16 121.208 158.184 ;
     RECT  120.733 159.36 121.208 160.152 ;
     RECT  119.653 161.808 121.208 161.832 ;
     RECT  121.201 163.2 121.208 163.224 ;
     RECT  120.517 165.36 121.208 165.384 ;
     RECT  120.877 167.04 121.208 168.024 ;
     RECT  120.053 169.152 121.208 169.176 ;
     RECT  119.945 170.4 121.208 170.424 ;
     RECT  119.945 171.792 121.208 171.816 ;
     RECT  120.161 174.384 121.208 174.552 ;
     RECT  121.093 175.584 121.208 179.64 ;
     RECT  120.853 180.816 121.208 184.776 ;
     RECT  120.229 185.808 121.208 188.52 ;
     RECT  119.725 190.272 121.208 190.296 ;
     RECT  121.093 191.616 121.208 197.208 ;
     RECT  120.229 199.44 121.208 199.464 ;
     RECT  121.165 201.024 121.208 204.072 ;
     RECT  119.605 207.696 121.208 207.816 ;
     RECT  121.208 2.148 121.312 369.372 ;
     RECT  121.312 2.418 121.504 369.102 ;
     RECT  121.504 161.664 121.619 161.832 ;
     RECT  121.504 167.04 121.709 168.024 ;
     RECT  121.504 179.616 121.781 179.688 ;
     RECT  121.504 159.024 121.853 159.384 ;
     RECT  121.504 190.272 121.889 191.112 ;
     RECT  121.504 200.688 121.961 201.096 ;
     RECT  121.504 192.096 121.968 197.016 ;
     RECT  121.889 190.8 122.003 191.112 ;
     RECT  121.968 192.096 122.005 192.6 ;
     RECT  121.961 200.736 122.033 201.096 ;
     RECT  121.619 161.664 122.069 161.688 ;
     RECT  121.504 181.248 122.069 183.528 ;
     RECT  122.003 191.088 122.069 191.112 ;
     RECT  122.033 200.928 122.069 201.096 ;
     RECT  121.504 198.912 122.099 199.608 ;
     RECT  122.099 199.344 122.14 199.608 ;
     RECT  121.504 162.96 122.141 165.576 ;
     RECT  122.005 192.576 122.177 192.6 ;
     RECT  122.069 181.248 122.213 182.568 ;
     RECT  121.968 193.776 122.357 197.016 ;
     RECT  121.504 173.376 122.497 173.4 ;
     RECT  121.504 174.384 122.497 174.552 ;
     RECT  121.504 186.192 122.533 187.752 ;
     RECT  121.504 189.264 122.533 189.288 ;
     RECT  121.504 209.184 122.533 209.208 ;
     RECT  121.504 171.216 122.537 171.528 ;
     RECT  122.497 173.376 122.537 174.552 ;
     RECT  122.357 194.4 122.569 197.016 ;
     RECT  122.569 194.4 122.573 197.064 ;
     RECT  122.069 201.024 122.573 201.096 ;
     RECT  122.533 186.192 122.579 189.288 ;
     RECT  121.504 175.584 122.605 175.608 ;
     RECT  122.579 186.192 122.617 188.952 ;
     RECT  122.485 169.248 122.645 169.272 ;
     RECT  121.504 177.6 122.645 177.624 ;
     RECT  121.504 207.696 122.669 207.96 ;
     RECT  121.709 167.04 122.677 167.064 ;
     RECT  121.504 202.272 122.677 202.392 ;
     RECT  122.573 194.4 122.681 195.144 ;
     RECT  122.14 199.344 122.681 199.464 ;
     RECT  122.677 202.128 122.684 202.392 ;
     RECT  122.669 207.456 122.684 207.96 ;
     RECT  122.684 202.128 122.713 202.872 ;
     RECT  121.504 203.952 122.713 204.072 ;
     RECT  122.533 209.184 122.723 209.928 ;
     RECT  122.573 201.072 122.725 201.096 ;
     RECT  122.713 202.128 122.725 204.072 ;
     RECT  122.684 206.976 122.725 207.96 ;
     RECT  122.725 201.072 122.771 204.072 ;
     RECT  122.725 206.112 122.771 207.96 ;
     RECT  122.677 166.944 122.789 167.064 ;
     RECT  121.853 159.024 122.821 159.048 ;
     RECT  122.141 162.96 122.897 162.984 ;
     RECT  122.141 164.064 122.897 165.576 ;
     RECT  122.617 186.192 122.897 187.752 ;
     RECT  122.897 164.88 122.969 165.576 ;
     RECT  122.569 184.512 123.001 184.536 ;
     RECT  122.213 181.248 123.011 182.376 ;
     RECT  122.821 158.976 123.096 159.048 ;
     RECT  122.897 186.192 123.109 186.216 ;
     RECT  122.771 201.072 123.113 202.2 ;
     RECT  122.681 199.344 123.145 199.416 ;
     RECT  122.789 167.04 123.149 167.064 ;
     RECT  122.573 196.224 123.149 197.064 ;
     RECT  122.537 174.288 123.217 174.552 ;
     RECT  122.605 175.584 123.217 176.424 ;
     RECT  121.781 179.664 123.217 179.688 ;
     RECT  123.217 179.088 123.221 179.688 ;
     RECT  123.096 158.16 123.26 159.048 ;
     RECT  123.26 158.16 123.289 159.576 ;
     RECT  123.001 184.128 123.293 184.536 ;
     RECT  123.289 158.16 123.329 159.912 ;
     RECT  123.329 159.552 123.347 159.912 ;
     RECT  122.969 164.88 123.347 165.384 ;
     RECT  123.452 170.016 123.493 170.04 ;
     RECT  123.329 158.16 123.509 158.424 ;
     RECT  123.011 181.728 123.509 182.376 ;
     RECT  123.001 168.144 123.539 168.696 ;
     RECT  123.493 170.016 123.539 170.472 ;
     RECT  123.149 196.944 123.581 197.064 ;
     RECT  123.347 159.888 123.613 159.912 ;
     RECT  123.221 179.088 123.613 179.592 ;
     RECT  123.613 159.888 123.617 160.008 ;
     RECT  123.217 174.288 123.617 176.424 ;
     RECT  123.145 198.528 123.653 199.416 ;
     RECT  123.113 201.072 123.653 201.096 ;
     RECT  123.613 178.944 123.683 179.592 ;
     RECT  123.509 181.776 123.683 182.376 ;
     RECT  123.347 165.024 123.725 165.384 ;
     RECT  123.683 178.944 123.725 179.112 ;
     RECT  123.109 185.808 123.725 186.216 ;
     RECT  122.897 187.536 123.761 187.56 ;
     RECT  123.617 159.936 123.781 160.008 ;
     RECT  123.253 161.136 123.781 161.304 ;
     RECT  123.539 170.448 123.833 170.472 ;
     RECT  123.617 175.008 123.833 176.424 ;
     RECT  123.781 159.936 123.868 161.688 ;
     RECT  122.723 209.904 123.937 209.928 ;
     RECT  122.771 203.472 124.009 203.496 ;
     RECT  123.868 159.936 124.085 161.016 ;
     RECT  122.771 206.112 124.153 206.136 ;
     RECT  122.771 207.696 124.153 207.96 ;
     RECT  124.153 206.112 124.193 207.96 ;
     RECT  123.683 182.352 124.265 182.376 ;
     RECT  123.937 209.28 124.265 209.928 ;
     RECT  123.113 202.176 124.337 202.2 ;
     RECT  123.833 175.008 124.445 176.184 ;
     RECT  122.681 194.976 124.513 195.144 ;
     RECT  123.293 184.128 124.621 184.152 ;
     RECT  124.513 194.88 124.645 195.144 ;
     RECT  123.581 196.944 124.645 196.968 ;
     RECT  123.539 168.144 124.657 168.168 ;
     RECT  124.621 184.128 124.661 184.68 ;
     RECT  124.652 181.248 124.693 181.272 ;
     RECT  124.657 168.048 124.697 168.168 ;
     RECT  122.617 188.928 124.697 188.952 ;
     RECT  124.265 209.28 124.697 209.304 ;
     RECT  123.725 165.024 124.729 165.048 ;
     RECT  124.693 181.248 124.739 181.848 ;
     RECT  124.189 198.48 124.765 198.504 ;
     RECT  124.189 166.944 124.796 166.968 ;
     RECT  123.509 158.4 124.801 158.424 ;
     RECT  124.765 198.48 124.801 198.696 ;
     RECT  123.729 163.008 124.837 163.032 ;
     RECT  124.009 203.472 124.837 203.544 ;
     RECT  124.645 194.88 124.844 196.968 ;
     RECT  124.796 166.32 124.883 166.968 ;
     RECT  124.801 198.288 124.885 198.696 ;
     RECT  124.844 194.88 124.931 197.256 ;
     RECT  124.885 198.288 124.933 198.936 ;
     RECT  124.621 200.16 124.933 200.616 ;
     RECT  124.837 203.472 124.933 204.216 ;
     RECT  124.933 198.288 124.979 200.616 ;
     RECT  124.933 202.752 124.979 204.216 ;
     RECT  123.217 192.048 124.981 192.072 ;
     RECT  124.189 193.632 124.981 193.656 ;
     RECT  124.931 194.88 124.985 196.968 ;
     RECT  124.979 202.752 125.02 202.776 ;
     RECT  124.445 175.296 125.021 176.184 ;
     RECT  124.193 206.928 125.021 207.96 ;
     RECT  124.657 171.744 125.077 171.768 ;
     RECT  125.077 170.976 125.123 171.768 ;
     RECT  125.021 207.696 125.123 207.96 ;
     RECT  124.225 186.912 125.132 186.936 ;
     RECT  124.729 187.968 125.132 187.992 ;
     RECT  124.801 158.4 125.161 158.712 ;
     RECT  124.883 166.944 125.161 166.968 ;
     RECT  124.697 168.048 125.161 168.072 ;
     RECT  123.725 185.808 125.161 185.832 ;
     RECT  125.123 170.976 125.165 171 ;
     RECT  124.985 196.944 125.165 196.968 ;
     RECT  124.933 201.744 125.165 201.768 ;
     RECT  125.077 210.336 125.165 210.36 ;
     RECT  124.981 192.048 125.267 193.656 ;
     RECT  125.228 217.92 125.269 217.944 ;
     RECT  124.985 194.88 125.273 195.912 ;
     RECT  124.729 182.928 125.276 182.952 ;
     RECT  125.269 217.92 125.315 218.328 ;
     RECT  124.661 184.656 125.317 184.68 ;
     RECT  125.161 185.712 125.317 185.832 ;
     RECT  124.085 159.984 125.345 161.016 ;
     RECT  125.276 182.928 125.363 183.288 ;
     RECT  125.345 160.128 125.377 161.016 ;
     RECT  125.161 166.944 125.381 168.072 ;
     RECT  123.164 173.232 125.381 173.256 ;
     RECT  125.021 175.296 125.381 175.848 ;
     RECT  125.161 157.44 125.413 158.712 ;
     RECT  124.837 163.008 125.413 163.368 ;
     RECT  125.413 156.72 125.459 158.712 ;
     RECT  125.413 162.432 125.459 163.368 ;
     RECT  123.725 178.944 125.509 178.968 ;
     RECT  124.979 198.288 125.525 200.184 ;
     RECT  125.509 178.416 125.555 178.968 ;
     RECT  125.267 192.048 125.555 192.072 ;
     RECT  125.459 162.432 125.561 162.456 ;
     RECT  124.729 164.736 125.561 165.048 ;
     RECT  125.555 178.416 125.596 178.44 ;
     RECT  125.509 190.992 125.596 191.016 ;
     RECT  125.459 158.016 125.597 158.712 ;
     RECT  125.132 186.912 125.917 187.992 ;
     RECT  124.979 204.192 125.953 204.216 ;
     RECT  125.123 207.792 125.989 207.96 ;
     RECT  124.693 214.704 125.989 214.728 ;
     RECT  125.317 184.656 126.025 185.832 ;
     RECT  125.485 201.312 126.025 201.336 ;
     RECT  124.621 211.824 126.061 211.848 ;
     RECT  124.739 181.824 126.097 181.848 ;
     RECT  126.025 196.896 126.241 196.92 ;
     RECT  125.525 198.288 126.241 199.416 ;
     RECT  126.205 223.392 126.277 223.416 ;
     RECT  126.061 226.32 126.277 226.344 ;
     RECT  126.097 181.824 126.457 182.376 ;
     RECT  125.845 177.264 126.529 177.288 ;
     RECT  125.917 189.36 126.529 189.384 ;
     RECT  126.133 202.944 126.565 202.968 ;
     RECT  125.459 156.72 126.608 156.744 ;
     RECT  125.597 158.688 126.608 158.712 ;
     RECT  125.377 160.128 126.608 161.304 ;
     RECT  125.561 165.024 126.608 165.048 ;
     RECT  125.381 166.944 126.608 167.88 ;
     RECT  125.381 175.824 126.608 175.848 ;
     RECT  126.529 177.264 126.608 177.336 ;
     RECT  126.457 181.536 126.608 182.376 ;
     RECT  126.025 184.224 126.608 185.832 ;
     RECT  125.917 186.912 126.608 188.04 ;
     RECT  126.529 189.072 126.608 189.384 ;
     RECT  126.061 191.232 126.608 191.256 ;
     RECT  125.557 194.256 126.608 194.28 ;
     RECT  125.273 195.888 126.608 195.912 ;
     RECT  126.241 196.896 126.608 199.416 ;
     RECT  126.025 200.688 126.608 201.336 ;
     RECT  126.565 202.896 126.608 202.968 ;
     RECT  125.953 204.192 126.608 205.032 ;
     RECT  125.989 206.64 126.608 206.664 ;
     RECT  125.989 207.792 126.608 208.584 ;
     RECT  125.629 209.712 126.608 209.736 ;
     RECT  126.061 211.488 126.608 211.848 ;
     RECT  124.621 213.072 126.608 213.096 ;
     RECT  125.989 214.32 126.608 214.728 ;
     RECT  125.315 218.304 126.608 218.328 ;
     RECT  126.269 222.24 126.608 222.264 ;
     RECT  126.277 223.392 126.608 223.704 ;
     RECT  126.277 225.024 126.608 226.344 ;
     RECT  126.608 2.148 126.712 369.372 ;
     RECT  126.712 2.418 126.904 369.102 ;
     RECT  126.904 194.256 127.001 195.912 ;
     RECT  126.904 187.728 127.037 188.136 ;
     RECT  126.904 196.896 127.043 200.712 ;
     RECT  126.904 212.496 127.091 214.728 ;
     RECT  126.904 189.36 127.109 189.432 ;
     RECT  126.904 225.792 127.109 226.872 ;
     RECT  127.091 212.496 127.132 214.536 ;
     RECT  126.904 181.488 127.145 181.656 ;
     RECT  127.132 214.224 127.181 214.536 ;
     RECT  126.904 204.192 127.397 205.848 ;
     RECT  127.397 205.2 127.427 205.848 ;
     RECT  127.001 194.256 127.571 195.72 ;
     RECT  127.043 196.896 127.649 200.232 ;
     RECT  126.904 172.128 127.685 172.152 ;
     RECT  126.904 184.944 127.715 186.12 ;
     RECT  126.904 211.488 127.721 211.512 ;
     RECT  126.904 217.728 127.721 219.576 ;
     RECT  126.904 207.504 127.757 208.632 ;
     RECT  127.715 185.472 127.859 186.12 ;
     RECT  127.649 196.896 127.865 199.08 ;
     RECT  126.904 169.248 127.901 169.272 ;
     RECT  126.904 179.04 127.909 179.064 ;
     RECT  126.904 215.856 127.933 215.88 ;
     RECT  127.145 181.488 127.955 181.512 ;
     RECT  126.904 182.832 127.955 183.432 ;
     RECT  126.904 202.128 127.964 202.968 ;
     RECT  127.859 185.76 128.005 186.12 ;
     RECT  127.037 187.968 128.005 188.136 ;
     RECT  127.649 200.208 128.005 200.232 ;
     RECT  127.964 201.744 128.005 202.968 ;
     RECT  128.005 185.76 128.051 188.136 ;
     RECT  127.757 207.504 128.051 208.296 ;
     RECT  127.721 217.728 128.051 219.048 ;
     RECT  126.904 175.824 128.077 177.336 ;
     RECT  126.904 161.808 128.081 162.504 ;
     RECT  126.904 223.68 128.081 223.704 ;
     RECT  128.005 200.208 128.089 202.968 ;
     RECT  128.077 175.536 128.113 177.336 ;
     RECT  127.909 178.368 128.113 179.064 ;
     RECT  128.089 200.208 128.117 202.92 ;
     RECT  128.081 161.808 128.153 162.264 ;
     RECT  126.904 165.024 128.221 165.048 ;
     RECT  128.005 222.336 128.221 222.36 ;
     RECT  127.132 212.496 128.245 212.616 ;
     RECT  128.245 212.496 128.261 213.192 ;
     RECT  128.113 175.536 128.291 179.064 ;
     RECT  127.181 214.512 128.291 214.536 ;
     RECT  128.005 180.24 128.297 180.264 ;
     RECT  128.051 185.76 128.297 188.088 ;
     RECT  127.571 194.4 128.297 195.72 ;
     RECT  128.291 175.536 128.329 176.904 ;
     RECT  128.221 222.24 128.329 222.36 ;
     RECT  128.261 212.592 128.332 213.192 ;
     RECT  126.904 220.704 128.333 221.112 ;
     RECT  128.051 207.504 128.365 208.056 ;
     RECT  128.365 207.168 128.435 208.056 ;
     RECT  126.904 191.088 128.509 192.072 ;
     RECT  128.117 201.168 128.585 202.92 ;
     RECT  126.904 167.808 128.621 167.832 ;
     RECT  128.291 178.368 128.621 179.064 ;
     RECT  128.221 165.024 128.627 165.336 ;
     RECT  127.109 226.32 128.636 226.872 ;
     RECT  128.329 174.96 128.675 176.904 ;
     RECT  127.109 189.408 128.689 189.432 ;
     RECT  128.689 189.408 128.693 189.912 ;
     RECT  127.933 215.856 128.725 216.024 ;
     RECT  128.677 229.152 128.801 229.176 ;
     RECT  128.675 174.96 128.831 176.712 ;
     RECT  128.333 221.088 128.873 221.112 ;
     RECT  128.329 222.096 128.977 222.36 ;
     RECT  128.833 181.824 129.017 181.848 ;
     RECT  127.397 204.192 129.017 204.216 ;
     RECT  128.581 163.872 129.049 163.896 ;
     RECT  128.627 165.024 129.049 165.288 ;
     RECT  128.545 180.768 129.049 180.792 ;
     RECT  128.977 221.76 129.053 222.36 ;
     RECT  128.153 162.24 129.085 162.264 ;
     RECT  128.051 217.728 129.121 217.752 ;
     RECT  129.049 180.768 129.125 181.128 ;
     RECT  128.297 194.4 129.155 194.472 ;
     RECT  127.865 197.184 129.161 199.08 ;
     RECT  128.509 190.896 129.185 192.072 ;
     RECT  129.109 193.2 129.185 193.224 ;
     RECT  128.221 171.504 129.193 171.528 ;
     RECT  126.904 210.336 129.193 210.36 ;
     RECT  129.053 221.76 129.197 222.264 ;
     RECT  128.297 195.504 129.205 195.72 ;
     RECT  127.427 205.2 129.229 205.224 ;
     RECT  129.193 171.504 129.233 172.152 ;
     RECT  129.185 190.896 129.233 193.224 ;
     RECT  128.585 201.168 129.233 202.824 ;
     RECT  128.761 153.36 129.251 153.384 ;
     RECT  129.233 191.088 129.251 193.224 ;
     RECT  129.161 198.288 129.26 199.08 ;
     RECT  129.251 192.72 129.269 193.224 ;
     RECT  129.193 210.336 129.269 210.84 ;
     RECT  129.205 150.864 129.292 150.888 ;
     RECT  128.621 178.368 129.301 178.968 ;
     RECT  129.269 210.816 129.301 210.84 ;
     RECT  129.301 177.792 129.305 178.968 ;
     RECT  129.301 156.72 129.337 156.744 ;
     RECT  129.233 201.168 129.337 202.296 ;
     RECT  128.831 174.192 129.349 176.712 ;
     RECT  128.297 185.76 129.373 186.12 ;
     RECT  128.297 187.728 129.373 188.088 ;
     RECT  129.125 181.104 129.377 181.128 ;
     RECT  129.233 171.552 129.395 172.152 ;
     RECT  129.349 173.424 129.395 176.712 ;
     RECT  129.193 231.984 129.395 232.008 ;
     RECT  129.085 162.24 129.404 162.456 ;
     RECT  129.205 195.504 129.413 197.16 ;
     RECT  129.337 156.576 129.445 156.744 ;
     RECT  128.332 212.592 129.449 212.616 ;
     RECT  129.26 198.288 129.485 199.464 ;
     RECT  129.121 217.152 129.485 217.752 ;
     RECT  129.155 194.448 129.517 194.472 ;
     RECT  129.373 185.76 129.557 188.088 ;
     RECT  129.349 230.304 129.557 230.808 ;
     RECT  129.157 208.608 129.589 208.632 ;
     RECT  129.548 209.808 129.589 209.832 ;
     RECT  128.636 226.32 129.589 227.544 ;
     RECT  129.485 198.864 129.629 199.464 ;
     RECT  129.589 208.608 129.635 209.832 ;
     RECT  129.409 223.584 129.635 225.048 ;
     RECT  129.589 226.32 129.635 227.688 ;
     RECT  129.517 194.448 129.665 194.616 ;
     RECT  129.404 162.24 129.685 162.744 ;
     RECT  129.665 194.592 129.737 194.616 ;
     RECT  129.229 204.24 129.773 205.224 ;
     RECT  129.773 204.24 129.779 204.84 ;
     RECT  129.085 184.656 129.805 184.68 ;
     RECT  129.557 185.76 129.805 187.08 ;
     RECT  129.805 184.656 129.877 187.08 ;
     RECT  129.685 161.808 129.913 162.744 ;
     RECT  129.049 163.872 129.913 165.288 ;
     RECT  129.395 173.424 129.917 173.448 ;
     RECT  129.413 195.696 129.917 197.16 ;
     RECT  129.635 208.608 129.917 209.208 ;
     RECT  129.557 188.064 129.985 188.088 ;
     RECT  128.725 215.76 129.985 216.024 ;
     RECT  129.445 156.048 129.989 156.744 ;
     RECT  129.985 215.76 130.021 216.072 ;
     RECT  130.021 215.376 130.108 216.072 ;
     RECT  128.689 158.4 130.124 158.424 ;
     RECT  129.697 159.6 130.124 159.624 ;
     RECT  129.913 161.808 130.169 165.432 ;
     RECT  129.395 171.552 130.201 171.576 ;
     RECT  129.629 199.056 130.201 199.464 ;
     RECT  130.124 158.4 130.211 159.624 ;
     RECT  129.301 210.816 130.309 211.512 ;
     RECT  130.165 212.496 130.309 212.52 ;
     RECT  128.435 207.168 130.313 207.24 ;
     RECT  130.309 210.816 130.313 212.52 ;
     RECT  129.557 230.784 130.313 230.808 ;
     RECT  130.169 164.832 130.349 165.432 ;
     RECT  130.108 215.808 130.349 216.072 ;
     RECT  129.697 219.888 130.349 219.912 ;
     RECT  129.121 154.992 130.417 155.016 ;
     RECT  129.989 156.048 130.417 156.6 ;
     RECT  129.251 191.088 130.417 191.112 ;
     RECT  129.635 223.584 130.421 224.712 ;
     RECT  130.421 224.304 130.444 224.712 ;
     RECT  129.337 200.928 130.453 202.296 ;
     RECT  130.417 191.088 130.489 191.544 ;
     RECT  129.917 196.656 130.489 197.16 ;
     RECT  130.211 159.6 130.501 159.624 ;
     RECT  130.201 166.8 130.525 166.824 ;
     RECT  130.489 191.088 130.525 191.64 ;
     RECT  130.169 161.808 130.529 163.032 ;
     RECT  130.201 170.736 130.529 171.576 ;
     RECT  130.501 159.6 130.547 160.2 ;
     RECT  130.529 161.808 130.549 161.832 ;
     RECT  130.525 166.8 130.549 167.016 ;
     RECT  130.349 165.072 130.561 165.432 ;
     RECT  130.549 166.704 130.561 167.016 ;
     RECT  128.693 189.888 130.561 189.912 ;
     RECT  130.525 190.992 130.561 191.64 ;
     RECT  129.697 168.72 130.595 169.368 ;
     RECT  130.525 153.888 130.597 153.912 ;
     RECT  130.417 154.992 130.597 156.6 ;
     RECT  130.561 214.224 130.597 214.248 ;
     RECT  130.201 199.056 130.633 199.56 ;
     RECT  130.597 214.128 130.633 214.248 ;
     RECT  129.229 182.832 130.637 182.856 ;
     RECT  130.313 210.816 130.673 212.376 ;
     RECT  130.673 211.488 130.745 212.376 ;
     RECT  129.635 227.664 130.748 227.688 ;
     RECT  130.597 153.888 130.78 156.6 ;
     RECT  130.777 237.744 130.813 237.768 ;
     RECT  130.561 165.072 130.817 167.016 ;
     RECT  130.745 211.488 130.817 212.136 ;
     RECT  130.748 227.664 130.817 228.552 ;
     RECT  130.549 161.328 130.835 161.832 ;
     RECT  129.395 174.912 130.835 176.712 ;
     RECT  130.817 228.528 130.835 228.552 ;
     RECT  130.211 158.4 130.853 158.424 ;
     RECT  130.817 165.072 130.853 166.824 ;
     RECT  130.844 144.096 130.885 144.12 ;
     RECT  130.844 145.536 130.885 145.56 ;
     RECT  130.633 213.744 130.885 214.248 ;
     RECT  130.78 153.888 130.889 155.448 ;
     RECT  130.444 224.304 130.889 224.568 ;
     RECT  130.885 144.096 130.931 145.56 ;
     RECT  130.529 170.736 130.957 170.76 ;
     RECT  130.789 229.632 130.957 229.656 ;
     RECT  130.489 196.656 130.981 197.208 ;
     RECT  130.561 189.888 130.993 192.6 ;
     RECT  130.981 196.08 131.021 197.208 ;
     RECT  130.453 200.928 131.029 202.344 ;
     RECT  129.877 183.984 131.065 187.08 ;
     RECT  129.985 188.064 131.065 188.376 ;
     RECT  129.485 217.152 131.065 217.176 ;
     RECT  131.029 200.928 131.077 202.44 ;
     RECT  130.78 156.432 131.101 156.6 ;
     RECT  131.021 195.504 131.101 197.208 ;
     RECT  130.381 207.456 131.137 207.864 ;
     RECT  129.917 209.184 131.137 209.208 ;
     RECT  129.197 221.76 131.137 221.784 ;
     RECT  130.993 189.888 131.209 194.184 ;
     RECT  130.595 169.344 131.281 169.368 ;
     RECT  130.957 170.448 131.281 170.76 ;
     RECT  131.101 195.504 131.317 197.64 ;
     RECT  131.209 173.76 131.353 173.784 ;
     RECT  130.835 174.912 131.353 175.848 ;
     RECT  131.209 189.6 131.353 194.184 ;
     RECT  130.349 216.048 131.42 216.072 ;
     RECT  131.065 217.152 131.42 218.088 ;
     RECT  131.353 189.504 131.425 194.184 ;
     RECT  131.317 195.504 131.425 197.832 ;
     RECT  130.669 146.64 131.461 146.664 ;
     RECT  129.305 177.792 131.497 178.392 ;
     RECT  130.813 237.36 131.497 237.768 ;
     RECT  129.779 204.24 131.533 204.264 ;
     RECT  131.137 231.936 131.605 232.392 ;
     RECT  131.461 146.64 131.641 147.048 ;
     RECT  131.173 205.824 131.641 205.848 ;
     RECT  131.065 183.984 131.701 188.376 ;
     RECT  131.425 189.504 131.713 197.832 ;
     RECT  131.641 205.824 131.749 206.472 ;
     RECT  131.137 207.456 131.749 209.208 ;
     RECT  131.077 235.392 131.749 235.416 ;
     RECT  131.701 183.84 131.797 188.376 ;
     RECT  131.797 183.792 131.821 188.376 ;
     RECT  131.713 189.36 131.821 197.832 ;
     RECT  130.633 199.056 131.821 199.656 ;
     RECT  131.497 177.792 131.857 179.112 ;
     RECT  130.885 180.72 131.857 181.224 ;
     RECT  131.42 216.048 131.857 218.088 ;
     RECT  131.797 220.752 131.857 220.776 ;
     RECT  131.641 151.536 131.893 151.56 ;
     RECT  130.853 165.168 131.893 166.824 ;
     RECT  131.749 168.24 131.893 168.264 ;
     RECT  131.821 183.216 131.893 188.376 ;
     RECT  131.713 210.288 131.893 210.312 ;
     RECT  130.817 211.488 131.893 212.04 ;
     RECT  131.641 146.4 131.965 147.048 ;
     RECT  131.893 210.288 131.965 212.04 ;
     RECT  130.885 213.744 131.965 214.344 ;
     RECT  130.931 144.816 132.008 144.84 ;
     RECT  131.965 146.16 132.008 147.048 ;
     RECT  131.893 148.32 132.008 148.344 ;
     RECT  131.893 149.76 132.008 149.784 ;
     RECT  131.893 150.816 132.008 151.56 ;
     RECT  131.389 152.688 132.008 152.712 ;
     RECT  130.889 154.8 132.008 155.448 ;
     RECT  131.101 156.432 132.008 156.792 ;
     RECT  130.547 160.176 132.008 160.2 ;
     RECT  130.835 161.568 132.008 161.832 ;
     RECT  130.529 163.008 132.008 163.032 ;
     RECT  131.893 165.168 132.008 168.264 ;
     RECT  131.281 169.344 132.008 170.76 ;
     RECT  130.849 171.792 132.008 171.816 ;
     RECT  131.353 172.992 132.008 175.848 ;
     RECT  131.857 177.792 132.008 181.224 ;
     RECT  131.893 182.928 132.008 188.376 ;
     RECT  131.821 189.36 132.008 199.656 ;
     RECT  131.077 200.928 132.008 202.728 ;
     RECT  131.533 203.952 132.008 204.264 ;
     RECT  131.749 205.824 132.008 209.208 ;
     RECT  131.965 210.24 132.008 212.04 ;
     RECT  131.965 213.168 132.008 214.344 ;
     RECT  131.857 216.048 132.008 218.328 ;
     RECT  131.857 219.552 132.008 220.776 ;
     RECT  131.137 221.76 132.008 222.168 ;
     RECT  130.889 224.448 132.008 224.568 ;
     RECT  129.635 226.32 132.008 226.344 ;
     RECT  130.957 229.632 132.008 230.52 ;
     RECT  131.605 231.936 132.008 232.92 ;
     RECT  129.877 233.904 132.008 233.928 ;
     RECT  131.749 235.344 132.008 235.416 ;
     RECT  131.497 237.36 132.008 238.488 ;
     RECT  129.949 239.952 132.008 239.976 ;
     RECT  130.525 242.256 132.008 242.28 ;
     RECT  132.008 2.148 132.112 369.372 ;
     RECT  132.133 371.376 132.229 371.4 ;
     RECT  132.112 2.418 132.304 369.102 ;
     RECT  132.304 146.4 132.365 147.048 ;
     RECT  132.304 151.584 132.419 151.608 ;
     RECT  132.304 174.96 132.419 197.784 ;
     RECT  132.419 174.96 132.445 178.392 ;
     RECT  132.229 371.088 132.467 371.4 ;
     RECT  132.467 371.184 132.509 371.4 ;
     RECT  132.304 243.36 132.563 243.384 ;
     RECT  132.509 371.232 132.563 371.4 ;
     RECT  132.419 179.616 132.581 197.784 ;
     RECT  132.581 179.616 132.761 196.2 ;
     RECT  132.304 205.824 132.833 206.712 ;
     RECT  132.304 143.28 132.851 144.264 ;
     RECT  132.365 146.496 132.877 147.048 ;
     RECT  132.851 143.28 132.941 143.304 ;
     RECT  132.761 179.952 132.941 196.2 ;
     RECT  132.304 224.448 132.941 226.344 ;
     RECT  132.304 212.496 132.947 214.44 ;
     RECT  132.304 227.424 132.995 230.28 ;
     RECT  132.304 140.736 133.049 141.336 ;
     RECT  132.995 227.424 133.049 227.448 ;
     RECT  132.941 194.4 133.085 196.2 ;
     RECT  132.304 208.032 133.121 211.224 ;
     RECT  132.304 241.68 133.139 241.704 ;
     RECT  132.304 164.88 133.157 170.808 ;
     RECT  132.304 240.48 133.18 240.648 ;
     RECT  132.304 156.432 133.193 156.456 ;
     RECT  132.941 179.952 133.193 193.176 ;
     RECT  132.304 216.624 133.229 220.008 ;
     RECT  132.304 234.048 133.235 239.208 ;
     RECT  133.157 164.88 133.265 168.072 ;
     RECT  133.235 234.048 133.276 235.128 ;
     RECT  132.304 158.928 133.285 159.432 ;
     RECT  132.304 161.568 133.285 162.456 ;
     RECT  132.304 200.784 133.297 203.352 ;
     RECT  132.941 224.448 133.297 226.296 ;
     RECT  132.304 231.408 133.297 232.392 ;
     RECT  133.276 234.048 133.309 234.888 ;
     RECT  132.304 163.536 133.331 163.56 ;
     RECT  133.157 169.056 133.333 170.808 ;
     RECT  133.297 224.016 133.333 226.296 ;
     RECT  132.304 152.688 133.369 155.448 ;
     RECT  133.285 161.52 133.369 162.456 ;
     RECT  133.285 158.256 133.372 159.432 ;
     RECT  133.049 140.736 133.445 140.76 ;
     RECT  133.235 236.928 133.445 239.208 ;
     RECT  133.18 240.528 133.445 240.648 ;
     RECT  133.369 152.688 133.481 156.168 ;
     RECT  133.085 194.4 133.481 195.576 ;
     RECT  133.333 223.392 133.481 226.296 ;
     RECT  133.333 169.056 133.513 171.576 ;
     RECT  133.297 200.784 133.513 203.4 ;
     RECT  133.481 195.552 133.517 195.576 ;
     RECT  132.445 174.96 133.549 178.056 ;
     RECT  133.229 216.624 133.585 218.808 ;
     RECT  132.304 198.96 133.621 199.8 ;
     RECT  132.833 206.352 133.621 206.712 ;
     RECT  132.947 213.936 133.621 214.44 ;
     RECT  132.581 197.184 133.628 197.784 ;
     RECT  132.877 147.024 133.657 147.048 ;
     RECT  132.304 148.224 133.657 148.248 ;
     RECT  133.481 223.392 133.661 224.184 ;
     RECT  133.369 161.424 133.693 162.456 ;
     RECT  133.121 208.56 133.717 211.224 ;
     RECT  132.304 173.52 133.729 173.784 ;
     RECT  133.549 174.96 133.729 178.392 ;
     RECT  133.628 196.656 133.765 197.784 ;
     RECT  133.621 198.864 133.765 199.8 ;
     RECT  133.717 208.56 133.801 211.512 ;
     RECT  132.947 212.496 133.801 212.76 ;
     RECT  133.765 196.656 133.805 199.8 ;
     RECT  133.513 200.784 133.805 204.168 ;
     RECT  132.304 222.096 133.82 222.12 ;
     RECT  133.729 173.52 133.837 178.392 ;
     RECT  133.481 194.4 133.841 194.568 ;
     RECT  133.657 147.024 133.868 148.248 ;
     RECT  132.304 149.76 133.873 149.784 ;
     RECT  133.841 194.4 133.877 194.472 ;
     RECT  133.585 216.144 133.907 218.808 ;
     RECT  133.82 221.712 133.907 222.12 ;
     RECT  133.549 144.72 133.909 144.744 ;
     RECT  133.873 149.616 133.909 149.784 ;
     RECT  133.909 143.76 133.913 144.744 ;
     RECT  133.193 180.48 133.916 193.176 ;
     RECT  133.877 194.4 133.916 194.424 ;
     RECT  133.868 146.496 133.945 148.248 ;
     RECT  133.909 149.616 133.945 149.832 ;
     RECT  133.801 208.56 133.945 212.76 ;
     RECT  133.621 213.936 133.945 214.824 ;
     RECT  133.309 234.048 133.945 234.072 ;
     RECT  133.945 146.496 133.955 149.832 ;
     RECT  133.372 158.928 133.981 159.432 ;
     RECT  133.907 217.92 133.985 218.808 ;
     RECT  133.481 225.168 133.985 226.296 ;
     RECT  133.916 180.48 134.003 194.424 ;
     RECT  133.549 205.152 134.005 205.176 ;
     RECT  133.621 206.352 134.005 206.808 ;
     RECT  133.445 236.928 134.021 239.16 ;
     RECT  132.563 371.376 134.021 371.4 ;
     RECT  133.229 219.984 134.053 220.008 ;
     RECT  133.945 208.56 134.089 214.824 ;
     RECT  134.053 219.984 134.093 220.68 ;
     RECT  134.089 208.032 134.099 214.824 ;
     RECT  133.297 231.312 134.101 232.392 ;
     RECT  133.945 233.904 134.101 234.072 ;
     RECT  133.981 158.928 134.125 159.864 ;
     RECT  134.005 205.152 134.161 206.808 ;
     RECT  134.099 208.032 134.161 213.144 ;
     RECT  133.955 147.024 134.165 149.832 ;
     RECT  134.101 231.312 134.188 234.072 ;
     RECT  134.021 237.84 134.195 239.16 ;
     RECT  134.125 158.928 134.197 160.152 ;
     RECT  134.099 214.128 134.197 214.824 ;
     RECT  133.907 216.144 134.197 216.888 ;
     RECT  134.003 180.48 134.201 193.176 ;
     RECT  134.003 194.304 134.201 194.424 ;
     RECT  134.053 152.16 134.233 152.184 ;
     RECT  134.188 231.312 134.233 232.152 ;
     RECT  134.161 205.152 134.237 213.144 ;
     RECT  132.995 228.576 134.243 230.28 ;
     RECT  134.195 238.272 134.243 239.16 ;
     RECT  133.513 169.056 134.309 172.392 ;
     RECT  134.197 158.928 134.341 160.2 ;
     RECT  134.201 180.48 134.341 184.68 ;
     RECT  134.165 147.024 134.381 148.968 ;
     RECT  133.481 153.36 134.417 156.168 ;
     RECT  134.237 205.152 134.435 208.632 ;
     RECT  133.265 164.88 134.485 165.288 ;
     RECT  133.265 166.272 134.485 167.784 ;
     RECT  133.693 161.424 134.521 163.416 ;
     RECT  133.837 173.52 134.525 178.92 ;
     RECT  134.341 157.968 134.561 160.2 ;
     RECT  134.237 209.616 134.561 213.144 ;
     RECT  133.805 197.28 134.593 199.8 ;
     RECT  134.188 233.136 134.593 234.072 ;
     RECT  134.435 206.448 134.597 208.632 ;
     RECT  134.561 209.616 134.597 213 ;
     RECT  134.521 161.424 134.605 163.704 ;
     RECT  133.985 218.784 134.633 218.808 ;
     RECT  134.593 233.136 134.633 234.168 ;
     RECT  134.233 151.584 134.669 152.184 ;
     RECT  133.805 201.456 134.745 204.168 ;
     RECT  134.435 205.152 134.745 205.224 ;
     RECT  134.417 153.888 134.777 156.168 ;
     RECT  134.233 231.264 134.777 232.152 ;
     RECT  133.477 142.32 134.809 142.344 ;
     RECT  134.341 179.904 134.813 184.68 ;
     RECT  134.197 214.128 134.813 216.888 ;
     RECT  134.745 201.456 134.819 205.224 ;
     RECT  134.485 164.88 134.845 167.784 ;
     RECT  134.309 170.256 134.845 172.392 ;
     RECT  134.593 197.28 134.845 199.896 ;
     RECT  134.093 220.656 134.845 220.68 ;
     RECT  134.809 142.32 134.869 142.776 ;
     RECT  133.661 223.92 134.876 224.184 ;
     RECT  134.381 148.224 134.885 148.968 ;
     RECT  134.381 147.024 134.915 147.048 ;
     RECT  134.885 148.8 134.915 148.968 ;
     RECT  134.561 157.968 134.917 160.152 ;
     RECT  134.845 196.368 134.917 199.896 ;
     RECT  134.819 201.456 134.917 205.176 ;
     RECT  134.876 223.632 134.917 224.184 ;
     RECT  134.845 164.88 134.921 167.88 ;
     RECT  134.633 234.144 134.924 234.168 ;
     RECT  134.921 166.416 134.957 167.88 ;
     RECT  134.777 153.936 134.963 156.168 ;
     RECT  134.243 228.576 134.997 229.128 ;
     RECT  134.917 157.296 135.004 160.152 ;
     RECT  134.924 234.144 135.011 235.128 ;
     RECT  133.907 222.096 135.025 222.12 ;
     RECT  135.025 222.096 135.061 222.216 ;
     RECT  134.917 223.632 135.061 224.328 ;
     RECT  133.985 225.504 135.061 226.296 ;
     RECT  134.869 141.696 135.065 142.776 ;
     RECT  134.997 228.192 135.101 229.128 ;
     RECT  134.917 196.08 135.119 205.176 ;
     RECT  134.605 161.424 135.133 163.032 ;
     RECT  134.597 206.592 135.137 208.632 ;
     RECT  134.201 194.4 135.169 194.424 ;
     RECT  135.119 195.84 135.173 205.176 ;
     RECT  135.004 157.872 135.209 160.152 ;
     RECT  135.061 223.632 135.209 226.296 ;
     RECT  135.065 141.696 135.241 142.344 ;
     RECT  134.525 173.76 135.241 178.92 ;
     RECT  134.813 179.904 135.241 180.696 ;
     RECT  134.243 238.272 135.241 238.488 ;
     RECT  134.201 185.664 135.253 193.176 ;
     RECT  135.209 224.832 135.281 226.296 ;
     RECT  135.061 221.856 135.301 222.216 ;
     RECT  135.209 223.632 135.301 223.752 ;
     RECT  134.557 236.352 135.349 236.376 ;
     RECT  134.669 151.584 135.389 152.04 ;
     RECT  135.301 221.856 135.389 223.752 ;
     RECT  135.241 237.696 135.395 238.488 ;
     RECT  133.913 143.76 135.404 144.264 ;
     RECT  135.253 185.664 135.421 193.32 ;
     RECT  135.169 194.4 135.421 194.664 ;
     RECT  134.243 230.16 135.421 230.184 ;
     RECT  135.404 143.76 135.445 144.504 ;
     RECT  134.309 169.056 135.457 169.224 ;
     RECT  134.845 170.256 135.457 172.68 ;
     RECT  135.395 238.272 135.457 238.488 ;
     RECT  135.445 143.664 135.491 144.504 ;
     RECT  135.457 169.056 135.493 172.68 ;
     RECT  135.241 173.76 135.493 180.696 ;
     RECT  134.813 214.512 135.497 216.888 ;
     RECT  135.421 185.664 135.505 194.664 ;
     RECT  132.304 276.144 135.533 276.168 ;
     RECT  135.241 141.312 135.569 142.344 ;
     RECT  135.173 195.84 135.569 204.84 ;
     RECT  134.777 232.128 135.569 232.152 ;
     RECT  135.209 157.872 135.605 158.712 ;
     RECT  134.813 181.776 135.641 184.68 ;
     RECT  135.505 194.448 135.641 194.664 ;
     RECT  135.641 194.64 135.665 194.664 ;
     RECT  135.569 195.84 135.665 196.152 ;
     RECT  135.209 159.84 135.673 160.152 ;
     RECT  135.133 161.28 135.673 163.032 ;
     RECT  135.137 207.696 135.685 208.632 ;
     RECT  134.597 209.616 135.685 212.616 ;
     RECT  135.641 181.824 135.709 184.68 ;
     RECT  135.505 185.664 135.709 193.176 ;
     RECT  135.665 194.64 135.713 196.152 ;
     RECT  134.845 220.656 135.749 220.728 ;
     RECT  135.349 236.352 135.749 236.424 ;
     RECT  135.457 146.112 135.821 146.376 ;
     RECT  135.605 157.872 135.821 158.616 ;
     RECT  135.569 141.312 135.853 141.72 ;
     RECT  135.497 214.704 135.884 216.888 ;
     RECT  135.421 218.064 135.884 218.088 ;
     RECT  134.921 164.88 135.889 165.288 ;
     RECT  135.884 214.704 135.893 218.088 ;
     RECT  135.817 275.904 135.901 275.928 ;
     RECT  135.281 226.08 135.961 226.296 ;
     RECT  135.853 140.784 135.965 141.72 ;
     RECT  135.673 159.84 135.965 163.032 ;
     RECT  135.349 243.168 135.997 243.192 ;
     RECT  135.889 164.64 136.001 165.288 ;
     RECT  135.685 207.696 136.021 212.616 ;
     RECT  135.389 151.584 136.037 151.608 ;
     RECT  135.821 158.592 136.037 158.616 ;
     RECT  135.997 242.208 136.067 243.192 ;
     RECT  135.965 140.784 136.073 141.384 ;
     RECT  135.569 197.328 136.073 204.84 ;
     RECT  135.749 220.704 136.073 220.728 ;
     RECT  133.445 240.528 136.073 240.552 ;
     RECT  136.067 242.208 136.081 242.232 ;
     RECT  134.633 233.136 136.105 233.16 ;
     RECT  135.011 234.144 136.105 234.168 ;
     RECT  136.073 141.168 136.109 141.384 ;
     RECT  134.963 153.936 136.117 155.736 ;
     RECT  135.997 157.44 136.117 157.464 ;
     RECT  135.493 169.056 136.117 180.696 ;
     RECT  135.205 150.336 136.141 150.36 ;
     RECT  136.073 197.52 136.213 204.84 ;
     RECT  135.137 206.592 136.213 206.616 ;
     RECT  136.021 207.696 136.213 213.384 ;
     RECT  136.117 153.936 136.217 157.464 ;
     RECT  136.109 141.312 136.253 141.384 ;
     RECT  135.491 143.664 136.253 144.12 ;
     RECT  134.957 166.416 136.285 166.776 ;
     RECT  134.957 167.856 136.285 167.88 ;
     RECT  136.213 197.52 136.357 205.08 ;
     RECT  136.141 149.952 136.361 150.36 ;
     RECT  135.457 238.272 136.397 238.536 ;
     RECT  136.213 206.592 136.429 213.384 ;
     RECT  135.749 236.4 136.433 236.424 ;
     RECT  135.421 230.16 136.46 230.952 ;
     RECT  135.101 228.192 136.501 228.216 ;
     RECT  136.46 230.112 136.501 230.952 ;
     RECT  135.961 226.08 136.537 226.344 ;
     RECT  136.249 152.736 136.549 152.76 ;
     RECT  136.217 153.936 136.549 156.456 ;
     RECT  136.105 233.136 136.604 234.168 ;
     RECT  135.349 235.152 136.604 235.176 ;
     RECT  136.397 238.512 136.681 238.536 ;
     RECT  136.357 197.52 136.741 205.224 ;
     RECT  136.429 206.352 136.741 213.384 ;
     RECT  136.741 197.52 136.753 213.384 ;
     RECT  135.893 214.704 136.753 215.304 ;
     RECT  135.281 224.832 136.753 224.856 ;
     RECT  136.537 226.08 136.753 226.776 ;
     RECT  136.753 224.832 136.789 226.776 ;
     RECT  136.501 228.192 136.789 230.952 ;
     RECT  136.117 169.056 136.825 180.84 ;
     RECT  135.709 181.824 136.825 193.176 ;
     RECT  136.001 164.88 136.885 165.288 ;
     RECT  136.285 166.416 136.885 167.88 ;
     RECT  135.965 159.84 136.969 162.504 ;
     RECT  135.713 194.736 137.077 196.152 ;
     RECT  136.253 141.36 137.221 141.384 ;
     RECT  136.465 147.6 137.221 147.624 ;
     RECT  134.915 148.8 137.221 148.824 ;
     RECT  137.077 194.592 137.257 196.152 ;
     RECT  137.221 147.6 137.269 148.824 ;
     RECT  136.361 149.952 137.269 150.312 ;
     RECT  136.753 197.52 137.269 215.304 ;
     RECT  135.961 244.368 137.269 244.392 ;
     RECT  136.217 157.44 137.293 157.464 ;
     RECT  137.257 194.544 137.293 196.152 ;
     RECT  137.257 237.456 137.329 237.48 ;
     RECT  136.549 152.736 137.401 156.456 ;
     RECT  137.293 157.44 137.401 157.896 ;
     RECT  137.077 139.104 137.408 139.128 ;
     RECT  137.036 140.208 137.408 140.232 ;
     RECT  137.221 141.36 137.408 142.104 ;
     RECT  136.253 143.808 137.408 144.12 ;
     RECT  136.177 145.152 137.408 145.896 ;
     RECT  137.269 147.6 137.408 150.312 ;
     RECT  137.401 152.736 137.408 157.896 ;
     RECT  136.969 159.36 137.408 162.504 ;
     RECT  136.681 163.488 137.408 163.512 ;
     RECT  136.885 164.88 137.408 167.88 ;
     RECT  136.825 169.056 137.408 193.176 ;
     RECT  137.293 194.544 137.408 196.392 ;
     RECT  137.269 197.472 137.408 215.304 ;
     RECT  135.893 216.288 137.408 218.088 ;
     RECT  136.969 220.56 137.408 220.584 ;
     RECT  135.389 221.856 137.408 222.264 ;
     RECT  137.041 223.68 137.408 223.704 ;
     RECT  136.789 224.832 137.408 230.952 ;
     RECT  136.604 233.136 137.408 235.176 ;
     RECT  137.329 236.976 137.408 237.48 ;
     RECT  136.681 238.512 137.408 238.872 ;
     RECT  136.897 239.856 137.408 239.88 ;
     RECT  137.041 242.016 137.408 242.04 ;
     RECT  137.329 243.36 137.408 243.384 ;
     RECT  137.269 244.368 137.408 245.256 ;
     RECT  137.408 2.148 137.512 369.372 ;
     RECT  137.512 2.418 137.704 369.102 ;
     RECT  137.704 167.76 137.765 172.632 ;
     RECT  137.704 215.28 137.801 218.088 ;
     RECT  137.765 167.808 137.837 172.632 ;
     RECT  137.704 149.76 137.843 151.416 ;
     RECT  137.704 153.888 137.843 154.872 ;
     RECT  137.704 236.976 137.843 238.872 ;
     RECT  137.704 228.048 137.873 229.464 ;
     RECT  137.704 231.456 137.873 232.056 ;
     RECT  137.843 150.288 137.909 150.312 ;
     RECT  137.704 173.76 137.909 209.88 ;
     RECT  137.704 242.016 137.909 242.04 ;
     RECT  137.704 156.336 137.945 159.384 ;
     RECT  137.873 231.504 137.945 232.056 ;
     RECT  137.704 139.104 137.981 139.128 ;
     RECT  137.909 196.08 137.987 209.88 ;
     RECT  137.704 221.856 137.987 223.8 ;
     RECT  137.704 225.36 137.987 226.68 ;
     RECT  137.704 145.152 138.017 148.104 ;
     RECT  137.704 244.944 138.017 244.968 ;
     RECT  137.987 196.128 138.035 209.88 ;
     RECT  138.035 201.216 138.083 209.88 ;
     RECT  137.945 156.336 138.089 159.096 ;
     RECT  138.083 201.216 138.161 204.792 ;
     RECT  137.704 136.992 138.179 137.976 ;
     RECT  138.017 145.152 138.197 148.008 ;
     RECT  137.704 211.056 138.197 213.768 ;
     RECT  138.179 136.992 138.22 137.016 ;
     RECT  138.089 157.872 138.233 159.096 ;
     RECT  137.704 152.736 138.305 152.76 ;
     RECT  138.197 211.248 138.305 213.768 ;
     RECT  137.704 233.232 138.377 235.224 ;
     RECT  138.197 146.496 138.413 148.008 ;
     RECT  138.233 157.968 138.485 159.096 ;
     RECT  137.873 229.152 138.557 229.464 ;
     RECT  137.843 238.512 138.557 238.872 ;
     RECT  137.837 167.904 138.697 172.632 ;
     RECT  137.909 173.76 138.697 194.712 ;
     RECT  137.801 216.624 138.697 218.088 ;
     RECT  138.697 167.904 138.701 194.712 ;
     RECT  138.377 235.2 138.707 235.224 ;
     RECT  137.704 165.36 138.733 166.488 ;
     RECT  138.697 216.624 138.803 218.856 ;
     RECT  138.305 213.744 138.805 213.768 ;
     RECT  138.083 206.352 138.841 209.88 ;
     RECT  137.704 160.56 138.877 163.512 ;
     RECT  138.733 164.64 138.877 166.488 ;
     RECT  138.805 213.744 138.913 214.056 ;
     RECT  137.873 228.048 138.913 228.072 ;
     RECT  138.557 238.848 138.913 238.872 ;
     RECT  137.704 239.856 138.913 240.12 ;
     RECT  138.035 196.128 138.985 199.944 ;
     RECT  137.987 222.96 138.985 223.704 ;
     RECT  138.841 206.352 138.989 210.264 ;
     RECT  137.987 221.856 138.989 221.88 ;
     RECT  137.843 237.456 138.989 237.48 ;
     RECT  137.704 141.648 139.021 142.872 ;
     RECT  139.021 141.648 139.057 143.064 ;
     RECT  137.843 151.392 139.057 151.416 ;
     RECT  138.913 149.472 139.061 149.496 ;
     RECT  138.913 213.744 139.093 214.2 ;
     RECT  137.801 215.28 139.093 215.64 ;
     RECT  138.913 228 139.093 228.072 ;
     RECT  138.701 171.792 139.097 194.712 ;
     RECT  139.093 213.744 139.097 215.64 ;
     RECT  138.803 216.624 139.097 218.28 ;
     RECT  138.161 201.312 139.129 204.792 ;
     RECT  139.093 228 139.133 228.6 ;
     RECT  138.877 160.56 139.165 166.488 ;
     RECT  138.985 195.84 139.169 199.944 ;
     RECT  139.057 141.648 139.205 143.16 ;
     RECT  139.097 213.744 139.205 215.496 ;
     RECT  138.805 138.048 139.273 138.072 ;
     RECT  138.989 206.448 139.273 210.264 ;
     RECT  138.305 211.248 139.273 212.76 ;
     RECT  139.205 213.744 139.273 214.584 ;
     RECT  139.057 151.392 139.309 151.56 ;
     RECT  138.413 146.496 139.331 147.96 ;
     RECT  138.197 145.152 139.333 145.368 ;
     RECT  139.331 146.496 139.333 147.672 ;
     RECT  139.129 201.072 139.333 204.792 ;
     RECT  138.913 238.848 139.333 240.12 ;
     RECT  139.165 160.56 139.34 166.536 ;
     RECT  138.701 167.904 139.34 170.52 ;
     RECT  139.205 142.08 139.345 143.16 ;
     RECT  139.093 226.224 139.345 226.248 ;
     RECT  139.097 171.84 139.349 194.712 ;
     RECT  139.333 145.152 139.379 147.672 ;
     RECT  139.333 238.848 139.379 240.504 ;
     RECT  139.333 201.072 139.381 205.32 ;
     RECT  138.949 244.416 139.417 244.44 ;
     RECT  139.379 239.856 139.421 240.504 ;
     RECT  139.417 244.416 139.421 244.872 ;
     RECT  138.757 220.08 139.453 220.104 ;
     RECT  138.985 222.864 139.453 223.704 ;
     RECT  139.349 186.432 139.468 194.712 ;
     RECT  139.169 195.888 139.477 199.944 ;
     RECT  139.381 200.976 139.477 205.32 ;
     RECT  139.468 186.48 139.493 194.712 ;
     RECT  139.345 142.08 139.525 143.352 ;
     RECT  139.345 225.552 139.561 226.248 ;
     RECT  139.333 242.208 139.565 242.232 ;
     RECT  139.477 195.888 139.597 205.32 ;
     RECT  137.704 243.36 139.597 243.384 ;
     RECT  139.421 244.848 139.621 244.872 ;
     RECT  139.417 229.728 139.628 229.752 ;
     RECT  139.561 224.784 139.631 226.248 ;
     RECT  139.628 229.728 139.633 229.848 ;
     RECT  139.309 150.48 139.705 151.56 ;
     RECT  139.34 160.56 139.705 170.52 ;
     RECT  137.843 153.888 139.717 154.824 ;
     RECT  139.421 240.48 139.741 240.504 ;
     RECT  139.273 137.28 139.745 138.072 ;
     RECT  139.379 145.344 139.745 147.096 ;
     RECT  139.705 160.56 139.765 170.808 ;
     RECT  139.765 160.224 139.777 170.808 ;
     RECT  139.717 153.648 139.804 154.824 ;
     RECT  139.777 159.552 139.811 170.808 ;
     RECT  139.097 216.72 139.817 218.28 ;
     RECT  139.453 222.864 139.849 223.8 ;
     RECT  139.631 224.784 139.849 226.488 ;
     RECT  139.811 159.552 139.852 160.248 ;
     RECT  139.811 161.376 139.961 170.808 ;
     RECT  139.633 229.728 139.964 230.328 ;
     RECT  139.741 240.48 139.997 240.936 ;
     RECT  139.964 229.728 140.033 230.808 ;
     RECT  138.485 157.968 140.101 158.376 ;
     RECT  139.597 195.888 140.101 205.416 ;
     RECT  139.273 206.448 140.101 214.584 ;
     RECT  139.849 222.864 140.105 226.488 ;
     RECT  139.493 186.48 140.141 192.744 ;
     RECT  139.493 193.776 140.156 194.712 ;
     RECT  140.101 195.888 140.156 214.584 ;
     RECT  139.961 168.384 140.173 170.808 ;
     RECT  139.349 171.84 140.173 184.968 ;
     RECT  140.156 193.776 140.173 214.584 ;
     RECT  138.377 233.232 140.249 234.024 ;
     RECT  139.379 238.848 140.249 238.872 ;
     RECT  139.705 150.48 140.281 152.184 ;
     RECT  140.105 222.864 140.281 226.44 ;
     RECT  139.961 161.376 140.284 167.304 ;
     RECT  140.249 234 140.3 234.024 ;
     RECT  139.745 138.048 140.317 138.072 ;
     RECT  139.669 139.104 140.317 139.128 ;
     RECT  140.101 157.2 140.317 158.376 ;
     RECT  139.852 159.552 140.317 160.152 ;
     RECT  140.317 138.048 140.357 139.128 ;
     RECT  139.804 154.464 140.357 154.824 ;
     RECT  140.317 157.2 140.357 160.152 ;
     RECT  140.033 230.16 140.357 230.808 ;
     RECT  140.357 157.2 140.387 159.048 ;
     RECT  140.357 154.8 140.389 154.824 ;
     RECT  140.173 193.776 140.389 215.112 ;
     RECT  140.281 222.192 140.389 226.44 ;
     RECT  140.387 158.4 140.401 159.048 ;
     RECT  139.597 242.304 140.425 243.384 ;
     RECT  139.453 219.552 140.465 220.104 ;
     RECT  139.133 228.048 140.465 228.6 ;
     RECT  140.389 193.776 140.501 215.496 ;
     RECT  139.525 142.08 140.533 143.688 ;
     RECT  140.3 234 140.533 234.216 ;
     RECT  140.341 235.2 140.533 235.224 ;
     RECT  140.284 165.36 140.537 167.304 ;
     RECT  140.533 142.032 140.573 143.688 ;
     RECT  140.387 157.2 140.573 157.224 ;
     RECT  140.389 221.76 140.573 226.44 ;
     RECT  140.389 154.8 140.605 155.016 ;
     RECT  140.141 192.432 140.605 192.744 ;
     RECT  140.501 193.776 140.605 205.416 ;
     RECT  140.425 242.304 140.605 243.768 ;
     RECT  139.621 244.848 140.605 245.112 ;
     RECT  140.357 138.048 140.609 138.936 ;
     RECT  140.573 143.376 140.609 143.688 ;
     RECT  140.573 221.76 140.609 222.216 ;
     RECT  140.357 230.448 140.641 230.808 ;
     RECT  140.605 192.432 140.645 205.416 ;
     RECT  140.605 242.304 140.675 245.112 ;
     RECT  140.465 219.552 140.677 219.96 ;
     RECT  139.997 240.48 140.677 240.504 ;
     RECT  140.141 186.48 140.713 191.352 ;
     RECT  140.501 206.448 140.717 215.496 ;
     RECT  140.675 244.512 140.717 245.112 ;
     RECT  140.573 142.032 140.723 142.104 ;
     RECT  140.717 208.56 140.725 215.496 ;
     RECT  139.817 216.72 140.725 217.464 ;
     RECT  140.717 206.448 140.753 207.576 ;
     RECT  140.573 223.392 140.753 226.44 ;
     RECT  139.745 146.208 140.773 147.096 ;
     RECT  140.533 148.272 140.773 148.296 ;
     RECT  140.749 238.32 140.785 238.344 ;
     RECT  140.605 154.8 140.789 155.16 ;
     RECT  140.773 146.208 140.819 149.208 ;
     RECT  140.717 244.512 140.825 244.536 ;
     RECT  140.173 168.384 140.893 184.968 ;
     RECT  140.713 186.288 140.893 191.352 ;
     RECT  140.533 234 140.897 235.224 ;
     RECT  140.723 142.032 140.933 142.056 ;
     RECT  140.819 149.184 140.965 149.208 ;
     RECT  140.785 238.128 140.965 238.344 ;
     RECT  140.357 160.128 140.969 160.152 ;
     RECT  140.965 149.184 141.005 149.352 ;
     RECT  140.281 150.336 141.005 152.184 ;
     RECT  137.945 232.032 141.005 232.056 ;
     RECT  140.893 168.384 141.011 191.352 ;
     RECT  140.789 154.8 141.041 155.016 ;
     RECT  140.641 230.448 141.041 230.904 ;
     RECT  140.609 221.76 141.073 221.784 ;
     RECT  140.897 234.24 141.077 235.224 ;
     RECT  141.011 168.384 141.107 170.472 ;
     RECT  141.073 221.184 141.113 221.784 ;
     RECT  140.675 242.304 141.113 243.384 ;
     RECT  140.677 239.952 141.116 240.504 ;
     RECT  141.011 171.552 141.157 191.352 ;
     RECT  140.645 192.432 141.157 205.224 ;
     RECT  141.116 239.952 141.203 240.6 ;
     RECT  140.753 225.552 141.217 226.44 ;
     RECT  140.537 167.232 141.253 167.304 ;
     RECT  141.107 168.384 141.253 170.376 ;
     RECT  141.253 167.232 141.329 170.376 ;
     RECT  140.725 208.56 141.329 217.464 ;
     RECT  140.753 223.392 141.347 224.472 ;
     RECT  137.704 135.216 141.361 135.24 ;
     RECT  140.389 136.944 141.361 136.968 ;
     RECT  140.819 146.208 141.397 146.472 ;
     RECT  141.361 135.216 141.401 136.968 ;
     RECT  141.347 224.448 141.401 224.472 ;
     RECT  141.401 135.216 141.437 136.776 ;
     RECT  141.347 223.392 141.541 223.464 ;
     RECT  140.401 158.4 141.613 158.904 ;
     RECT  141.329 212.736 141.649 217.464 ;
     RECT  141.077 234.96 141.653 235.224 ;
     RECT  141.157 171.552 141.685 205.224 ;
     RECT  140.753 206.448 141.685 207.48 ;
     RECT  141.685 171.552 141.721 207.48 ;
     RECT  141.329 208.56 141.721 211.752 ;
     RECT  141.613 158.256 141.757 158.904 ;
     RECT  140.609 143.376 141.829 143.448 ;
     RECT  141.757 145.152 141.829 145.176 ;
     RECT  141.757 157.296 141.829 158.904 ;
     RECT  140.284 161.376 141.829 163.8 ;
     RECT  140.629 246.576 141.829 246.6 ;
     RECT  141.653 234.96 141.833 234.984 ;
     RECT  141.041 154.8 141.865 154.824 ;
     RECT  141.397 146.16 141.877 146.472 ;
     RECT  140.819 147.6 141.877 147.624 ;
     RECT  141.649 212.736 141.877 218.328 ;
     RECT  141.829 144.864 141.901 145.176 ;
     RECT  141.877 146.16 141.901 147.624 ;
     RECT  141.217 225.552 141.925 227.208 ;
     RECT  141.829 161.376 141.973 164.184 ;
     RECT  140.537 165.36 141.973 165.816 ;
     RECT  141.829 142.752 142.009 143.448 ;
     RECT  140.677 219.408 142.009 219.96 ;
     RECT  141.113 221.184 142.009 221.592 ;
     RECT  141.865 153.888 142.081 154.824 ;
     RECT  138.697 156.144 142.117 156.168 ;
     RECT  141.829 157.296 142.117 158.952 ;
     RECT  141.541 223.152 142.117 223.464 ;
     RECT  141.113 243.12 142.189 243.384 ;
     RECT  140.609 138.912 142.261 138.936 ;
     RECT  142.009 142.464 142.316 143.448 ;
     RECT  141.901 144.864 142.316 147.624 ;
     RECT  142.081 153.888 142.357 154.92 ;
     RECT  142.117 155.904 142.357 158.952 ;
     RECT  141.005 149.328 142.364 149.352 ;
     RECT  141.005 150.72 142.364 152.184 ;
     RECT  141.001 228.768 142.369 228.792 ;
     RECT  140.965 237.504 142.405 238.344 ;
     RECT  141.203 239.952 142.405 240.36 ;
     RECT  141.329 167.664 142.441 170.376 ;
     RECT  142.117 222.912 142.441 223.464 ;
     RECT  141.437 135.984 142.477 136.776 ;
     RECT  141.721 171.552 142.501 211.752 ;
     RECT  141.877 212.736 142.501 218.376 ;
     RECT  142.501 171.552 142.508 218.376 ;
     RECT  142.261 138.528 142.513 138.936 ;
     RECT  142.009 219.408 142.513 221.592 ;
     RECT  142.441 222.912 142.513 224.184 ;
     RECT  142.508 171.552 142.549 218.424 ;
     RECT  142.513 219.408 142.549 224.184 ;
     RECT  142.405 237.504 142.549 240.36 ;
     RECT  142.549 237.504 142.597 241.176 ;
     RECT  142.189 242.256 142.597 243.384 ;
     RECT  142.441 167.664 142.621 170.52 ;
     RECT  142.549 171.552 142.621 224.184 ;
     RECT  142.621 167.664 142.657 224.184 ;
     RECT  142.333 232.992 142.665 233.016 ;
     RECT  142.477 234.24 142.665 234.264 ;
     RECT  142.357 153.888 142.765 158.952 ;
     RECT  142.165 160.032 142.765 160.152 ;
     RECT  140.857 133.008 142.808 133.032 ;
     RECT  142.477 135.888 142.808 136.776 ;
     RECT  142.513 138.048 142.808 138.936 ;
     RECT  142.172 141.168 142.808 141.192 ;
     RECT  142.316 142.464 142.808 147.624 ;
     RECT  142.364 149.328 142.808 152.184 ;
     RECT  142.765 153.888 142.808 160.152 ;
     RECT  141.973 161.376 142.808 166.68 ;
     RECT  142.657 167.664 142.808 224.52 ;
     RECT  141.925 225.504 142.808 227.208 ;
     RECT  142.369 228.528 142.808 228.792 ;
     RECT  141.181 231.264 142.808 231.288 ;
     RECT  142.665 232.992 142.808 234.264 ;
     RECT  142.597 237.504 142.808 243.384 ;
     RECT  141.829 246.576 142.808 246.888 ;
     RECT  142.808 2.148 142.912 369.372 ;
     RECT  142.912 2.418 143.104 369.102 ;
     RECT  143.104 171.84 143.129 222.36 ;
     RECT  143.129 171.84 143.165 214.488 ;
     RECT  143.104 223.728 143.219 228.552 ;
     RECT  143.104 243.36 143.219 243.384 ;
     RECT  143.104 244.416 143.219 244.968 ;
     RECT  143.219 223.776 143.26 228.552 ;
     RECT  143.104 229.632 143.345 231.288 ;
     RECT  143.345 229.632 143.411 230.376 ;
     RECT  143.104 154.32 143.453 157.368 ;
     RECT  143.129 215.76 143.453 222.36 ;
     RECT  143.104 164.4 143.459 166.824 ;
     RECT  143.453 215.76 143.597 221.256 ;
     RECT  143.104 146.16 143.777 148.68 ;
     RECT  143.104 236.256 143.795 236.28 ;
     RECT  143.104 138.048 143.849 138.936 ;
     RECT  143.165 195.312 143.891 214.488 ;
     RECT  143.777 146.16 143.921 147.816 ;
     RECT  143.104 140.736 143.939 143.448 ;
     RECT  143.26 225.504 143.957 228.552 ;
     RECT  143.939 140.736 144.029 141.336 ;
     RECT  143.891 195.312 144.035 211.416 ;
     RECT  143.891 212.4 144.035 214.488 ;
     RECT  143.104 145.056 144.097 145.128 ;
     RECT  143.921 146.16 144.097 147.624 ;
     RECT  143.104 158.496 144.133 160.056 ;
     RECT  143.104 161.136 144.133 163.272 ;
     RECT  143.459 164.4 144.133 164.568 ;
     RECT  143.104 168.144 144.133 170.52 ;
     RECT  143.165 171.84 144.133 194.28 ;
     RECT  144.035 195.312 144.133 210.696 ;
     RECT  143.104 233.088 144.133 234.696 ;
     RECT  143.104 242.256 144.133 242.28 ;
     RECT  143.104 150.384 144.173 153.24 ;
     RECT  144.133 158.496 144.173 160.152 ;
     RECT  144.035 212.64 144.173 214.488 ;
     RECT  144.133 241.632 144.173 242.28 ;
     RECT  143.939 142.464 144.209 143.448 ;
     RECT  144.133 232.896 144.241 234.696 ;
     RECT  143.957 225.552 144.245 228.552 ;
     RECT  144.241 232.512 144.281 234.696 ;
     RECT  143.104 239.088 144.281 239.976 ;
     RECT  144.173 241.632 144.281 241.656 ;
     RECT  144.173 150.72 144.313 153.24 ;
     RECT  143.453 154.32 144.313 155.928 ;
     RECT  144.173 160.128 144.325 160.152 ;
     RECT  144.133 161.136 144.325 164.568 ;
     RECT  143.597 215.76 144.353 217.752 ;
     RECT  144.133 168.144 144.38 170.76 ;
     RECT  144.133 171.84 144.38 210.696 ;
     RECT  144.281 234.288 144.419 234.696 ;
     RECT  143.411 230.352 144.461 230.376 ;
     RECT  144.38 168.144 144.467 210.696 ;
     RECT  143.104 135.984 144.517 136.824 ;
     RECT  144.029 140.736 144.529 140.76 ;
     RECT  144.281 232.512 144.533 232.92 ;
     RECT  144.313 150.72 144.565 155.928 ;
     RECT  143.597 218.88 144.601 221.256 ;
     RECT  143.26 223.776 144.605 224.232 ;
     RECT  144.517 135.072 144.641 136.824 ;
     RECT  144.325 160.128 144.661 164.568 ;
     RECT  144.533 232.512 144.677 232.536 ;
     RECT  144.173 212.784 144.745 214.488 ;
     RECT  143.219 244.464 144.745 244.488 ;
     RECT  144.097 145.056 144.757 147.624 ;
     RECT  144.601 218.544 144.757 221.256 ;
     RECT  143.453 222.24 144.757 222.36 ;
     RECT  144.641 135.744 144.803 136.824 ;
     RECT  144.757 144.624 144.803 147.624 ;
     RECT  144.757 218.544 144.803 222.36 ;
     RECT  144.803 135.744 144.821 136.2 ;
     RECT  143.849 138.048 144.821 138.312 ;
     RECT  144.245 228.528 144.821 228.552 ;
     RECT  144.745 212.784 144.853 214.776 ;
     RECT  144.353 215.76 144.853 217.464 ;
     RECT  144.803 218.544 144.857 222.264 ;
     RECT  144.605 224.208 144.889 224.232 ;
     RECT  144.805 132.528 144.892 132.552 ;
     RECT  144.857 218.544 144.893 218.568 ;
     RECT  144.853 212.784 144.899 217.464 ;
     RECT  144.803 144.624 144.901 145.08 ;
     RECT  144.709 133.584 144.929 133.608 ;
     RECT  144.529 140.064 144.929 140.76 ;
     RECT  144.821 135.984 144.947 136.2 ;
     RECT  144.86 138.384 144.947 138.408 ;
     RECT  144.209 142.944 144.947 143.448 ;
     RECT  144.889 224.208 144.965 224.568 ;
     RECT  144.419 234.672 145.001 234.696 ;
     RECT  144.947 136.176 145.037 136.2 ;
     RECT  144.467 172.08 145.037 210.696 ;
     RECT  145.037 185.664 145.073 210.696 ;
     RECT  144.745 243.936 145.073 244.488 ;
     RECT  143.459 166.128 145.093 166.824 ;
     RECT  144.467 168.144 145.105 170.76 ;
     RECT  144.661 160.128 145.109 164.76 ;
     RECT  144.899 212.784 145.141 217.224 ;
     RECT  145.109 163.776 145.145 164.76 ;
     RECT  144.965 224.544 145.177 224.568 ;
     RECT  144.245 225.552 145.177 227.208 ;
     RECT  144.857 219.6 145.181 222.264 ;
     RECT  144.565 150.72 145.187 156.072 ;
     RECT  145.187 151.632 145.213 156.072 ;
     RECT  143.453 157.344 145.213 157.368 ;
     RECT  145.093 166.128 145.213 166.968 ;
     RECT  145.105 168.096 145.213 170.76 ;
     RECT  144.803 146.112 145.253 147.624 ;
     RECT  145.037 172.08 145.253 184.68 ;
     RECT  145.213 151.632 145.283 157.368 ;
     RECT  145.283 155.904 145.297 157.368 ;
     RECT  145.145 163.824 145.321 164.76 ;
     RECT  145.213 166.128 145.321 170.76 ;
     RECT  145.073 243.936 145.321 243.96 ;
     RECT  145.297 155.904 145.325 156.168 ;
     RECT  145.321 243.36 145.361 243.96 ;
     RECT  145.283 151.632 145.397 154.68 ;
     RECT  144.901 144.48 145.433 145.08 ;
     RECT  145.397 152.496 145.433 154.68 ;
     RECT  145.297 157.344 145.433 157.368 ;
     RECT  145.253 146.112 145.475 147.576 ;
     RECT  144.281 239.088 145.501 239.112 ;
     RECT  144.173 158.496 145.525 159.144 ;
     RECT  145.109 160.128 145.525 162.792 ;
     RECT  145.073 185.808 145.525 210.696 ;
     RECT  145.141 211.824 145.525 217.224 ;
     RECT  145.525 158.496 145.541 162.792 ;
     RECT  144.925 134.592 145.577 134.616 ;
     RECT  145.177 224.544 145.577 227.208 ;
     RECT  145.357 150.384 145.609 150.408 ;
     RECT  145.321 163.824 145.609 170.76 ;
     RECT  145.541 158.496 145.613 159.624 ;
     RECT  144.947 142.944 145.649 142.968 ;
     RECT  145.433 152.496 145.649 154.344 ;
     RECT  145.541 160.608 145.685 162.792 ;
     RECT  145.525 185.808 145.708 217.224 ;
     RECT  145.708 212.064 145.721 217.224 ;
     RECT  144.929 140.064 145.793 140.088 ;
     RECT  145.361 243.36 145.813 243.384 ;
     RECT  145.465 228.576 145.825 228.792 ;
     RECT  145.609 150.24 145.865 150.408 ;
     RECT  145.813 241.68 145.9 241.704 ;
     RECT  145.501 238.944 145.955 239.544 ;
     RECT  145.253 172.128 146.037 184.68 ;
     RECT  145.577 224.544 146.041 226.968 ;
     RECT  145.708 185.808 146.051 211.032 ;
     RECT  145.609 163.824 146.117 170.856 ;
     RECT  145.825 228.576 146.117 229.128 ;
     RECT  145.753 234.144 146.156 234.168 ;
     RECT  145.645 235.248 146.156 235.272 ;
     RECT  146.117 163.824 146.177 170.616 ;
     RECT  145.865 150.384 146.185 150.408 ;
     RECT  146.185 150.384 146.189 150.504 ;
     RECT  146.051 186.192 146.225 211.032 ;
     RECT  146.156 234.144 146.243 235.272 ;
     RECT  145.325 155.904 146.261 156.024 ;
     RECT  145.475 146.112 146.293 147.48 ;
     RECT  146.189 150.48 146.297 150.504 ;
     RECT  146.117 228.864 146.297 229.128 ;
     RECT  145.955 238.944 146.333 239.016 ;
     RECT  146.243 234.144 146.365 234.168 ;
     RECT  146.243 235.248 146.365 235.272 ;
     RECT  146.225 186.912 146.405 211.032 ;
     RECT  145.181 220.368 146.405 222.264 ;
     RECT  145.501 232.464 146.437 232.488 ;
     RECT  146.365 233.616 146.437 234.168 ;
     RECT  143.104 237.792 146.437 237.816 ;
     RECT  146.405 186.912 146.441 210.744 ;
     RECT  146.437 231.936 146.473 234.168 ;
     RECT  146.041 224.256 146.483 226.968 ;
     RECT  146.473 231.504 146.483 234.168 ;
     RECT  145.813 243.072 146.485 243.384 ;
     RECT  146.473 244.416 146.485 244.44 ;
     RECT  146.437 237.648 146.509 237.816 ;
     RECT  146.333 238.944 146.509 238.968 ;
     RECT  145.613 158.496 146.513 159.576 ;
     RECT  146.483 225.552 146.513 226.968 ;
     RECT  146.405 220.368 146.53 220.392 ;
     RECT  146.485 243.072 146.531 244.44 ;
     RECT  146.437 143.184 146.545 143.208 ;
     RECT  145.433 144.48 146.545 144.504 ;
     RECT  146.513 158.496 146.549 159.48 ;
     RECT  146.177 163.536 146.549 170.616 ;
     RECT  146.297 229.104 146.549 229.128 ;
     RECT  146.531 243.696 146.557 244.44 ;
     RECT  146.53 220.32 146.617 220.392 ;
     RECT  146.509 237.648 146.621 238.968 ;
     RECT  146.549 158.496 146.653 159.144 ;
     RECT  146.441 186.912 146.657 195.192 ;
     RECT  146.653 158.304 146.689 159.144 ;
     RECT  146.657 193.968 146.693 195.192 ;
     RECT  145.069 141.744 146.725 141.768 ;
     RECT  146.545 143.184 146.725 144.504 ;
     RECT  146.549 163.536 146.729 166.152 ;
     RECT  146.617 220.224 146.797 220.392 ;
     RECT  145.685 160.608 146.876 162.216 ;
     RECT  145.721 212.64 146.876 217.224 ;
     RECT  146.689 158.016 146.905 159.144 ;
     RECT  146.037 172.368 146.905 184.68 ;
     RECT  146.725 141.744 146.917 144.504 ;
     RECT  146.833 139.152 146.941 139.176 ;
     RECT  146.917 141.552 146.963 144.504 ;
     RECT  146.876 160.512 146.963 162.216 ;
     RECT  146.876 211.968 146.963 217.224 ;
     RECT  146.293 145.824 147.013 147.48 ;
     RECT  145.649 152.496 147.02 153.768 ;
     RECT  146.405 221.568 147.02 222.264 ;
     RECT  147.02 221.568 147.049 222.84 ;
     RECT  147.013 223.968 147.049 223.992 ;
     RECT  146.965 236.544 147.053 236.568 ;
     RECT  146.941 139.152 147.059 139.656 ;
     RECT  146.869 230.256 147.059 230.28 ;
     RECT  146.483 231.504 147.059 233.112 ;
     RECT  146.509 151.056 147.061 151.08 ;
     RECT  147.02 152.304 147.061 153.768 ;
     RECT  146.797 218.256 147.085 218.28 ;
     RECT  147.059 139.152 147.089 139.176 ;
     RECT  146.963 141.552 147.1 142.488 ;
     RECT  147.1 142.416 147.161 142.488 ;
     RECT  146.185 148.8 147.161 148.824 ;
     RECT  146.905 157.92 147.233 159.144 ;
     RECT  147.059 231.504 147.233 231.96 ;
     RECT  146.261 156 147.301 156.024 ;
     RECT  146.365 235.248 147.301 235.56 ;
     RECT  146.905 172.368 147.337 184.92 ;
     RECT  146.657 186.912 147.337 192.696 ;
     RECT  147.301 155.712 147.397 157.32 ;
     RECT  147.301 235.248 147.404 235.608 ;
     RECT  146.621 237.744 147.404 238.968 ;
     RECT  147.061 151.056 147.409 153.768 ;
     RECT  146.797 219.984 147.409 220.392 ;
     RECT  147.049 221.568 147.409 223.992 ;
     RECT  147.397 155.424 147.517 157.32 ;
     RECT  147.409 219.984 147.517 223.992 ;
     RECT  146.513 225.744 147.517 226.968 ;
     RECT  147.085 218.256 147.541 218.52 ;
     RECT  147.517 219.984 147.541 226.968 ;
     RECT  147.404 235.152 147.553 235.608 ;
     RECT  147.233 158.448 147.589 159.144 ;
     RECT  146.549 167.472 147.617 170.616 ;
     RECT  146.441 196.608 147.644 210.744 ;
     RECT  146.729 164.544 147.661 166.152 ;
     RECT  147.617 167.472 147.661 170.904 ;
     RECT  147.337 186.864 147.685 192.696 ;
     RECT  146.693 193.968 147.685 194.568 ;
     RECT  147.337 171.888 147.733 184.92 ;
     RECT  146.729 163.536 147.74 163.56 ;
     RECT  147.661 164.544 147.74 170.904 ;
     RECT  147.013 145.536 147.769 147.48 ;
     RECT  147.685 186.864 147.769 194.568 ;
     RECT  147.644 196.176 147.781 210.744 ;
     RECT  147.769 186.864 147.805 195 ;
     RECT  147.445 228.48 147.877 228.504 ;
     RECT  147.781 196.176 147.985 211.08 ;
     RECT  147.059 233.088 148.057 233.112 ;
     RECT  147.161 142.416 148.208 142.44 ;
     RECT  146.963 143.616 148.208 144.504 ;
     RECT  147.769 145.536 148.208 147.768 ;
     RECT  147.337 148.848 148.208 148.872 ;
     RECT  147.409 151.056 148.208 154.008 ;
     RECT  147.517 155.136 148.208 157.32 ;
     RECT  147.589 158.448 148.208 159.624 ;
     RECT  146.963 160.608 148.208 162.216 ;
     RECT  147.74 163.536 148.208 170.904 ;
     RECT  147.733 171.888 148.208 185.304 ;
     RECT  147.805 186.864 148.208 195.096 ;
     RECT  147.985 196.176 148.208 211.512 ;
     RECT  146.963 212.64 148.208 217.224 ;
     RECT  147.541 218.256 148.208 226.968 ;
     RECT  147.877 228 148.208 228.504 ;
     RECT  147.233 231.504 148.208 231.528 ;
     RECT  148.057 232.896 148.208 233.112 ;
     RECT  147.553 234.432 148.208 235.608 ;
     RECT  147.404 237.744 148.208 239.064 ;
     RECT  145.177 240.528 148.208 240.552 ;
     RECT  147.445 241.68 148.208 241.704 ;
     RECT  146.557 243.696 148.208 243.72 ;
     RECT  148.208 2.148 148.312 369.372 ;
     RECT  148.312 2.418 148.504 369.102 ;
     RECT  148.504 237.744 148.529 237.768 ;
     RECT  148.504 172.128 148.565 183.432 ;
     RECT  148.504 199.344 148.565 212.04 ;
     RECT  148.504 213.168 148.565 213.24 ;
     RECT  148.504 215.952 148.601 220.584 ;
     RECT  148.504 157.152 148.643 157.32 ;
     RECT  148.504 234.192 148.643 234.504 ;
     RECT  148.504 146.352 148.673 149.784 ;
     RECT  148.601 215.952 148.673 219.096 ;
     RECT  148.643 234.192 148.673 234.216 ;
     RECT  148.504 159.024 148.681 159.384 ;
     RECT  148.681 159.216 148.691 159.384 ;
     RECT  148.504 142.416 148.709 144.744 ;
     RECT  148.673 218.496 148.709 219.096 ;
     RECT  148.673 146.352 148.739 147.624 ;
     RECT  148.504 184.704 148.745 185.976 ;
     RECT  148.673 148.608 148.781 149.784 ;
     RECT  148.565 172.32 148.781 183.432 ;
     RECT  148.504 189.984 148.787 198.264 ;
     RECT  148.504 226.944 148.787 228.6 ;
     RECT  148.781 149.76 148.835 149.784 ;
     RECT  148.504 153.168 148.835 154.008 ;
     RECT  148.673 215.952 148.835 217.224 ;
     RECT  148.504 231.504 148.853 232.92 ;
     RECT  148.504 160.752 148.883 170.568 ;
     RECT  148.883 163.776 148.889 170.568 ;
     RECT  148.504 214.272 148.931 214.776 ;
     RECT  148.835 153.984 148.953 154.008 ;
     RECT  148.781 172.464 148.961 183.432 ;
     RECT  148.739 146.352 149.075 146.52 ;
     RECT  148.709 142.464 149.105 144.744 ;
     RECT  149.105 143.04 149.123 144.744 ;
     RECT  149.123 144.144 149.141 144.744 ;
     RECT  149.123 143.04 149.149 143.064 ;
     RECT  149.141 144.144 149.164 144.264 ;
     RECT  148.565 199.344 149.177 207.24 ;
     RECT  148.835 216.864 149.177 217.224 ;
     RECT  148.504 150.864 149.213 151.608 ;
     RECT  148.787 226.944 149.213 228.504 ;
     RECT  148.504 235.488 149.213 235.656 ;
     RECT  148.787 195.36 149.357 198.264 ;
     RECT  149.177 216.864 149.357 216.936 ;
     RECT  148.889 163.776 149.363 168.312 ;
     RECT  148.565 209.04 149.363 212.04 ;
     RECT  149.075 146.496 149.393 146.52 ;
     RECT  149.177 199.68 149.411 207.24 ;
     RECT  149.164 144.144 149.429 144.168 ;
     RECT  149.363 163.776 149.429 163.8 ;
     RECT  149.411 199.68 149.429 207.192 ;
     RECT  148.709 219.072 149.429 219.096 ;
     RECT  148.745 185.328 149.497 185.976 ;
     RECT  148.504 187.536 149.497 188.376 ;
     RECT  148.787 189.984 149.497 191.112 ;
     RECT  148.504 221.76 149.569 222.84 ;
     RECT  149.363 209.904 149.573 212.04 ;
     RECT  148.889 169.344 149.605 170.568 ;
     RECT  148.961 177.552 149.605 183.432 ;
     RECT  148.931 214.32 149.605 214.776 ;
     RECT  148.691 159.36 149.609 159.384 ;
     RECT  148.601 220.224 149.612 220.584 ;
     RECT  149.573 210.432 149.645 212.04 ;
     RECT  149.612 220.176 149.651 220.584 ;
     RECT  149.651 220.176 149.699 220.488 ;
     RECT  149.605 169.344 149.753 171.432 ;
     RECT  149.497 185.328 149.785 186.456 ;
     RECT  149.699 220.224 149.789 220.488 ;
     RECT  148.504 154.992 149.813 155.448 ;
     RECT  149.645 210.72 149.825 212.04 ;
     RECT  148.565 213.216 149.857 213.24 ;
     RECT  149.605 214.32 149.861 215.448 ;
     RECT  149.213 235.632 149.861 235.656 ;
     RECT  149.605 177.552 149.893 183.96 ;
     RECT  149.785 185.184 149.893 186.456 ;
     RECT  149.357 195.36 149.933 198.12 ;
     RECT  149.893 177.552 149.939 186.456 ;
     RECT  148.643 157.296 149.965 157.32 ;
     RECT  149.939 177.744 150.001 186.456 ;
     RECT  149.497 187.536 150.001 191.112 ;
     RECT  150.001 177.744 150.005 191.112 ;
     RECT  148.781 148.608 150.077 148.632 ;
     RECT  148.853 231.504 150.083 232.392 ;
     RECT  149.213 226.944 150.109 227.544 ;
     RECT  149.429 199.68 150.113 205.272 ;
     RECT  150.109 226.272 150.113 227.544 ;
     RECT  149.933 195.36 150.149 197.064 ;
     RECT  150.073 214.272 150.179 214.296 ;
     RECT  148.883 160.752 150.217 162.456 ;
     RECT  149.753 169.344 150.217 171.288 ;
     RECT  150.133 215.616 150.22 215.64 ;
     RECT  150.217 169.296 150.221 171.288 ;
     RECT  149.429 206.304 150.227 207.192 ;
     RECT  149.813 154.992 150.239 155.64 ;
     RECT  150.181 208.656 150.265 208.68 ;
     RECT  149.213 150.864 150.293 150.888 ;
     RECT  149.363 165.408 150.293 168.312 ;
     RECT  150.113 201.264 150.293 205.272 ;
     RECT  149.357 216.912 150.293 216.936 ;
     RECT  150.083 231.504 150.293 231.528 ;
     RECT  150.005 184.416 150.325 191.112 ;
     RECT  148.787 192.192 150.325 194.376 ;
     RECT  150.217 160.656 150.329 162.456 ;
     RECT  149.965 157.2 150.364 157.32 ;
     RECT  150.329 160.752 150.365 162.456 ;
     RECT  148.961 172.464 150.397 176.424 ;
     RECT  148.504 223.968 150.397 223.992 ;
     RECT  148.739 147.6 150.401 147.624 ;
     RECT  150.149 195.36 150.401 195.72 ;
     RECT  150.325 184.416 150.419 194.376 ;
     RECT  150.005 177.744 150.437 183.432 ;
     RECT  149.789 220.224 150.437 220.248 ;
     RECT  150.397 223.968 150.437 224.568 ;
     RECT  150.113 227.52 150.437 227.544 ;
     RECT  150.397 172.416 150.469 176.424 ;
     RECT  149.825 211.872 150.469 212.04 ;
     RECT  149.857 213.12 150.469 213.24 ;
     RECT  150.293 201.312 150.473 205.272 ;
     RECT  150.469 164.496 150.505 164.52 ;
     RECT  150.293 165.936 150.505 168.312 ;
     RECT  150.221 169.296 150.505 170.184 ;
     RECT  149.825 210.72 150.509 210.744 ;
     RECT  150.437 224.544 150.509 224.568 ;
     RECT  150.113 226.272 150.509 226.296 ;
     RECT  150.239 154.992 150.515 155.688 ;
     RECT  149.569 221.712 150.517 222.84 ;
     RECT  150.515 154.992 150.541 155.592 ;
     RECT  150.541 154.08 150.545 155.592 ;
     RECT  150.419 184.416 150.545 191.112 ;
     RECT  150.401 195.456 150.545 195.72 ;
     RECT  150.545 154.08 150.553 155.496 ;
     RECT  150.221 171.264 150.563 171.288 ;
     RECT  150.517 221.712 150.563 223.272 ;
     RECT  150.469 211.872 150.581 213.672 ;
     RECT  150.365 160.752 150.617 161.4 ;
     RECT  150.581 211.872 150.617 212.856 ;
     RECT  150.253 233.136 150.617 233.16 ;
     RECT  150.469 172.368 150.653 176.424 ;
     RECT  150.617 160.8 150.689 161.4 ;
     RECT  150.505 164.4 150.689 164.52 ;
     RECT  150.113 199.68 150.793 200.04 ;
     RECT  150.563 221.712 150.793 221.736 ;
     RECT  150.364 157.296 150.797 157.32 ;
     RECT  150.181 152.496 150.829 152.52 ;
     RECT  150.365 162.432 150.833 162.456 ;
     RECT  150.793 221.136 150.833 221.736 ;
     RECT  150.829 152.208 150.869 152.52 ;
     RECT  150.505 165.936 150.905 170.184 ;
     RECT  150.473 202.704 150.908 205.272 ;
     RECT  150.553 154.08 150.941 154.104 ;
     RECT  150.937 207.456 150.997 207.48 ;
     RECT  150.997 207.456 151.043 208.104 ;
     RECT  150.563 222.816 151.043 223.272 ;
     RECT  150.869 152.208 151.045 152.232 ;
     RECT  150.653 172.368 151.081 175.56 ;
     RECT  150.437 177.744 151.081 181.08 ;
     RECT  151.045 151.824 151.085 152.232 ;
     RECT  150.689 160.992 151.085 161.4 ;
     RECT  150.617 212.832 151.085 212.856 ;
     RECT  150.545 195.696 151.117 195.72 ;
     RECT  150.149 196.896 151.117 197.064 ;
     RECT  150.689 164.496 151.157 164.52 ;
     RECT  151.009 228.624 151.157 228.648 ;
     RECT  150.437 182.4 151.229 183.432 ;
     RECT  150.905 169.104 151.261 170.184 ;
     RECT  150.905 165.936 151.265 167.592 ;
     RECT  151.081 177.216 151.265 181.08 ;
     RECT  151.229 182.448 151.292 183.432 ;
     RECT  150.545 184.416 151.292 191.016 ;
     RECT  151.265 165.936 151.301 166.296 ;
     RECT  151.085 161.28 151.341 161.4 ;
     RECT  150.793 199.584 151.369 200.04 ;
     RECT  150.473 201.312 151.369 201.624 ;
     RECT  150.419 192.192 151.373 194.376 ;
     RECT  151.292 182.448 151.379 191.016 ;
     RECT  150.901 163.248 151.427 163.272 ;
     RECT  151.373 194.256 151.427 194.376 ;
     RECT  151.341 161.28 151.445 161.928 ;
     RECT  151.043 208.08 151.445 208.104 ;
     RECT  151.301 165.936 151.477 165.96 ;
     RECT  150.833 221.136 151.477 221.16 ;
     RECT  151.085 151.824 151.523 151.848 ;
     RECT  151.436 225.744 151.523 225.768 ;
     RECT  149.749 230.112 151.523 230.136 ;
     RECT  151.373 192.192 151.553 193.224 ;
     RECT  151.477 150.432 151.561 150.84 ;
     RECT  151.427 194.256 151.589 194.28 ;
     RECT  151.261 169.104 151.669 170.472 ;
     RECT  151.081 172.08 151.669 175.56 ;
     RECT  151.369 199.584 151.697 201.624 ;
     RECT  150.908 202.704 151.729 205.32 ;
     RECT  150.227 206.304 151.729 206.328 ;
     RECT  151.669 172.032 151.769 175.56 ;
     RECT  151.697 199.584 151.769 199.992 ;
     RECT  151.477 164.88 151.949 165.96 ;
     RECT  151.669 169.104 151.949 170.808 ;
     RECT  151.769 174.24 152.021 175.56 ;
     RECT  151.801 153.984 152.053 154.008 ;
     RECT  150.553 155.136 152.053 155.496 ;
     RECT  152.021 174.432 152.053 175.56 ;
     RECT  151.769 172.032 152.057 172.92 ;
     RECT  150.997 224.64 152.089 224.664 ;
     RECT  152.053 159.984 152.125 160.008 ;
     RECT  151.477 220.992 152.149 221.16 ;
     RECT  151.043 222.816 152.195 222.84 ;
     RECT  152.089 224.592 152.195 224.664 ;
     RECT  151.117 195.696 152.197 197.064 ;
     RECT  151.379 184.656 152.201 191.016 ;
     RECT  151.265 178.8 152.237 181.08 ;
     RECT  152.237 178.8 152.273 179.16 ;
     RECT  152.161 208.128 152.273 208.152 ;
     RECT  151.945 229.632 152.273 229.656 ;
     RECT  151.265 177.216 152.305 177.768 ;
     RECT  152.273 178.8 152.305 178.824 ;
     RECT  151.949 164.88 152.345 165.576 ;
     RECT  151.729 202.704 152.345 206.328 ;
     RECT  152.017 216.912 152.345 217.752 ;
     RECT  151.379 182.448 152.377 183.432 ;
     RECT  151.949 169.2 152.417 170.808 ;
     RECT  152.195 224.64 152.417 224.664 ;
     RECT  152.125 159.984 152.449 160.152 ;
     RECT  152.197 195.36 152.453 197.112 ;
     RECT  152.345 164.88 152.485 165.336 ;
     RECT  151.945 210 152.521 210.024 ;
     RECT  151.553 192.432 152.525 193.224 ;
     RECT  152.485 164.544 152.531 165.336 ;
     RECT  152.053 153.984 152.557 155.496 ;
     RECT  152.453 195.36 152.557 195.72 ;
     RECT  152.057 172.08 152.561 172.92 ;
     RECT  152.377 182.352 152.561 183.432 ;
     RECT  152.531 164.544 152.572 165.288 ;
     RECT  152.345 206.064 152.593 206.328 ;
     RECT  151.697 201.6 152.629 201.624 ;
     RECT  152.345 202.704 152.629 204.6 ;
     RECT  151.445 161.904 152.636 161.928 ;
     RECT  152.636 161.712 152.677 161.928 ;
     RECT  152.237 180.144 152.677 181.08 ;
     RECT  152.561 182.928 152.732 183.432 ;
     RECT  152.201 184.656 152.732 188.376 ;
     RECT  152.345 216.912 152.773 216.936 ;
     RECT  152.521 219.936 152.773 219.96 ;
     RECT  152.149 220.992 152.773 221.592 ;
     RECT  152.629 201.6 153.061 204.6 ;
     RECT  152.677 161.712 153.164 162.216 ;
     RECT  152.201 189.984 153.169 191.016 ;
     RECT  152.453 196.896 153.169 197.112 ;
     RECT  149.933 198.096 153.169 198.12 ;
     RECT  153.169 189.984 153.277 191.256 ;
     RECT  152.525 192.432 153.277 192.456 ;
     RECT  152.701 213.744 153.313 213.768 ;
     RECT  151.909 218.88 153.349 218.904 ;
     RECT  152.773 219.936 153.349 221.592 ;
     RECT  153.061 201.264 153.404 204.6 ;
     RECT  152.417 170.4 153.421 170.808 ;
     RECT  153.421 229.68 153.457 229.704 ;
     RECT  153.164 161.712 153.493 163.032 ;
     RECT  152.521 210 153.493 210.168 ;
     RECT  152.053 174.432 153.529 176.136 ;
     RECT  152.732 182.928 153.529 188.376 ;
     RECT  152.572 165.072 153.565 165.288 ;
     RECT  153.529 182.592 153.601 188.376 ;
     RECT  153.277 189.984 153.601 192.456 ;
     RECT  151.561 150.816 153.608 150.84 ;
     RECT  152.725 152.064 153.608 153 ;
     RECT  152.557 153.984 153.608 155.64 ;
     RECT  152.809 158.448 153.608 158.568 ;
     RECT  152.449 159.744 153.608 160.152 ;
     RECT  153.493 161.712 153.608 163.992 ;
     RECT  153.565 165.072 153.608 166.152 ;
     RECT  151.265 167.472 153.608 167.592 ;
     RECT  152.417 169.248 153.608 169.416 ;
     RECT  153.421 170.4 153.608 171.624 ;
     RECT  152.561 172.896 153.608 172.92 ;
     RECT  153.529 174.432 153.608 176.184 ;
     RECT  152.305 177.216 153.608 178.824 ;
     RECT  152.677 180.144 153.608 181.368 ;
     RECT  153.601 182.592 153.608 192.456 ;
     RECT  153.205 193.44 153.608 193.464 ;
     RECT  152.557 195.168 153.608 195.72 ;
     RECT  153.169 196.896 153.608 198.12 ;
     RECT  151.769 199.584 153.608 199.608 ;
     RECT  153.404 201.264 153.608 204.984 ;
     RECT  152.593 206.064 153.608 206.424 ;
     RECT  153.493 209.952 153.608 210.168 ;
     RECT  153.241 211.776 153.608 211.8 ;
     RECT  153.313 213.744 153.608 214.536 ;
     RECT  152.773 216.624 153.608 216.936 ;
     RECT  153.349 218.88 153.608 221.592 ;
     RECT  152.521 225.696 153.608 226.056 ;
     RECT  153.457 229.68 153.608 230.472 ;
     RECT  153.349 231.504 153.608 231.528 ;
     RECT  153.608 2.148 153.712 369.372 ;
     RECT  153.712 2.418 153.904 369.102 ;
     RECT  153.904 165.072 153.929 167.736 ;
     RECT  153.904 211.776 153.929 211.8 ;
     RECT  153.904 230.448 153.929 230.472 ;
     RECT  153.904 181.488 153.965 192.504 ;
     RECT  153.904 152.976 154.037 153.48 ;
     RECT  153.904 177.408 154.037 180.216 ;
     RECT  153.904 208.608 154.073 208.632 ;
     RECT  153.904 174 154.109 176.184 ;
     RECT  153.904 213.12 154.163 214.92 ;
     RECT  153.904 220.128 154.181 221.592 ;
     RECT  153.965 184.848 154.253 192.504 ;
     RECT  154.037 177.408 154.307 178.968 ;
     RECT  154.109 174 154.325 176.136 ;
     RECT  154.037 152.976 154.397 153.24 ;
     RECT  154.253 184.848 154.433 191.256 ;
     RECT  154.163 213.12 154.505 214.632 ;
     RECT  153.904 170.4 154.613 173.016 ;
     RECT  153.904 196.464 154.613 200.52 ;
     RECT  153.904 218.64 154.613 218.664 ;
     RECT  153.929 165.936 154.685 167.736 ;
     RECT  154.397 153.216 154.721 153.24 ;
     RECT  154.307 177.408 154.721 178.296 ;
     RECT  154.037 180.144 154.721 180.216 ;
     RECT  154.433 184.848 154.721 191.112 ;
     RECT  154.685 165.936 154.739 165.96 ;
     RECT  153.904 201.6 154.78 201.624 ;
     RECT  154.253 192.432 154.829 192.504 ;
     RECT  153.904 193.632 154.829 193.656 ;
     RECT  154.613 196.464 154.829 198.408 ;
     RECT  154.325 174 154.865 175.176 ;
     RECT  153.904 160.848 154.937 162.456 ;
     RECT  153.904 155.376 154.969 155.4 ;
     RECT  153.904 202.896 154.973 203.4 ;
     RECT  153.904 228.576 154.973 228.6 ;
     RECT  154.685 166.992 154.981 167.736 ;
     RECT  154.613 170.4 154.981 170.472 ;
     RECT  154.829 196.464 154.997 198.36 ;
     RECT  154.969 155.376 155.009 155.592 ;
     RECT  153.965 181.488 155.009 183.528 ;
     RECT  154.981 166.992 155.027 168.072 ;
     RECT  153.904 206.064 155.041 206.088 ;
     RECT  155.009 182.592 155.045 183.528 ;
     RECT  154.981 169.872 155.068 170.472 ;
     RECT  154.181 220.272 155.075 221.448 ;
     RECT  154.997 196.032 155.081 198.36 ;
     RECT  154.613 199.488 155.113 200.52 ;
     RECT  155.075 220.992 155.116 221.448 ;
     RECT  154.937 161.376 155.153 162.456 ;
     RECT  154.613 172.128 155.153 173.016 ;
     RECT  154.721 180.192 155.153 180.216 ;
     RECT  153.904 204.48 155.153 204.504 ;
     RECT  155.068 170.448 155.171 170.472 ;
     RECT  154.829 192.432 155.257 192.456 ;
     RECT  155.045 182.736 155.261 183.528 ;
     RECT  153.904 226.704 155.261 226.728 ;
     RECT  155.081 196.944 155.267 198.36 ;
     RECT  155.113 199.488 155.267 200.664 ;
     RECT  154.865 174 155.297 174.408 ;
     RECT  153.904 225.6 155.297 225.624 ;
     RECT  155.153 161.568 155.333 162.456 ;
     RECT  155.333 162.192 155.405 162.456 ;
     RECT  155.009 155.568 155.411 155.592 ;
     RECT  155.324 158.544 155.411 158.568 ;
     RECT  155.221 159.6 155.411 159.624 ;
     RECT  155.267 197.184 155.477 198.36 ;
     RECT  155.267 199.488 155.507 199.512 ;
     RECT  155.297 174 155.513 174.12 ;
     RECT  155.477 198.336 155.521 198.36 ;
     RECT  153.904 207.408 155.549 207.528 ;
     RECT  155.153 172.176 155.581 173.016 ;
     RECT  154.505 213.12 155.581 214.008 ;
     RECT  154.721 177.408 155.605 177.432 ;
     RECT  155.605 176.688 155.651 177.432 ;
     RECT  153.904 210.384 155.653 210.408 ;
     RECT  155.651 176.688 155.693 176.712 ;
     RECT  155.653 210.384 155.797 210.936 ;
     RECT  155.581 213.12 155.837 214.488 ;
     RECT  155.549 207.456 155.845 207.528 ;
     RECT  155.077 217.488 155.873 217.512 ;
     RECT  155.797 210.336 155.891 210.936 ;
     RECT  154.721 184.848 155.905 189.384 ;
     RECT  154.721 190.512 155.905 191.112 ;
     RECT  155.113 194.592 155.905 194.616 ;
     RECT  155.837 213.12 155.909 214.008 ;
     RECT  155.905 184.848 155.981 191.112 ;
     RECT  154.973 203.376 155.981 203.4 ;
     RECT  155.891 210.336 155.981 210.84 ;
     RECT  155.581 172.176 156.053 173.256 ;
     RECT  155.581 216.432 156.053 216.456 ;
     RECT  155.981 210.336 156.089 210.36 ;
     RECT  155.909 213.12 156.125 213.144 ;
     RECT  155.905 194.4 156.157 194.616 ;
     RECT  155.905 209.184 156.157 209.208 ;
     RECT  155.077 163.872 156.197 163.896 ;
     RECT  155.981 184.848 156.197 189.672 ;
     RECT  155.845 207.456 156.301 208.056 ;
     RECT  156.301 207.456 156.341 208.104 ;
     RECT  155.653 212.016 156.377 212.04 ;
     RECT  156.053 172.752 156.413 173.256 ;
     RECT  155.041 206.064 156.445 206.136 ;
     RECT  155.027 167.712 156.481 168.072 ;
     RECT  156.373 176.208 156.485 176.232 ;
     RECT  156.157 194.4 156.517 195.432 ;
     RECT  156.445 206.064 156.517 206.472 ;
     RECT  156.157 209.184 156.521 209.304 ;
     RECT  156.197 184.848 156.524 189.192 ;
     RECT  156.481 167.136 156.553 168.072 ;
     RECT  156.521 209.184 156.557 209.208 ;
     RECT  156.517 205.632 156.563 206.472 ;
     RECT  155.261 182.736 156.565 183 ;
     RECT  156.565 182.592 156.611 183 ;
     RECT  156.524 184.416 156.611 189.192 ;
     RECT  156.517 173.472 156.629 173.496 ;
     RECT  156.553 166.608 156.845 168.072 ;
     RECT  156.517 194.4 156.845 195.624 ;
     RECT  156.845 194.4 156.86 194.616 ;
     RECT  156.845 167.136 156.877 168.072 ;
     RECT  155.725 169.392 156.877 169.416 ;
     RECT  155.116 220.992 156.877 221.016 ;
     RECT  156.341 208.032 156.881 208.104 ;
     RECT  156.625 163.68 156.917 163.704 ;
     RECT  156.563 205.632 156.917 205.656 ;
     RECT  156.86 194.352 156.947 194.616 ;
     RECT  156.121 222.24 156.995 222.264 ;
     RECT  156.877 220.896 157.057 221.016 ;
     RECT  155.257 192.096 157.141 192.456 ;
     RECT  157.057 220.56 157.169 221.016 ;
     RECT  157.141 192.096 157.205 192.648 ;
     RECT  156.845 195.6 157.205 195.624 ;
     RECT  157.021 214.272 157.241 214.296 ;
     RECT  155.477 197.184 157.285 197.208 ;
     RECT  157.285 197.184 157.331 197.448 ;
     RECT  156.733 165.408 157.349 165.432 ;
     RECT  156.877 167.136 157.565 169.416 ;
     RECT  156.193 224.976 157.565 225 ;
     RECT  156.697 201.216 157.709 201.24 ;
     RECT  157.381 204.48 157.777 204.504 ;
     RECT  157.633 170.448 157.781 170.472 ;
     RECT  157.565 167.136 157.817 169.32 ;
     RECT  157.817 167.136 157.849 168.84 ;
     RECT  156.121 216.96 157.889 216.984 ;
     RECT  157.169 220.896 157.889 221.016 ;
     RECT  157.705 202.368 157.961 202.392 ;
     RECT  157.849 212.832 158.029 212.856 ;
     RECT  157.741 174.384 158.101 174.408 ;
     RECT  156.947 194.592 158.101 194.616 ;
     RECT  155.981 190.656 158.137 191.112 ;
     RECT  157.777 204.48 158.317 204.552 ;
     RECT  158.245 214.272 158.317 214.296 ;
     RECT  158.029 212.736 158.425 212.856 ;
     RECT  158.281 175.584 158.461 175.608 ;
     RECT  158.137 172.704 158.497 172.728 ;
     RECT  158.101 173.904 158.497 174.408 ;
     RECT  158.425 211.776 158.497 212.856 ;
     RECT  158.317 213.936 158.497 214.296 ;
     RECT  158.101 194.592 158.533 194.856 ;
     RECT  158.065 198.624 158.641 198.648 ;
     RECT  157.331 197.28 158.677 197.448 ;
     RECT  158.641 198.624 158.677 199.128 ;
     RECT  158.137 190.32 158.684 191.112 ;
     RECT  156.611 182.592 158.713 182.616 ;
     RECT  156.611 184.656 158.725 189.192 ;
     RECT  158.684 190.32 158.725 191.256 ;
     RECT  158.497 172.704 158.732 174.408 ;
     RECT  158.461 175.584 158.732 175.656 ;
     RECT  158.677 209.856 158.749 209.88 ;
     RECT  158.461 177.792 158.857 177.816 ;
     RECT  155.009 181.488 158.869 181.512 ;
     RECT  158.713 182.592 158.869 182.952 ;
     RECT  157.205 192.432 158.869 192.648 ;
     RECT  158.533 194.4 158.869 194.856 ;
     RECT  158.029 165.648 159.001 165.672 ;
     RECT  155.405 162.192 159.008 162.216 ;
     RECT  159.001 165.072 159.008 165.672 ;
     RECT  157.849 166.704 159.008 168.84 ;
     RECT  158.461 170.352 159.008 170.376 ;
     RECT  158.732 172.704 159.008 175.656 ;
     RECT  158.857 177.024 159.008 177.816 ;
     RECT  158.869 181.488 159.008 182.952 ;
     RECT  158.725 184.656 159.008 191.256 ;
     RECT  158.869 192.432 159.008 192.984 ;
     RECT  158.869 194.016 159.008 194.856 ;
     RECT  158.677 197.28 159.008 199.128 ;
     RECT  158.821 200.976 159.008 201 ;
     RECT  158.317 202.656 159.008 202.68 ;
     RECT  158.317 204.336 159.008 204.552 ;
     RECT  158.497 205.824 159.008 205.848 ;
     RECT  156.881 208.032 159.008 208.056 ;
     RECT  158.749 209.856 159.008 209.928 ;
     RECT  158.497 211.776 159.008 214.296 ;
     RECT  158.497 216.096 159.008 216.12 ;
     RECT  156.949 219.408 159.008 219.432 ;
     RECT  157.889 220.992 159.008 221.016 ;
     RECT  159.008 2.148 159.112 369.372 ;
     RECT  159.112 2.418 159.304 369.102 ;
     RECT  159.304 203.568 159.401 206.376 ;
     RECT  159.304 212.256 159.401 212.856 ;
     RECT  159.304 197.424 159.443 199.368 ;
     RECT  159.304 201.504 159.443 202.296 ;
     RECT  159.304 214.272 159.473 214.296 ;
     RECT  159.304 165.072 159.491 165.096 ;
     RECT  159.304 166.752 159.532 167.016 ;
     RECT  159.304 207.6 159.617 208.728 ;
     RECT  159.304 194.016 159.653 195.48 ;
     RECT  159.443 197.424 159.725 198.408 ;
     RECT  159.653 194.016 159.869 194.376 ;
     RECT  159.304 171.504 159.875 172.632 ;
     RECT  159.875 171.936 159.916 171.96 ;
     RECT  159.653 195.456 159.923 195.48 ;
     RECT  159.304 218.88 159.923 218.904 ;
     RECT  159.304 180.144 159.941 180.168 ;
     RECT  159.401 205.344 159.941 206.376 ;
     RECT  159.401 212.256 159.977 212.616 ;
     RECT  159.304 182.592 160.049 182.952 ;
     RECT  159.617 208.032 160.067 208.728 ;
     RECT  159.304 190.656 160.121 192.792 ;
     RECT  160.049 182.928 160.193 182.952 ;
     RECT  159.304 209.856 160.337 210.408 ;
     RECT  160.337 209.856 160.373 209.88 ;
     RECT  159.977 212.256 160.373 212.376 ;
     RECT  159.304 184.848 160.409 189.192 ;
     RECT  159.532 166.992 160.501 167.016 ;
     RECT  160.373 212.352 160.517 212.376 ;
     RECT  160.501 166.224 160.588 167.016 ;
     RECT  159.401 203.568 160.621 204.072 ;
     RECT  160.067 208.032 160.661 208.584 ;
     RECT  159.304 168.048 160.697 168.072 ;
     RECT  160.621 203.568 160.733 204.552 ;
     RECT  159.304 169.872 160.741 169.896 ;
     RECT  159.725 197.424 160.769 198.312 ;
     RECT  160.741 169.872 160.805 170.328 ;
     RECT  160.805 170.304 160.828 170.328 ;
     RECT  160.121 190.656 160.841 192.072 ;
     RECT  160.733 203.76 160.841 204.072 ;
     RECT  159.941 206.304 160.841 206.376 ;
     RECT  160.741 173.856 160.877 173.88 ;
     RECT  159.869 194.016 160.909 194.04 ;
     RECT  160.588 166.992 160.913 167.016 ;
     RECT  160.409 184.848 160.945 188.376 ;
     RECT  160.841 204.048 160.949 204.072 ;
     RECT  160.769 198.24 161.089 198.312 ;
     RECT  160.909 193.824 161.161 194.04 ;
     RECT  160.945 183.888 161.273 188.376 ;
     RECT  159.443 202.272 161.381 202.296 ;
     RECT  161.089 198.24 161.417 198.984 ;
     RECT  161.161 193.152 161.489 194.04 ;
     RECT  161.341 200.16 161.597 200.184 ;
     RECT  161.417 198.24 161.669 198.888 ;
     RECT  161.66 194.208 161.701 194.232 ;
     RECT  161.701 194.208 161.747 195.144 ;
     RECT  160.841 190.656 161.765 192.024 ;
     RECT  160.841 206.304 161.809 206.328 ;
     RECT  161.489 193.152 161.843 193.176 ;
     RECT  160.981 196.56 161.845 196.728 ;
     RECT  161.765 190.32 161.849 192.024 ;
     RECT  160.945 207.648 161.921 207.672 ;
     RECT  161.845 196.56 161.957 197.16 ;
     RECT  161.809 205.92 161.957 206.328 ;
     RECT  161.669 198.24 161.989 198.408 ;
     RECT  161.989 197.376 162.035 198.408 ;
     RECT  161.747 195.12 162.076 195.144 ;
     RECT  161.989 196.224 162.076 196.248 ;
     RECT  161.989 202.368 162.101 202.392 ;
     RECT  162.035 197.376 162.497 197.4 ;
     RECT  161.957 205.92 162.713 205.944 ;
     RECT  162.565 189.6 162.821 189.624 ;
     RECT  161.849 190.656 162.929 192.024 ;
     RECT  159.304 162.192 164.408 162.216 ;
     RECT  159.304 181.488 164.408 181.512 ;
     RECT  161.273 184.848 164.408 188.376 ;
     RECT  162.929 190.656 164.408 191.112 ;
     RECT  164.408 2.148 164.512 369.372 ;
     RECT  164.512 2.418 164.704 369.102 ;
     RECT  164.704 184.992 165.233 186.456 ;
     RECT  164.704 187.44 165.841 188.376 ;
     RECT  164.704 162.192 166.421 162.216 ;
     RECT  166.957 162.336 169.808 162.36 ;
     RECT  164.704 181.488 169.808 181.512 ;
     RECT  165.233 184.992 169.808 185.64 ;
     RECT  165.841 186.624 169.808 188.376 ;
     RECT  164.704 190.656 169.808 191.112 ;
     RECT  169.808 2.148 169.912 369.372 ;
     RECT  169.912 2.418 170.104 369.102 ;
     RECT  170.104 181.776 170.785 181.8 ;
     RECT  170.104 162.336 175.208 162.36 ;
     RECT  170.104 184.992 175.208 185.64 ;
     RECT  170.104 186.624 175.208 188.376 ;
     RECT  170.104 190.656 175.208 191.112 ;
     RECT  175.208 2.148 175.312 369.372 ;
     RECT  175.312 2.418 175.504 369.102 ;
     RECT  175.504 162.336 180.608 162.36 ;
     RECT  175.504 184.992 180.608 185.64 ;
     RECT  175.504 186.624 180.608 188.376 ;
     RECT  175.504 190.656 180.608 191.112 ;
     RECT  180.608 2.148 180.712 369.372 ;
     RECT  180.712 2.418 180.904 369.102 ;
     RECT  180.904 162.336 186.008 162.36 ;
     RECT  180.904 184.992 186.008 185.64 ;
     RECT  180.904 186.624 186.008 188.376 ;
     RECT  180.904 190.656 186.008 191.112 ;
     RECT  186.008 2.148 186.112 369.372 ;
     RECT  186.112 2.418 186.304 369.102 ;
     RECT  186.304 162.336 191.408 162.36 ;
     RECT  186.304 184.992 191.408 185.64 ;
     RECT  186.304 186.624 191.408 188.376 ;
     RECT  186.304 190.656 191.408 191.112 ;
     RECT  191.408 2.148 191.512 369.372 ;
     RECT  191.512 2.418 191.704 369.102 ;
     RECT  191.704 162.336 196.808 162.36 ;
     RECT  191.704 184.992 196.808 185.64 ;
     RECT  191.704 186.624 196.808 188.376 ;
     RECT  191.704 190.656 196.808 191.112 ;
     RECT  196.808 2.148 196.912 369.372 ;
     RECT  196.912 2.418 197.104 369.102 ;
     RECT  197.104 162.336 202.208 162.36 ;
     RECT  197.104 184.992 202.208 185.64 ;
     RECT  197.104 186.624 202.208 188.376 ;
     RECT  197.104 190.656 202.208 191.112 ;
     RECT  202.208 2.148 202.312 369.372 ;
     RECT  202.312 2.418 202.504 369.102 ;
     RECT  202.504 162.336 207.608 162.36 ;
     RECT  202.504 184.992 207.608 185.64 ;
     RECT  202.504 186.624 207.608 188.376 ;
     RECT  202.504 190.656 207.608 191.112 ;
     RECT  207.608 2.148 207.712 369.372 ;
     RECT  207.712 2.418 207.904 369.102 ;
     RECT  207.904 162.336 213.008 162.36 ;
     RECT  207.904 184.992 213.008 185.64 ;
     RECT  207.904 186.624 213.008 188.376 ;
     RECT  207.904 190.656 213.008 191.112 ;
     RECT  213.008 2.148 213.112 369.372 ;
     RECT  213.112 2.418 213.304 369.102 ;
     RECT  213.304 162.336 218.408 162.36 ;
     RECT  213.304 184.992 218.408 185.64 ;
     RECT  213.304 186.624 218.408 188.376 ;
     RECT  213.304 190.656 218.408 191.112 ;
     RECT  218.408 2.148 218.512 369.372 ;
     RECT  218.512 2.418 218.704 369.102 ;
     RECT  218.704 162.336 223.808 162.36 ;
     RECT  218.704 184.992 223.808 185.64 ;
     RECT  218.704 186.624 223.808 188.376 ;
     RECT  218.704 190.656 223.808 191.112 ;
     RECT  223.808 2.148 223.912 369.372 ;
     RECT  223.912 2.418 224.104 369.102 ;
     RECT  224.104 162.336 229.208 162.36 ;
     RECT  224.104 184.992 229.208 185.64 ;
     RECT  224.104 186.624 229.208 188.376 ;
     RECT  224.104 190.656 229.208 191.112 ;
     RECT  229.208 2.148 229.312 369.372 ;
     RECT  229.312 2.418 229.504 369.102 ;
     RECT  229.504 162.336 234.608 162.36 ;
     RECT  229.504 184.992 234.608 185.64 ;
     RECT  229.504 186.624 234.608 188.376 ;
     RECT  229.504 190.656 234.608 191.112 ;
     RECT  234.608 2.148 234.712 369.372 ;
     RECT  234.712 2.418 234.904 369.102 ;
     RECT  234.904 162.336 240.008 162.36 ;
     RECT  234.904 184.992 240.008 185.64 ;
     RECT  234.904 186.624 240.008 188.376 ;
     RECT  234.904 190.656 240.008 191.112 ;
     RECT  240.008 2.148 240.112 369.372 ;
     RECT  240.112 2.418 240.304 369.102 ;
     RECT  240.304 184.992 244.145 185.64 ;
     RECT  240.304 190.656 244.361 191.112 ;
     RECT  240.304 186.624 244.397 188.376 ;
     RECT  244.397 186.624 244.789 188.04 ;
     RECT  240.304 162.336 245.408 162.36 ;
     RECT  244.145 184.992 245.408 185.016 ;
     RECT  244.789 186.192 245.408 188.04 ;
     RECT  244.361 191.088 245.408 191.112 ;
     RECT  245.408 2.148 245.512 369.372 ;
     RECT  245.512 2.418 245.704 369.102 ;
     RECT  245.704 162.288 246.769 162.504 ;
     RECT  245.704 185.904 246.805 188.712 ;
     RECT  246.769 162 247.381 162.504 ;
     RECT  246.805 185.904 247.381 188.808 ;
     RECT  247.381 162 247.453 162.6 ;
     RECT  247.453 162 248.364 162.696 ;
     RECT  247.381 185.808 248.364 188.808 ;
    LAYER M5 ;
     RECT  2.4 2.137 2.52 2.151 ;
     RECT  7.8 2.137 7.92 2.151 ;
     RECT  13.2 2.137 13.32 2.151 ;
     RECT  18.6 2.137 18.72 2.151 ;
     RECT  24 2.137 24.12 2.151 ;
     RECT  29.4 2.137 29.52 2.151 ;
     RECT  34.8 2.137 34.92 2.151 ;
     RECT  40.2 2.137 40.32 2.151 ;
     RECT  45.6 2.137 45.72 2.151 ;
     RECT  51 2.137 51.12 2.151 ;
     RECT  56.4 2.137 56.52 2.151 ;
     RECT  61.8 2.137 61.92 2.151 ;
     RECT  67.2 2.137 67.32 2.151 ;
     RECT  72.6 2.137 72.72 2.151 ;
     RECT  78 2.137 78.12 2.151 ;
     RECT  83.4 2.137 83.52 2.151 ;
     RECT  88.8 2.137 88.92 2.151 ;
     RECT  94.2 2.137 94.32 2.151 ;
     RECT  99.6 2.137 99.72 2.151 ;
     RECT  105 2.137 105.12 2.151 ;
     RECT  110.4 2.137 110.52 2.151 ;
     RECT  115.8 2.137 115.92 2.151 ;
     RECT  121.2 2.137 121.32 2.151 ;
     RECT  126.6 2.137 126.72 2.151 ;
     RECT  132 2.137 132.12 2.151 ;
     RECT  137.4 2.137 137.52 2.151 ;
     RECT  142.8 2.137 142.92 2.151 ;
     RECT  148.2 2.137 148.32 2.151 ;
     RECT  153.6 2.137 153.72 2.151 ;
     RECT  159 2.137 159.12 2.151 ;
     RECT  164.4 2.137 164.52 2.151 ;
     RECT  169.8 2.137 169.92 2.151 ;
     RECT  175.2 2.137 175.32 2.151 ;
     RECT  180.6 2.137 180.72 2.151 ;
     RECT  186 2.137 186.12 2.151 ;
     RECT  191.4 2.137 191.52 2.151 ;
     RECT  196.8 2.137 196.92 2.151 ;
     RECT  202.2 2.137 202.32 2.151 ;
     RECT  207.6 2.137 207.72 2.151 ;
     RECT  213 2.137 213.12 2.151 ;
     RECT  218.4 2.137 218.52 2.151 ;
     RECT  223.8 2.137 223.92 2.151 ;
     RECT  229.2 2.137 229.32 2.151 ;
     RECT  234.6 2.137 234.72 2.151 ;
     RECT  240 2.137 240.12 2.151 ;
     RECT  245.4 2.137 245.52 2.151 ;
     RECT  144.816 132.517 144.84 133.573 ;
     RECT  144.72 133.573 144.84 133.619 ;
     RECT  144.72 133.619 144.744 135.061 ;
     RECT  144.528 135.061 144.744 135.973 ;
     RECT  142.8 2.151 143.112 136.741 ;
     RECT  137.4 2.151 137.712 136.981 ;
     RECT  137.4 136.981 138.168 137.987 ;
     RECT  137.4 137.987 137.712 139.093 ;
     RECT  132 2.151 132.312 141.301 ;
     RECT  142.032 136.741 143.112 141.301 ;
     RECT  144.528 135.973 144.936 141.301 ;
     RECT  137.088 139.093 137.712 141.395 ;
     RECT  147.024 139.621 147.048 141.541 ;
     RECT  146.928 141.541 147.048 141.587 ;
     RECT  148.2 2.151 148.512 142.933 ;
     RECT  142.032 141.301 144.936 142.979 ;
     RECT  148.2 142.933 149.064 143.029 ;
     RECT  146.928 141.587 146.952 143.219 ;
     RECT  134.88 141.685 134.904 143.653 ;
     RECT  139.632 142.117 139.656 143.699 ;
     RECT  148.2 143.029 149.112 144.275 ;
     RECT  144.528 142.979 144.936 144.469 ;
     RECT  134.88 143.653 135.48 144.515 ;
     RECT  147.024 143.989 147.048 145.859 ;
     RECT  144.528 144.469 145.176 145.861 ;
     RECT  148.2 144.275 149.064 146.387 ;
     RECT  134.88 144.515 134.904 146.485 ;
     RECT  132 141.301 132.84 146.531 ;
     RECT  130.896 144.085 130.92 146.675 ;
     RECT  142.032 142.979 143.112 146.677 ;
     RECT  140.688 142.069 140.712 147.061 ;
     RECT  146.448 145.861 146.472 147.301 ;
     RECT  141.888 146.677 143.112 147.445 ;
     RECT  144.192 145.861 145.176 147.445 ;
     RECT  141.888 147.445 145.464 147.587 ;
     RECT  137.4 141.395 137.712 147.589 ;
     RECT  141.888 147.587 145.176 147.635 ;
     RECT  139.344 145.141 139.368 147.683 ;
     RECT  132 146.531 132.312 148.309 ;
     RECT  146.448 147.301 146.856 148.835 ;
     RECT  140.688 147.061 140.808 149.219 ;
     RECT  133.92 146.485 134.904 149.651 ;
     RECT  137.28 147.589 137.712 149.749 ;
     RECT  148.2 146.387 148.728 149.749 ;
     RECT  137.28 149.749 137.832 149.795 ;
     RECT  134.88 149.651 134.904 150.325 ;
     RECT  140.688 149.219 140.712 150.421 ;
     RECT  142.032 147.635 145.176 150.755 ;
     RECT  153.6 2.151 153.912 150.805 ;
     RECT  131.904 148.309 132.312 150.851 ;
     RECT  148.2 149.749 148.824 150.899 ;
     RECT  139.296 147.925 139.32 150.997 ;
     RECT  140.4 150.421 140.712 150.997 ;
     RECT  132 150.851 132.312 151.573 ;
     RECT  146.448 148.835 146.472 151.573 ;
     RECT  134.88 150.325 135.672 151.619 ;
     RECT  151.488 150.421 151.512 151.859 ;
     RECT  152.928 150.805 153.912 152.053 ;
     RECT  146.448 151.573 147.096 152.485 ;
     RECT  148.2 150.899 148.728 152.485 ;
     RECT  137.4 149.795 137.832 152.725 ;
     RECT  142.032 150.755 144.792 152.725 ;
     RECT  146.448 152.485 148.728 152.725 ;
     RECT  136.56 152.725 137.832 152.771 ;
     RECT  142.032 152.725 148.728 153.157 ;
     RECT  129.216 150.853 129.24 153.395 ;
     RECT  139.296 150.997 140.712 153.683 ;
     RECT  139.296 153.683 139.32 153.923 ;
     RECT  132 151.573 132.408 153.925 ;
     RECT  142.032 153.157 148.824 153.973 ;
     RECT  152.736 152.053 153.912 153.973 ;
     RECT  132 153.925 133.32 154.019 ;
     RECT  152.256 153.973 153.912 154.019 ;
     RECT  152.256 154.019 152.28 154.451 ;
     RECT  136.56 152.771 137.712 154.501 ;
     RECT  136.224 154.501 137.832 154.547 ;
     RECT  137.4 154.547 137.832 154.741 ;
     RECT  142.032 153.973 148.92 155.075 ;
     RECT  150.48 154.981 150.504 155.173 ;
     RECT  134.88 151.619 134.904 155.269 ;
     RECT  134.88 155.269 135.096 155.315 ;
     RECT  130.56 153.877 130.872 155.459 ;
     RECT  130.56 155.459 130.728 155.651 ;
     RECT  134.928 155.315 135.096 155.651 ;
     RECT  149.856 155.173 150.504 155.651 ;
     RECT  150.288 155.651 150.504 155.699 ;
     RECT  136.224 154.547 136.248 156.085 ;
     RECT  136.128 156.085 136.248 156.131 ;
     RECT  137.4 154.741 137.88 156.371 ;
     RECT  150.288 155.699 150.312 157.235 ;
     RECT  136.128 156.131 136.152 157.475 ;
     RECT  134.928 155.651 134.952 157.861 ;
     RECT  140.4 153.683 140.712 157.861 ;
     RECT  134.928 157.861 135.336 158.003 ;
     RECT  121.2 2.151 121.512 158.149 ;
     RECT  140.352 157.861 140.712 158.197 ;
     RECT  129.456 156.037 129.48 158.389 ;
     RECT  130.56 155.651 130.584 158.389 ;
     RECT  125.424 156.709 125.448 158.531 ;
     RECT  135.312 158.003 135.336 158.581 ;
     RECT  142.032 155.075 148.824 158.869 ;
     RECT  133.296 154.019 133.32 158.917 ;
     RECT  123.168 158.149 123.192 159.011 ;
     RECT  129.456 158.389 130.584 159.107 ;
     RECT  120.864 158.149 121.512 159.395 ;
     RECT  132 154.019 132.312 159.397 ;
     RECT  133.296 158.917 134.232 159.397 ;
     RECT  155.376 155.557 155.4 159.635 ;
     RECT  135.312 158.581 135.384 160.163 ;
     RECT  130.512 159.107 130.584 160.211 ;
     RECT  132 159.397 134.232 160.211 ;
     RECT  123.312 159.541 123.336 160.309 ;
     RECT  130.56 160.211 130.584 161.317 ;
     RECT  130.56 161.317 130.824 161.363 ;
     RECT  141.84 158.869 148.824 161.363 ;
     RECT  121.2 159.395 121.512 161.653 ;
     RECT  153.6 154.019 153.912 161.701 ;
     RECT  126.6 2.151 126.912 161.797 ;
     RECT  129.456 159.107 129.48 161.797 ;
     RECT  139.536 158.197 140.712 161.845 ;
     RECT  141.84 161.363 146.952 161.891 ;
     RECT  152.688 161.701 153.912 162.227 ;
     RECT  141.84 161.891 146.472 162.277 ;
     RECT  141.792 162.277 146.472 162.419 ;
     RECT  148.2 161.363 148.824 162.421 ;
     RECT  153.216 162.227 153.912 162.421 ;
     RECT  129.456 161.797 129.72 162.467 ;
     RECT  126.6 161.797 127.704 162.515 ;
     RECT  121.2 161.653 121.608 162.995 ;
     RECT  123.312 160.309 123.816 163.043 ;
     RECT  138.96 161.845 140.712 163.141 ;
     RECT  151.392 161.893 151.416 163.283 ;
     RECT  125.424 162.421 125.448 163.333 ;
     RECT  124.848 163.333 125.448 163.379 ;
     RECT  135.312 160.163 135.336 163.381 ;
     RECT  141.84 162.419 146.472 163.525 ;
     RECT  132 160.211 133.32 163.571 ;
     RECT  141.84 163.525 147.048 163.765 ;
     RECT  148.2 162.421 148.872 163.765 ;
     RECT  129.456 162.467 129.48 163.861 ;
     RECT  141.84 163.765 148.872 164.195 ;
     RECT  141.984 164.195 148.872 164.533 ;
     RECT  153.216 162.421 154.728 164.533 ;
     RECT  123.312 163.043 123.336 164.869 ;
     RECT  137.4 156.371 137.712 164.869 ;
     RECT  134.544 163.381 135.336 164.915 ;
     RECT  123.12 164.869 123.336 165.011 ;
     RECT  124.848 163.379 124.872 165.013 ;
     RECT  128.592 163.861 129.48 165.013 ;
     RECT  130.8 161.363 130.824 165.013 ;
     RECT  123.312 165.011 123.336 165.059 ;
     RECT  128.592 165.013 130.824 165.059 ;
     RECT  159 2.151 159.312 165.061 ;
     RECT  129.936 165.059 130.824 165.203 ;
     RECT  128.592 165.059 128.616 165.347 ;
     RECT  152.496 164.533 154.728 165.347 ;
     RECT  136.896 164.869 137.712 165.349 ;
     RECT  138.816 163.141 140.712 165.349 ;
     RECT  136.896 165.349 140.712 165.923 ;
     RECT  141.984 164.533 149.352 165.971 ;
     RECT  153.216 165.347 154.728 165.971 ;
     RECT  132 163.571 133.176 166.213 ;
     RECT  124.848 165.013 125.352 166.355 ;
     RECT  148.08 165.971 149.352 166.499 ;
     RECT  130.608 165.203 130.824 166.693 ;
     RECT  135.312 164.915 135.336 166.741 ;
     RECT  160.512 166.213 160.536 167.027 ;
     RECT  153.216 165.971 153.912 167.557 ;
     RECT  125.328 166.355 125.352 167.603 ;
     RECT  153.216 167.557 154.008 167.603 ;
     RECT  118.704 167.029 118.728 167.987 ;
     RECT  159 165.061 159.48 168.083 ;
     RECT  131.904 166.213 133.176 168.275 ;
     RECT  141.984 165.971 147.048 168.275 ;
     RECT  137.4 165.923 137.712 168.661 ;
     RECT  138.816 165.923 140.712 168.661 ;
     RECT  130.56 166.693 130.824 168.755 ;
     RECT  132 168.275 133.176 169.045 ;
     RECT  134.256 165.013 134.28 169.045 ;
     RECT  132 169.045 134.28 169.189 ;
     RECT  135.312 166.741 135.816 169.189 ;
     RECT  132 169.189 135.816 169.235 ;
     RECT  126.6 162.515 126.912 169.237 ;
     RECT  137.4 168.661 140.712 169.333 ;
     RECT  142.032 168.275 147.048 169.333 ;
     RECT  154.992 166.981 155.016 169.907 ;
     RECT  137.4 169.333 147.048 170.197 ;
     RECT  119.28 168.661 119.304 170.293 ;
     RECT  123.504 168.661 123.528 170.483 ;
     RECT  132 169.235 135.336 170.773 ;
     RECT  136.752 170.197 147.048 170.869 ;
     RECT  148.2 166.499 149.352 170.869 ;
     RECT  119.136 170.293 119.304 171.011 ;
     RECT  122.496 169.237 122.52 171.251 ;
     RECT  153.6 167.603 154.008 171.349 ;
     RECT  155.136 170.437 155.16 171.349 ;
     RECT  121.2 162.995 121.512 171.493 ;
     RECT  159 168.083 159.312 171.493 ;
     RECT  160.752 170.293 160.776 171.493 ;
     RECT  136.752 170.869 149.352 171.589 ;
     RECT  125.088 170.965 125.112 171.779 ;
     RECT  132 170.773 135.672 171.877 ;
     RECT  136.704 171.589 149.352 171.877 ;
     RECT  151.68 169.813 151.704 172.067 ;
     RECT  126.6 169.237 127.656 172.163 ;
     RECT  132 171.877 149.352 172.163 ;
     RECT  153.6 171.349 155.16 172.163 ;
     RECT  155.136 172.163 155.16 172.211 ;
     RECT  119.28 171.011 119.304 172.597 ;
     RECT  121.2 171.493 121.992 173.411 ;
     RECT  150.528 166.645 150.552 173.507 ;
     RECT  159 171.493 160.776 173.891 ;
     RECT  119.28 172.597 119.4 173.939 ;
     RECT  117.936 173.221 117.96 173.987 ;
     RECT  129.36 172.117 129.384 174.181 ;
     RECT  128.88 174.181 129.384 174.227 ;
     RECT  130.8 168.755 130.824 174.325 ;
     RECT  132 172.163 147.048 174.325 ;
     RECT  115.8 2.151 116.112 174.373 ;
     RECT  121.2 173.411 121.512 174.373 ;
     RECT  153.6 172.163 154.008 174.421 ;
     RECT  130.8 174.325 147.048 174.467 ;
     RECT  150.48 173.797 150.504 174.467 ;
     RECT  132 174.467 147.048 174.517 ;
     RECT  148.2 172.163 149.352 174.517 ;
     RECT  152.928 174.421 154.008 174.949 ;
     RECT  128.88 174.227 128.904 174.995 ;
     RECT  159 173.891 159.864 174.997 ;
     RECT  115.8 174.373 116.28 175.043 ;
     RECT  158.784 174.997 159.864 175.139 ;
     RECT  119.28 173.939 119.304 175.573 ;
     RECT  123.216 173.221 123.24 175.573 ;
     RECT  119.136 175.573 119.304 175.619 ;
     RECT  119.136 175.619 119.16 175.763 ;
     RECT  123.12 175.573 123.24 175.813 ;
     RECT  123.12 175.813 123.672 175.859 ;
     RECT  132 174.517 149.352 176.389 ;
     RECT  120.864 174.373 121.512 176.675 ;
     RECT  126.6 172.163 126.912 176.677 ;
     RECT  128.16 175.525 128.664 176.677 ;
     RECT  126.6 176.677 128.664 176.723 ;
     RECT  130.8 174.467 130.824 176.723 ;
     RECT  128.64 176.723 128.664 176.915 ;
     RECT  152.928 174.949 154.296 177.205 ;
     RECT  126.6 176.723 127.368 177.347 ;
     RECT  155.616 176.677 155.64 177.443 ;
     RECT  0.144 178.069 0.168 178.355 ;
     RECT  128.256 177.829 128.28 178.357 ;
     RECT  121.2 176.675 121.512 178.933 ;
     RECT  125.52 178.405 125.544 178.979 ;
     RECT  127.92 178.357 128.28 179.075 ;
     RECT  152.112 177.205 154.296 179.603 ;
     RECT  121.104 178.933 121.512 179.651 ;
     RECT  159 175.139 159.864 180.179 ;
     RECT  152.928 179.603 154.296 180.565 ;
     RECT  152.784 180.565 154.296 180.613 ;
     RECT  123.648 175.859 123.672 181.237 ;
     RECT  152.688 180.613 154.296 181.379 ;
     RECT  120.096 178.357 120.12 181.475 ;
     RECT  117.936 180.661 117.96 181.523 ;
     RECT  169.8 2.151 170.112 181.765 ;
     RECT  122.976 181.237 123.672 181.811 ;
     RECT  124.704 181.237 124.728 181.859 ;
     RECT  122.976 181.811 123.144 182.003 ;
     RECT  132 176.389 149.928 182.147 ;
     RECT  159 180.179 159.312 182.389 ;
     RECT  119.712 181.525 119.736 182.435 ;
     RECT  132 182.147 149.496 182.483 ;
     RECT  158.88 182.389 159.312 182.917 ;
     RECT  158.88 182.917 160.152 182.963 ;
     RECT  152.784 181.379 154.296 183.011 ;
     RECT  121.2 179.651 121.512 183.253 ;
     RECT  126.6 177.347 126.912 183.397 ;
     RECT  127.92 179.075 127.944 183.397 ;
     RECT  126.6 183.397 127.944 183.443 ;
     RECT  115.8 175.043 116.112 183.493 ;
     RECT  132 182.483 149.4 183.781 ;
     RECT  131.808 183.781 149.4 183.829 ;
     RECT  115.8 183.493 116.28 184.355 ;
     RECT  156.576 182.581 156.6 184.451 ;
     RECT  152.784 183.011 153.912 184.691 ;
     RECT  120.864 183.253 121.512 184.787 ;
     RECT  151.344 184.069 151.368 184.883 ;
     RECT  159 182.963 160.152 185.125 ;
     RECT  119.28 184.309 119.304 185.411 ;
     RECT  126.6 183.443 127.704 185.461 ;
     RECT  131.712 183.829 149.4 185.653 ;
     RECT  150.672 185.221 150.696 185.653 ;
     RECT  114.576 182.821 114.6 185.843 ;
     RECT  126.6 185.461 127.848 186.131 ;
     RECT  158.88 185.125 160.152 186.131 ;
     RECT  123.12 182.003 123.144 186.227 ;
     RECT  121.2 184.787 121.512 186.325 ;
     RECT  119.04 186.277 119.064 186.467 ;
     RECT  131.712 185.653 150.696 186.467 ;
     RECT  131.712 186.467 150.168 186.469 ;
     RECT  131.52 186.469 150.168 186.709 ;
     RECT  125.328 183.253 125.352 186.947 ;
     RECT  121.2 186.325 121.992 186.995 ;
     RECT  169.8 181.765 170.76 187.187 ;
     RECT  121.2 186.995 121.512 187.285 ;
     RECT  131.232 186.709 150.168 187.285 ;
     RECT  152.928 184.691 153.912 187.285 ;
     RECT  155.184 186.325 155.208 187.331 ;
     RECT  158.88 186.131 159.312 187.477 ;
     RECT  158.88 187.477 159.432 187.571 ;
     RECT  125.184 187.333 125.208 188.003 ;
     RECT  120.24 187.285 121.512 188.147 ;
     RECT  128.016 186.757 128.04 188.147 ;
     RECT  159 187.571 159.432 188.627 ;
     RECT  118.992 186.901 119.016 188.723 ;
     RECT  131.088 187.285 150.168 188.771 ;
     RECT  122.544 188.581 122.568 189.299 ;
     RECT  152.928 187.285 154.008 189.299 ;
     RECT  162.576 186.133 162.6 189.635 ;
     RECT  159 188.627 159.312 189.877 ;
     RECT  131.088 188.771 149.544 190.309 ;
     RECT  130.992 190.309 149.544 190.645 ;
     RECT  150.576 189.061 150.6 190.645 ;
     RECT  130.992 190.645 150.6 190.691 ;
     RECT  130.992 190.691 150.504 190.787 ;
     RECT  115.8 184.355 116.112 190.789 ;
     RECT  121.2 188.147 121.512 190.789 ;
     RECT  158.736 189.877 159.312 191.267 ;
     RECT  159 191.267 159.312 191.365 ;
     RECT  152.928 189.299 153.912 191.461 ;
     RECT  125.52 190.981 125.544 192.083 ;
     RECT  121.2 190.789 121.992 192.131 ;
     RECT  130.992 190.787 150.408 192.515 ;
     RECT  129.216 191.365 129.24 192.755 ;
     RECT  159 191.365 160.056 192.949 ;
     RECT  161.808 190.309 161.832 193.141 ;
     RECT  161.328 193.141 161.832 193.187 ;
     RECT  121.2 192.131 121.896 193.717 ;
     RECT  161.328 193.187 161.352 194.051 ;
     RECT  121.104 193.717 121.896 194.053 ;
     RECT  126.6 186.131 126.912 194.245 ;
     RECT  130.992 192.515 149.544 194.341 ;
     RECT  157.152 192.613 157.176 194.341 ;
     RECT  151.392 194.245 151.416 194.387 ;
     RECT  158.88 192.949 160.056 194.581 ;
     RECT  156.912 194.341 157.176 194.627 ;
     RECT  117.408 194.293 117.432 194.773 ;
     RECT  117.408 194.773 118.2 194.963 ;
     RECT  125.232 192.949 125.256 194.965 ;
     RECT  121.104 194.053 121.944 195.059 ;
     RECT  126.6 194.245 127.56 195.107 ;
     RECT  161.712 194.197 161.736 195.109 ;
     RECT  124.656 194.965 125.256 195.155 ;
     RECT  161.712 195.109 162.024 195.155 ;
     RECT  114.624 194.053 114.648 195.299 ;
     RECT  115.8 190.789 116.232 195.397 ;
     RECT  129.12 193.189 129.144 195.685 ;
     RECT  118.176 194.963 118.2 195.779 ;
     RECT  128.784 195.685 129.144 196.021 ;
     RECT  152.928 191.461 154.2 196.021 ;
     RECT  121.104 195.059 121.896 196.115 ;
     RECT  130.992 194.341 149.64 196.115 ;
     RECT  124.656 195.155 124.68 196.355 ;
     RECT  115.104 195.397 116.232 196.499 ;
     RECT  131.28 196.115 149.64 196.595 ;
     RECT  128.784 196.021 129.24 196.691 ;
     RECT  152.928 196.021 155.064 196.933 ;
     RECT  152.928 196.933 155.256 196.979 ;
     RECT  152.928 196.979 153.912 197.123 ;
     RECT  156.912 194.627 156.936 197.173 ;
     RECT  156.912 197.173 157.32 197.219 ;
     RECT  155.04 196.979 155.256 197.411 ;
     RECT  157.296 197.219 157.32 197.459 ;
     RECT  115.8 196.499 116.232 197.749 ;
     RECT  118.416 196.597 118.44 197.843 ;
     RECT  131.328 196.595 149.64 197.843 ;
     RECT  126.6 195.107 126.912 198.277 ;
     RECT  155.232 197.411 155.256 198.325 ;
     RECT  119.664 196.597 119.688 198.419 ;
     RECT  158.688 194.581 160.056 198.419 ;
     RECT  162 195.155 162.024 198.419 ;
     RECT  115.8 197.749 116.424 198.757 ;
     RECT  121.104 196.115 121.512 198.901 ;
     RECT  115.488 198.757 116.424 198.947 ;
     RECT  124.896 196.405 124.92 198.947 ;
     RECT  126.6 198.277 127.608 199.379 ;
     RECT  128.784 196.691 128.808 199.429 ;
     RECT  155.232 198.325 155.496 199.523 ;
     RECT  121.104 198.901 122.088 199.619 ;
     RECT  115.488 198.947 116.232 200.195 ;
     RECT  121.104 199.619 121.512 200.245 ;
     RECT  115.488 200.195 116.112 200.291 ;
     RECT  155.232 199.523 155.256 200.675 ;
     RECT  128.784 199.429 129.336 201.203 ;
     RECT  114 200.245 114.024 201.251 ;
     RECT  115.8 200.291 116.112 201.589 ;
     RECT  120.144 200.245 121.512 201.589 ;
     RECT  153.456 197.123 153.912 201.589 ;
     RECT  128.784 201.203 128.808 201.733 ;
     RECT  126.6 199.379 127.032 202.163 ;
     RECT  130.56 201.157 130.584 202.309 ;
     RECT  132 197.843 149.64 202.309 ;
     RECT  128.016 201.733 128.808 202.355 ;
     RECT  130.56 202.309 149.64 202.355 ;
     RECT  131.04 202.355 149.64 202.451 ;
     RECT  119.712 201.589 121.512 202.547 ;
     RECT  115.8 201.589 116.232 202.595 ;
     RECT  153.456 201.589 154.728 202.931 ;
     RECT  128.016 202.355 128.616 202.979 ;
     RECT  124.944 199.621 124.968 203.461 ;
     RECT  120.576 202.547 121.512 203.939 ;
     RECT  124.848 203.461 124.968 204.181 ;
     RECT  124.848 204.181 125.112 204.227 ;
     RECT  128.592 202.979 128.616 204.227 ;
     RECT  131.088 202.451 149.64 204.275 ;
     RECT  132 204.275 149.64 204.373 ;
     RECT  117.936 202.165 117.96 204.659 ;
     RECT  129.744 204.229 129.768 204.851 ;
     RECT  150.96 204.325 150.984 205.331 ;
     RECT  126.6 202.163 126.912 205.813 ;
     RECT  156.528 205.621 156.552 206.053 ;
     RECT  153.456 202.931 153.912 206.099 ;
     RECT  119.328 204.997 119.352 206.197 ;
     RECT  119.328 206.197 119.64 206.243 ;
     RECT  155.856 206.053 156.552 206.483 ;
     RECT  132 204.373 149.688 206.485 ;
     RECT  125.088 204.227 125.112 206.629 ;
     RECT  126.6 205.813 127.416 206.629 ;
     RECT  122.736 201.061 122.76 207.011 ;
     RECT  131.76 206.485 149.688 207.157 ;
     RECT  131.76 207.157 150.216 207.445 ;
     RECT  131.76 207.445 151.032 207.491 ;
     RECT  125.088 206.629 127.416 207.539 ;
     RECT  119.616 206.243 119.64 207.827 ;
     RECT  128.4 207.205 128.424 208.067 ;
     RECT  132 207.491 151.032 208.115 ;
     RECT  132 208.115 146.808 208.451 ;
     RECT  125.088 207.539 126.912 208.595 ;
     RECT  132 208.451 146.52 208.643 ;
     RECT  147.792 208.115 150.216 208.691 ;
     RECT  159 198.419 160.056 208.739 ;
     RECT  122.688 207.445 122.712 209.219 ;
     RECT  137.4 208.643 146.52 209.701 ;
     RECT  147.792 208.691 149.688 209.701 ;
     RECT  129.6 209.173 129.624 209.843 ;
     RECT  137.4 209.701 149.688 209.843 ;
     RECT  159 208.739 159.912 209.845 ;
     RECT  132 208.643 135.864 210.277 ;
     RECT  131.904 210.277 135.864 210.325 ;
     RECT  125.088 208.595 125.304 210.371 ;
     RECT  128.016 208.261 128.04 210.371 ;
     RECT  131.904 210.325 135.96 210.419 ;
     RECT  155.856 206.483 155.88 210.947 ;
     RECT  135.84 210.419 135.96 210.949 ;
     RECT  137.4 209.843 137.712 210.949 ;
     RECT  131.904 210.419 134.712 211.043 ;
     RECT  139.2 209.843 149.688 211.091 ;
     RECT  135.84 210.949 137.712 211.285 ;
     RECT  135.84 211.285 137.928 211.379 ;
     RECT  126.6 208.595 126.912 211.477 ;
     RECT  132 211.043 134.712 211.523 ;
     RECT  139.2 211.091 146.952 211.523 ;
     RECT  141.216 211.523 146.952 211.619 ;
     RECT  141.264 211.619 146.952 211.715 ;
     RECT  141.936 211.715 146.952 211.763 ;
     RECT  142.272 211.763 146.952 212.003 ;
     RECT  132 211.523 134.472 212.005 ;
     RECT  139.2 211.523 139.992 212.339 ;
     RECT  131.376 212.005 134.472 212.627 ;
     RECT  137.4 211.379 137.928 212.723 ;
     RECT  139.392 212.339 139.992 212.771 ;
     RECT  147.984 211.091 149.688 213.109 ;
     RECT  153.6 206.099 153.912 213.109 ;
     RECT  142.272 212.003 146.52 213.203 ;
     RECT  135.84 211.379 136.056 213.395 ;
     RECT  139.44 212.771 139.992 213.395 ;
     RECT  137.4 212.723 137.832 213.443 ;
     RECT  145.488 213.203 146.52 213.683 ;
     RECT  131.376 212.627 134.424 213.971 ;
     RECT  145.68 213.683 146.52 214.069 ;
     RECT  147.984 213.109 150.168 214.069 ;
     RECT  131.376 213.971 132.504 214.355 ;
     RECT  145.68 214.069 150.168 214.355 ;
     RECT  128.256 213.157 128.28 214.547 ;
     RECT  147.504 214.355 150.168 214.547 ;
     RECT  126.6 211.477 127.08 214.739 ;
     RECT  142.272 213.203 144.408 214.741 ;
     RECT  145.68 214.355 146.52 214.741 ;
     RECT  139.968 213.395 139.992 214.837 ;
     RECT  153.6 213.109 154.152 214.931 ;
     RECT  147.984 214.547 150.168 215.651 ;
     RECT  142.272 214.741 146.52 215.797 ;
     RECT  147.984 215.651 149.688 215.797 ;
     RECT  139.968 214.837 140.76 215.843 ;
     RECT  130.032 215.365 130.056 216.083 ;
     RECT  158.688 209.845 159.912 216.131 ;
     RECT  132 214.355 132.504 216.181 ;
     RECT  135.84 213.395 135.864 216.325 ;
     RECT  131.472 216.181 132.504 216.613 ;
     RECT  133.632 213.971 134.424 216.613 ;
     RECT  137.4 213.443 137.712 216.613 ;
     RECT  131.472 216.613 134.424 216.707 ;
     RECT  131.472 216.707 133.896 217.187 ;
     RECT  139.968 215.843 139.992 217.187 ;
     RECT  142.272 215.797 149.688 217.187 ;
     RECT  131.472 217.187 132.792 217.235 ;
     RECT  145.872 217.187 149.688 217.235 ;
     RECT  137.4 216.613 138.504 217.283 ;
     RECT  142.272 217.187 144.888 217.475 ;
     RECT  135.84 216.325 135.96 217.715 ;
     RECT  126.6 214.739 126.912 217.717 ;
     RECT  125.28 210.371 125.304 218.339 ;
     RECT  126.6 217.717 127.896 218.341 ;
     RECT  142.272 217.475 144.408 218.341 ;
     RECT  126.6 218.341 128.04 218.387 ;
     RECT  141.888 218.341 144.408 218.821 ;
     RECT  159 216.131 159.912 218.915 ;
     RECT  141.888 218.821 144.84 219.925 ;
     RECT  153.6 214.931 153.912 219.925 ;
     RECT  141.312 219.925 144.84 219.971 ;
     RECT  138.768 218.821 138.792 220.115 ;
     RECT  152.784 219.925 153.912 220.163 ;
     RECT  149.616 217.235 149.688 220.211 ;
     RECT  145.872 217.235 148.512 220.403 ;
     RECT  149.616 220.211 149.64 220.595 ;
     RECT  132 217.235 132.792 220.741 ;
     RECT  128.016 218.387 128.04 221.123 ;
     RECT  141.312 219.971 144.408 221.219 ;
     RECT  155.04 220.261 155.064 221.459 ;
     RECT  142.272 221.219 144.408 221.701 ;
     RECT  145.872 220.403 145.896 221.749 ;
     RECT  147.072 220.403 148.512 221.749 ;
     RECT  131.808 220.741 132.792 221.795 ;
     RECT  135.84 217.715 135.864 222.181 ;
     RECT  126.6 218.387 126.912 222.229 ;
     RECT  156.96 219.397 156.984 222.275 ;
     RECT  142.272 221.701 144.792 222.371 ;
     RECT  145.872 221.749 148.512 222.371 ;
     RECT  137.4 217.283 137.712 222.709 ;
     RECT  150.528 222.277 150.552 223.237 ;
     RECT  150.528 223.237 151.032 223.283 ;
     RECT  132 221.795 132.792 223.381 ;
     RECT  133.872 217.187 133.896 223.381 ;
     RECT  135.312 222.181 135.864 223.621 ;
     RECT  140.544 223.381 140.568 223.765 ;
     RECT  142.272 222.371 143.208 223.765 ;
     RECT  134.928 223.621 135.864 224.339 ;
     RECT  152.16 221.557 152.184 224.627 ;
     RECT  151.008 223.283 151.032 224.629 ;
     RECT  151.008 224.629 151.512 224.675 ;
     RECT  145.872 222.371 147.096 224.869 ;
     RECT  148.2 222.371 148.512 224.869 ;
     RECT  130.368 224.677 130.392 225.013 ;
     RECT  140.544 223.765 143.208 225.539 ;
     RECT  140.544 225.539 143.112 225.541 ;
     RECT  139.68 225.541 143.112 225.587 ;
     RECT  145.872 224.869 148.512 225.779 ;
     RECT  135.12 224.339 135.864 226.069 ;
     RECT  132 223.381 133.896 226.307 ;
     RECT  126.288 222.229 126.912 226.355 ;
     RECT  129.6 225.013 130.392 226.355 ;
     RECT  145.872 225.779 145.896 226.355 ;
     RECT  139.68 225.587 140.712 226.451 ;
     RECT  139.68 226.451 139.704 226.499 ;
     RECT  129.6 226.355 129.624 226.501 ;
     RECT  147.072 225.779 148.512 226.547 ;
     RECT  134.976 226.069 135.864 226.645 ;
     RECT  137.4 222.709 137.976 226.645 ;
     RECT  134.976 226.645 137.976 226.691 ;
     RECT  141.936 225.587 143.112 226.979 ;
     RECT  144.384 222.371 144.408 227.173 ;
     RECT  128.688 226.501 129.624 227.699 ;
     RECT  147.456 226.547 148.512 227.989 ;
     RECT  142.272 226.979 143.112 228.517 ;
     RECT  144.384 227.173 144.792 228.563 ;
     RECT  147.456 227.989 148.776 228.611 ;
     RECT  134.976 226.691 137.712 229.093 ;
     RECT  128.688 227.699 128.712 229.187 ;
     RECT  132 226.307 132.984 229.187 ;
     RECT  130.8 228.517 130.824 229.667 ;
     RECT  139.68 228.565 139.704 229.859 ;
     RECT  134.208 229.093 137.712 230.147 ;
     RECT  151.488 224.675 151.512 230.147 ;
     RECT  147.456 228.611 148.512 230.245 ;
     RECT  134.208 230.147 135.864 230.291 ;
     RECT  142.272 228.517 143.4 230.387 ;
     RECT  140.688 226.451 140.712 230.773 ;
     RECT  140.016 230.773 140.712 230.915 ;
     RECT  137.4 230.147 137.712 231.493 ;
     RECT  137.4 231.493 137.832 231.827 ;
     RECT  132 229.187 132.312 231.925 ;
     RECT  129.36 230.293 129.384 232.019 ;
     RECT  133.968 231.301 133.992 232.019 ;
     RECT  140.016 230.915 140.04 232.021 ;
     RECT  140.016 232.021 140.376 232.067 ;
     RECT  150.048 230.101 150.072 232.403 ;
     RECT  147.024 230.245 148.512 232.453 ;
     RECT  146.448 232.453 148.512 232.499 ;
     RECT  134.976 230.291 135.864 232.981 ;
     RECT  142.272 230.387 143.112 233.653 ;
     RECT  144.384 228.563 144.408 233.653 ;
     RECT  131.616 231.925 132.312 233.939 ;
     RECT  134.112 232.981 135.864 233.939 ;
     RECT  137.4 231.827 137.712 233.989 ;
     RECT  132 233.939 132.312 234.037 ;
     RECT  146.448 232.499 146.472 234.179 ;
     RECT  147.456 232.499 148.512 234.181 ;
     RECT  142.272 233.653 144.408 234.323 ;
     RECT  147.456 234.181 148.632 234.515 ;
     RECT  134.976 233.939 135.864 234.709 ;
     RECT  137.4 233.989 138.696 234.709 ;
     RECT  132 234.037 133.272 234.899 ;
     RECT  134.976 234.709 138.696 235.187 ;
     RECT  140.352 232.067 140.376 235.235 ;
     RECT  146.208 234.565 146.232 235.237 ;
     RECT  147.456 234.515 148.512 235.237 ;
     RECT  146.208 235.237 148.512 235.283 ;
     RECT  132 234.899 133.224 235.381 ;
     RECT  146.496 235.283 148.512 235.571 ;
     RECT  142.272 234.323 143.784 236.291 ;
     RECT  146.976 235.571 148.512 236.579 ;
     RECT  131.088 235.381 133.224 237.395 ;
     RECT  131.904 237.395 133.224 237.829 ;
     RECT  134.976 235.187 135.864 237.829 ;
     RECT  131.904 237.829 135.864 237.971 ;
     RECT  131.904 237.971 132.312 238.307 ;
     RECT  140.976 237.493 141 238.355 ;
     RECT  134.16 237.971 135.864 238.883 ;
     RECT  137.4 235.187 138.696 238.883 ;
     RECT  132 238.307 132.312 240.469 ;
     RECT  145.92 238.981 145.944 240.517 ;
     RECT  134.208 238.883 135.864 240.563 ;
     RECT  145.824 240.517 145.944 240.563 ;
     RECT  141.168 239.941 141.192 240.611 ;
     RECT  132 240.469 133.128 241.715 ;
     RECT  147.456 236.579 148.512 241.715 ;
     RECT  135.84 240.563 135.864 242.197 ;
     RECT  142.272 236.291 143.112 242.291 ;
     RECT  145.824 240.563 145.848 243.061 ;
     RECT  145.824 243.061 146.52 243.107 ;
     RECT  132 241.715 132.312 243.349 ;
     RECT  139.344 239.557 139.368 243.349 ;
     RECT  142.8 242.291 143.112 243.349 ;
     RECT  139.344 243.349 139.656 243.395 ;
     RECT  137.4 238.883 137.712 244.357 ;
     RECT  135.84 242.197 136.056 244.403 ;
     RECT  146.496 243.107 146.52 244.451 ;
     RECT  142.8 243.349 143.208 244.979 ;
     RECT  139.632 243.395 139.656 245.123 ;
     RECT  137.28 244.357 137.712 245.267 ;
     RECT  142.8 244.979 143.112 246.565 ;
     RECT  140.64 243.733 140.664 246.611 ;
     RECT  141.84 246.565 143.112 246.899 ;
     RECT  135.84 244.403 135.864 275.939 ;
     RECT  2.4 2.151 2.712 369.369 ;
     RECT  7.8 2.151 8.112 369.369 ;
     RECT  13.2 2.151 13.512 369.369 ;
     RECT  18.6 2.151 18.912 369.369 ;
     RECT  24 2.151 24.312 369.369 ;
     RECT  29.4 2.151 29.712 369.369 ;
     RECT  34.8 2.151 35.112 369.369 ;
     RECT  40.2 2.151 40.512 369.369 ;
     RECT  45.6 2.151 45.912 369.369 ;
     RECT  51 2.151 51.312 369.369 ;
     RECT  56.4 2.151 56.712 369.369 ;
     RECT  61.8 2.151 62.112 369.369 ;
     RECT  67.2 2.151 67.512 369.369 ;
     RECT  72.6 2.151 72.912 369.369 ;
     RECT  78 2.151 78.312 369.369 ;
     RECT  83.4 2.151 83.712 369.369 ;
     RECT  88.8 2.151 89.112 369.369 ;
     RECT  94.2 2.151 94.512 369.369 ;
     RECT  99.6 2.151 99.912 369.369 ;
     RECT  105 2.151 105.312 369.369 ;
     RECT  110.4 2.151 110.712 369.369 ;
     RECT  115.8 202.595 116.112 369.369 ;
     RECT  121.2 203.939 121.512 369.369 ;
     RECT  126.6 226.355 126.912 369.369 ;
     RECT  137.4 245.267 137.712 369.369 ;
     RECT  142.8 246.899 143.112 369.369 ;
     RECT  148.2 241.715 148.512 369.369 ;
     RECT  153.6 220.163 153.912 369.369 ;
     RECT  159 218.915 159.312 369.369 ;
     RECT  164.4 2.151 164.712 369.369 ;
     RECT  169.8 187.187 170.112 369.369 ;
     RECT  175.2 2.151 175.512 369.369 ;
     RECT  180.6 2.151 180.912 369.369 ;
     RECT  186 2.151 186.312 369.369 ;
     RECT  191.4 2.151 191.712 369.369 ;
     RECT  196.8 2.151 197.112 369.369 ;
     RECT  202.2 2.151 202.512 369.369 ;
     RECT  207.6 2.151 207.912 369.369 ;
     RECT  213 2.151 213.312 369.369 ;
     RECT  218.4 2.151 218.712 369.369 ;
     RECT  223.8 2.151 224.112 369.369 ;
     RECT  229.2 2.151 229.512 369.369 ;
     RECT  234.6 2.151 234.912 369.369 ;
     RECT  240 2.151 240.312 369.369 ;
     RECT  245.4 2.151 245.712 369.369 ;
     RECT  2.4 369.369 2.52 369.383 ;
     RECT  7.8 369.369 7.92 369.383 ;
     RECT  13.2 369.369 13.32 369.383 ;
     RECT  18.6 369.369 18.72 369.383 ;
     RECT  24 369.369 24.12 369.383 ;
     RECT  29.4 369.369 29.52 369.383 ;
     RECT  34.8 369.369 34.92 369.383 ;
     RECT  40.2 369.369 40.32 369.383 ;
     RECT  45.6 369.369 45.72 369.383 ;
     RECT  51 369.369 51.12 369.383 ;
     RECT  56.4 369.369 56.52 369.383 ;
     RECT  61.8 369.369 61.92 369.383 ;
     RECT  67.2 369.369 67.32 369.383 ;
     RECT  72.6 369.369 72.72 369.383 ;
     RECT  78 369.369 78.12 369.383 ;
     RECT  83.4 369.369 83.52 369.383 ;
     RECT  88.8 369.369 88.92 369.383 ;
     RECT  94.2 369.369 94.32 369.383 ;
     RECT  99.6 369.369 99.72 369.383 ;
     RECT  105 369.369 105.12 369.383 ;
     RECT  110.4 369.369 110.52 369.383 ;
     RECT  115.8 369.369 115.92 369.383 ;
     RECT  121.2 369.369 121.32 369.383 ;
     RECT  126.6 369.369 126.72 369.383 ;
     RECT  132 243.349 132.552 369.383 ;
     RECT  137.4 369.369 137.52 369.383 ;
     RECT  142.8 369.369 142.92 369.383 ;
     RECT  148.2 369.369 148.32 369.383 ;
     RECT  153.6 369.369 153.72 369.383 ;
     RECT  159 369.369 159.12 369.383 ;
     RECT  164.4 369.369 164.52 369.383 ;
     RECT  169.8 369.369 169.92 369.383 ;
     RECT  175.2 369.369 175.32 369.383 ;
     RECT  180.6 369.369 180.72 369.383 ;
     RECT  186 369.369 186.12 369.383 ;
     RECT  191.4 369.369 191.52 369.383 ;
     RECT  196.8 369.369 196.92 369.383 ;
     RECT  202.2 369.369 202.32 369.383 ;
     RECT  207.6 369.369 207.72 369.383 ;
     RECT  213 369.369 213.12 369.383 ;
     RECT  218.4 369.369 218.52 369.383 ;
     RECT  223.8 369.369 223.92 369.383 ;
     RECT  229.2 369.369 229.32 369.383 ;
     RECT  234.6 369.369 234.72 369.383 ;
     RECT  240 369.369 240.12 369.383 ;
     RECT  245.4 369.369 245.52 369.383 ;
     RECT  132.432 369.383 132.552 371.077 ;
     RECT  132.24 371.077 132.552 371.267 ;
     RECT  132.24 371.267 132.456 371.365 ;
     RECT  132.144 371.365 132.456 371.472 ;
  END
END ot_qwen_ctrl_pc
END LIBRARY
